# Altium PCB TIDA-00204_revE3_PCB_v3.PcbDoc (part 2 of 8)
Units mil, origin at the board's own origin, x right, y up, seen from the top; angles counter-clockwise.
Board outline 4600 x 3740 mil, 8 copper layers (TopLayer - S1 (.GTL), MidLayer1 - S2 (.G1), MidLayer2 - S3 (.G2), MidLayer3 - S4 (.G3), MidLayer4 - S5 (.G4), MidLayer5 - S6 (.G5), MidLayer6 - S7 (.G6), BottomLayer - S8 (.GBL)), stack 58.938 mil thick; 537 components, 354 nets, 2015 pads, 1067 vias.

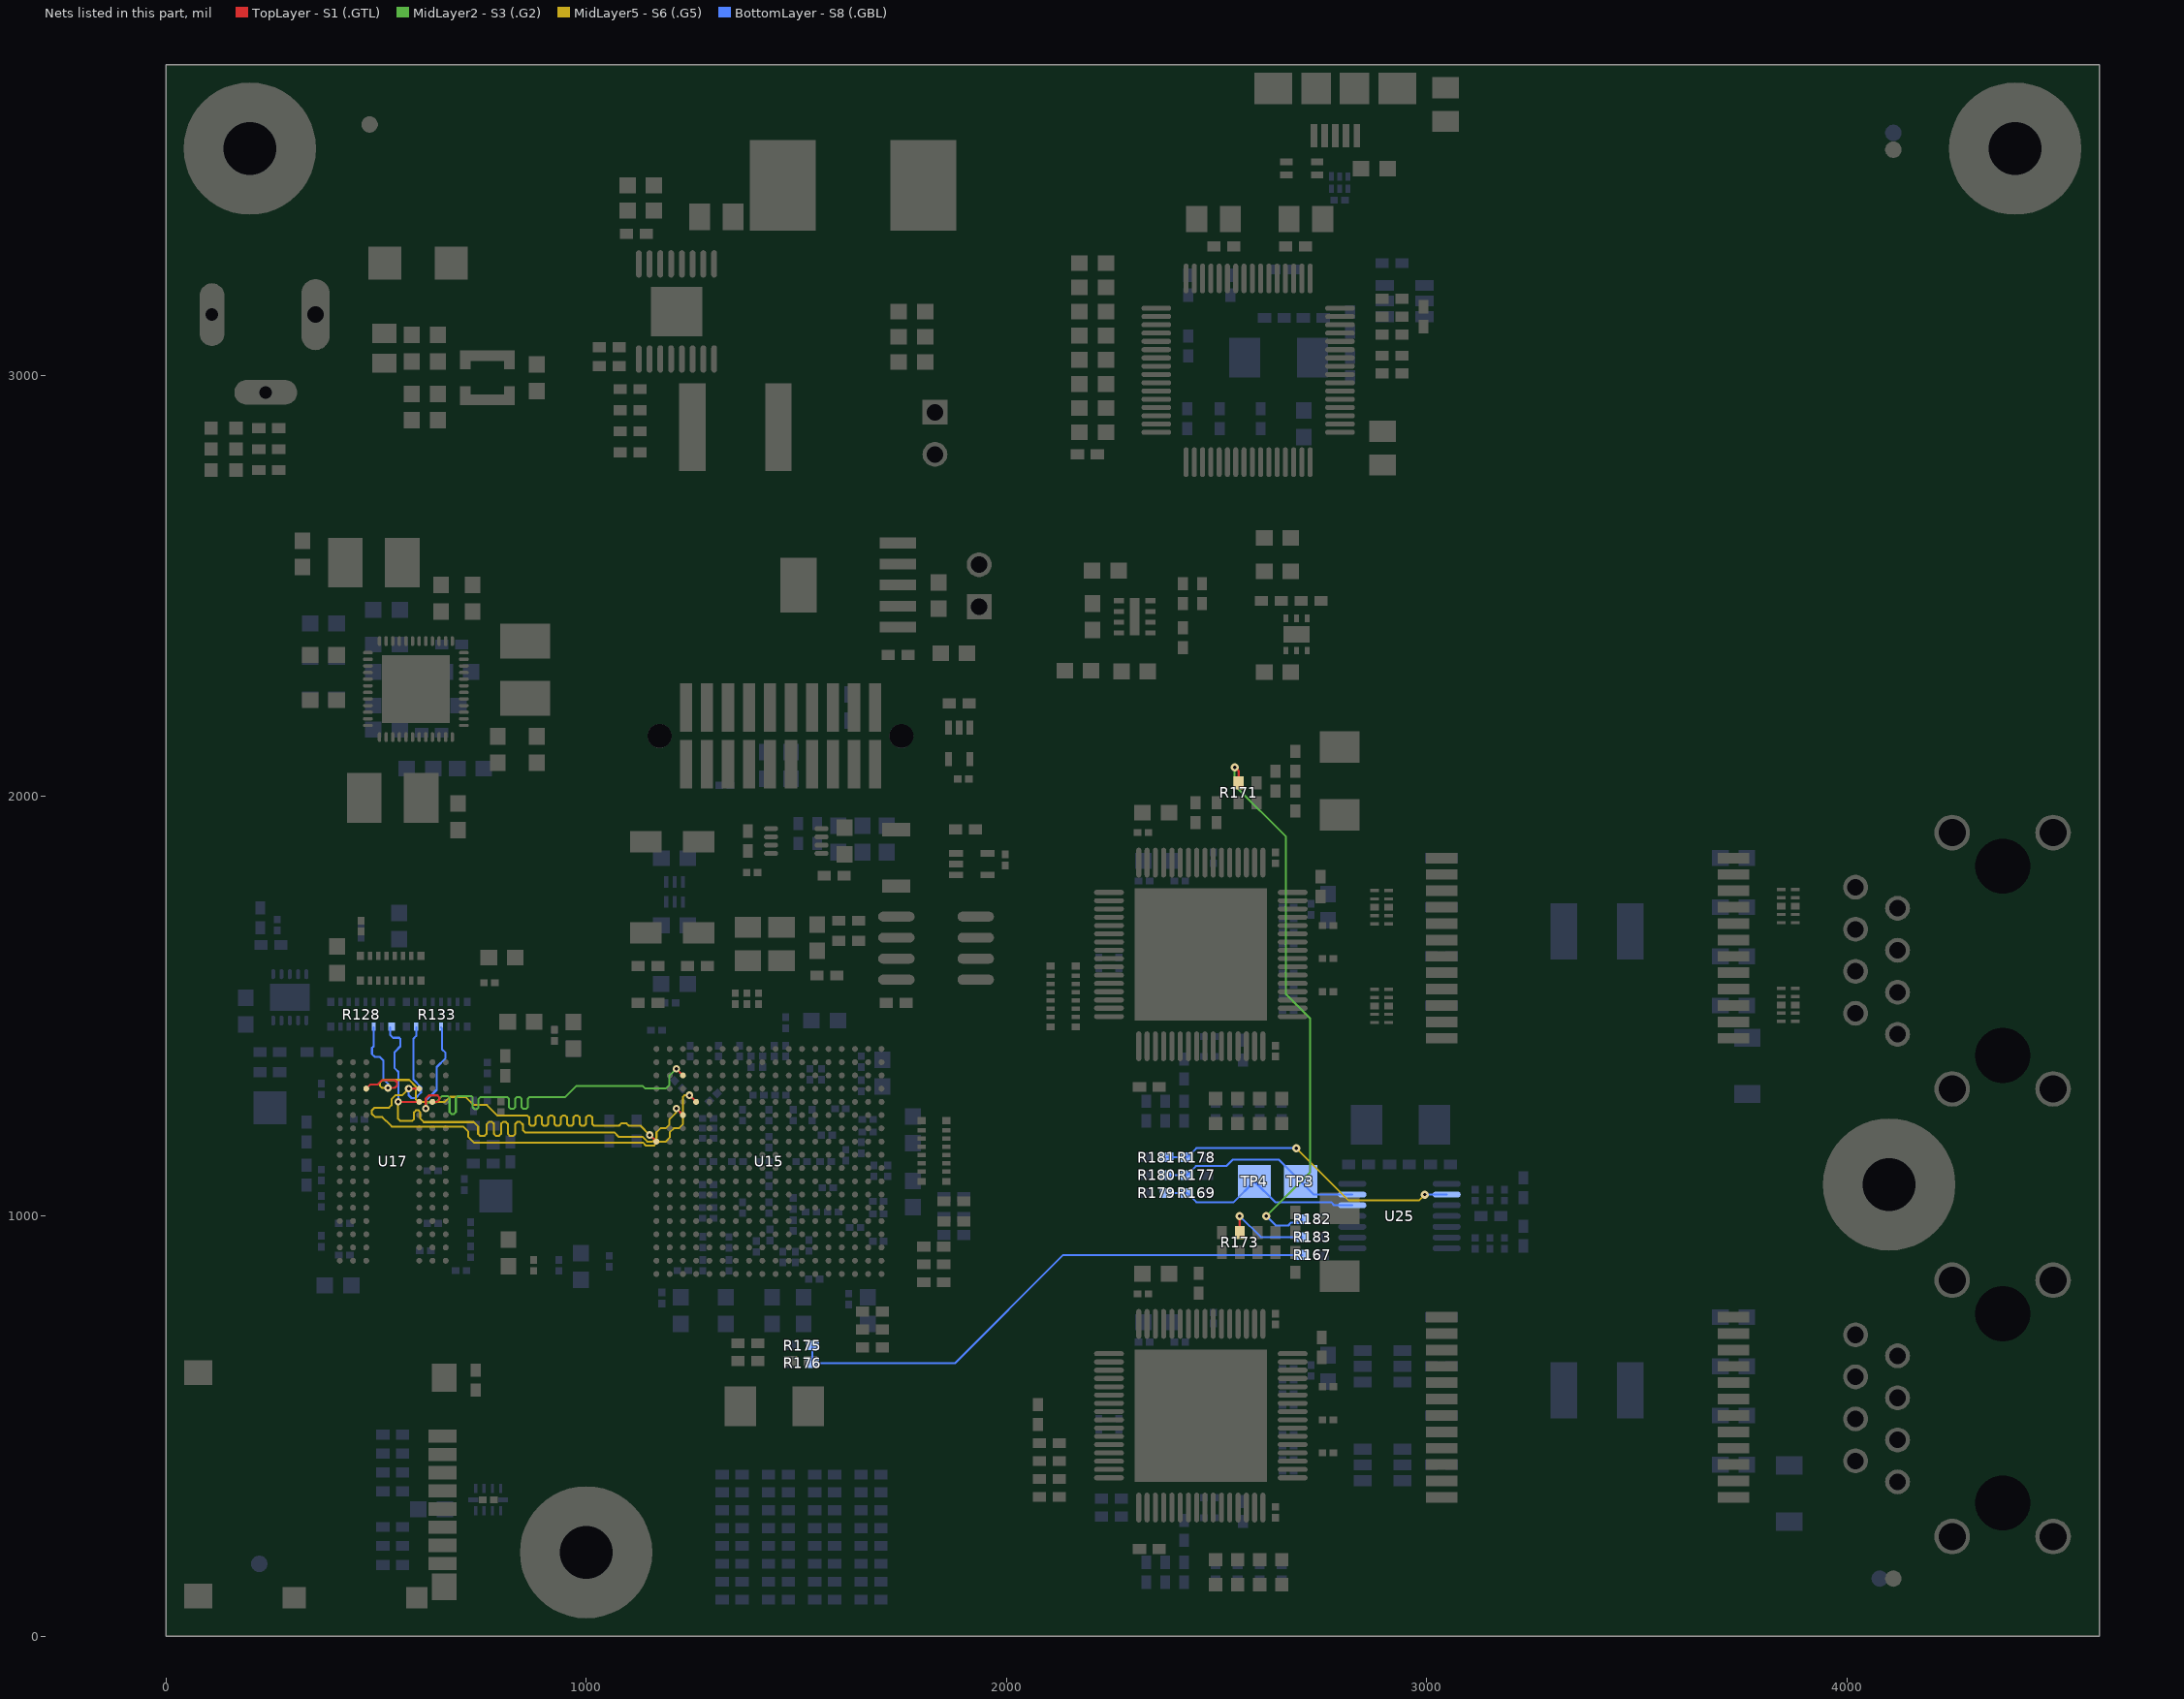
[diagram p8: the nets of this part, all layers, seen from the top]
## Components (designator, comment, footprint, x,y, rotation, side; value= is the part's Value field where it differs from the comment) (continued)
R139 "CRCW06030000Z0EA" 0603 2205,3267.5 r180 top
R140 "CRCW06030000Z0EA" 0603 2205,3210 r180 top
R141 "CRCW06030000Z0EA" 0603 2205,3152.5 r180 top
R142 "CRCW06030000Z0EA" 0603 2205,3095 r180 top
R143 "CRCW06030000Z0EA" 0603 2205,3037.5 r180 top
R144 "CRCW06030000Z0EA" 0603 2205,2980 r180 top
R145 "CRCW06030000Z0EA" 0603 2205,2922.5 r180 top
R146 "CRCW04024K70JNED" 0402 2192.5,2812.5 r0 top
R147 "CRCW06030000Z0EA" 0603 2205,2865 r180 top
R148 "CRCW040210K0JNED" 0402 2917.5,3182.5 r0 top
R149 "CRCW040210K0JNED" 0402 2917.5,3140 r0 top
R150 "CRCW040210K0JNED" 0402 2992.5,3140 r90 top
R151 "CRCW04024K70JNED" 0402 1287.5,2227.5 r90 bottom
R152 "CRCW04024K70JNED" 0402 1505,1910 r270 bottom
R153 "CRCW04024K70JNED" 0402 1237.5,2227.5 r90 bottom
R154 "CRCW04022K20JNED" 0402 2917.5,3097.5 r180 top
R155 "CRCW04024K75FKED" 0402 2917.5,3005 r0 top
R156 "CRCW04022K20JNED" 0402 2432.5,3215 r90 bottom
R157 "CRCW040212K1FKED" 0402 2660,3252.5 r180 bottom
R158 "CRCW040210K0FKED" 0402 2917.5,3047.5 r180 top
R159 "CRCW06030000Z0EA" 0603 1430,2072.5 r270 bottom
R160 "CRCW06030000Z0EA" 0603 1487.5,2072.5 r270 bottom
R161 "CRCW06030000Z0EA" 0603 1657.5,1897.5 r90 bottom
R162 "CRCW06030000Z0EA" 0603 1632.5,2210 r90 bottom
R163 "CRCW06030000Z0EA" 0603 1715,1897.5 r90 bottom
R164 "CRCW06030000Z0EA" 0603 1600,1897.5 r90 bottom
R165 "CRCW04024K70JNED" 0402 1887.5,2220 r0 top
R166 "CRCW04024K70JNED" 0402 3152.5,1000 r180 bottom
R167 "CRCW040236R0JNED" 0402 2727.5,907.5 r180 bottom
R168 "CRCW04021M00FKED" 0402 2935,1122.5 r180 bottom
R169 "CRCW04021K00FKED" 0402 2452.5,1055 r0 bottom
R170 "CRCW04020000Z0ED" 0402 2595,2007.5 r270 top
R171 "CRCW04020000Z0ED" 0402 2552.5,2007.5 r90 top
R172 "CRCW04020000Z0ED" 0402 2597.5,937.5 r270 top
R173 "CRCW04020000Z0ED" 0402 2555,937.5 r90 top
R174 "CRCW04020000Z0ED" 0402 1385,697.5 r180 top
R175 "CRCW04020000Z0ED" 0402 1515,692.5 r0 bottom
R176 "CRCW040249R9FKED" 0402 1515,650 r0 bottom
R177 "CRCW04021K00FKED" 0402 2452.5,1097.5 r0 bottom
R178 "CRCW04021K00FKED" 0402 2452.5,1140 r0 bottom
R179 "CRCW04021K00FKED" 0402 2357.5,1055 r0 bottom
R180 "CRCW04021K00FKED" 0402 2357.5,1097.5 r0 bottom
R181 "CRCW04021K00FKED" 0402 2357.5,1140 r0 bottom
R182 "CRCW040236R0JNED" 0402 2727.5,992.5 r180 bottom
R183 "CRCW040236R0JNED" 0402 2727.5,950 r180 bottom
S1 "B3U-1000P" SW_B3U-1000P 1737.5,1852.5 r270 top
T1 "HX5008FNL" PULSE_HX5008FNL 3382.5,1637.5 r0 top
T2 "HX5008FNL" PULSE_HX5008FNL 3382.5,545 r0 top
TP1 "TESTPOINT" OXLEY_SMOX_060_B1_LP 247.5,1257.5 r270 bottom
TP2 "TESTPOINT" OXLEY_SMOX_060_B1_LP 785,1047.5 r270 bottom
TP3 "TESTPOINT" OXLEY_SMOX_060_B1_LP 2700,1082.5 r180 bottom
TP4 "TESTPOINT" OXLEY_SMOX_060_B1_LP 2590,1082.5 r180 bottom
U1 "LM46002PWP" PWP0016A_N 1215,3152.5 r270 top
U2 "TPS73733DCQ" DCQ0006A_N 1623.5,2501.5 r180 top
U3 "LMZ10501SIL" SIL0008A 2305,2426 r180 top
U5 "TPS72011DRV" DRV0006A 2690,2384 r90 top
U6 "DP83867IRPAPR" PAP0064M_N 2462.5,1622.5 r180 top
U7 "TPD4E05U06DQA" DQA0010A 2892.5,1735 r180 top
U8 "TPD4E05U06DQA" DQA0010A 3860,1737.5 r180 top
U9 "TPD4E05U06DQA" DQA0010A 2892.5,1500 r180 top
U10 "TPD4E05U06DQA" DQA0010A 3860,1502.5 r180 top
U11 "SN74AHC1G08DCK" DCK0005A_N 1917.5,1837.5 r0 top
U12 "DP83867IRPAPR" PAP0064M_N 2462.5,525 r180 top
U13 "TPS65910A3A1RSL" RSL0048A 595,2254 r0 top
U14 "TPS71718DSER" DSE0006A 1210.47,1771.69 r90 bottom
U15 "AM3359BZCZA80" ZCZ0324A 1435,1130 r0 top locked
U16 "SN74AUP2G08DCU" DCU0008A_N 1500,1892.5 r180 top
U17 "MT41J128M16JT-125K TR" 96-FBGA 540,1130 r180 top
U18 "TPD6E001RSER" RSE0010A 767.28,325 r270 bottom
U19 "CAT24C256WI-GT3" SOIC-8 1832.5,1637.5 r180 top
U20 "TPS51200DRCR" DRC0010A 295,1520.5 r270 bottom
U21 "TPD4S012DRYR" DRY0006A_GCD 2792.5,3459 r270 bottom
U22 "FT2232HL-REEL" LQFP64_N 2575,3012.5 r270 top
U23 "93LC56B-I/OT" SOT-23-6 2947.5,3177.5 r180 bottom
U24 "SN74LVC1G06DCK" DCK0005A_N 1887.5,2125 r270 top
U25 "CDCE913PW" PW0014A_N 2935,1000 r180 bottom
Y1 "ABM3-25.000MHZ-D2Y-T" XTAL_ABM3 2792.5,2035 r90 top
Y2 "ABM3-25.000MHZ-D2Y-T" XTAL_ABM3 2792.5,937.5 r90 top
Y3 "ABM3-24.000MHZ-D2Y-T" XTAL_ABM3 1447.5,547.5 r180 top
Y4 "MC-306 32.7680K-A0:ROHS" XTAL_MC-306 1205,1782.5 r180 top
Y5 "ABM3-12.000MHZ-D2Y-T" XTAL_ABM3 2647.5,3042.5 r0 bottom
Y6 "ABM3-25.000MHZ-D2Y-T" XTAL_ABM3 2937.5,1217.5 r180 bottom

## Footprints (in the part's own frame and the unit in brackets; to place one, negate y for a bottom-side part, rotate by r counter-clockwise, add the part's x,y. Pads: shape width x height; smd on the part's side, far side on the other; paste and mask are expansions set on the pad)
96-FBGA [mil] "BGA, 96-Balls, Body 9x14mm, Pitch 0.8mm"
  round 14 smd: A1(-125.98,236.22) A2(-94.49,236.22) A3(-62.99,236.22) A7(62.99,236.22) A8(94.49,236.22) A9(125.98,236.22) B1(-125.98,204.72) B2(-94.49,204.72) B3(-62.99,204.72) B7(62.99,204.72) B8(94.49,204.72) B9(125.98,204.72) C1(-125.98,173.23) C2(-94.49,173.23) C3(-62.99,173.23) C7(62.99,173.23) C8(94.49,173.23) C9(125.98,173.23) D1(-125.98,141.73) D2(-94.49,141.73) D3(-62.99,141.73) D7(62.99,141.73) D8(94.49,141.73) D9(125.98,141.73) E1(-125.98,110.24) E2(-94.49,110.24) E3(-62.99,110.24) E7(62.99,110.24) E8(94.49,110.24) E9(125.98,110.24) F1(-125.98,78.74) F2(-94.49,78.74) F3(-62.99,78.74) F7(62.99,78.74) F8(94.49,78.74) F9(125.98,78.74) G1(-125.98,47.24) G2(-94.49,47.24) G3(-62.99,47.24) G7(62.99,47.24) G8(94.49,47.24) G9(125.98,47.24) H1(-125.98,15.75) H2(-94.49,15.75) H3(-62.99,15.75) H7(62.99,15.75) H8(94.49,15.75) H9(125.98,15.75) J1(-125.98,-15.75) J2(-94.49,-15.75) J3(-62.99,-15.75) J7(62.99,-15.75) J8(94.49,-15.75) J9(125.98,-15.75) K1(-125.98,-47.24) K2(-94.49,-47.24) K3(-62.99,-47.24) K7(62.99,-47.24) K8(94.49,-47.24) K9(125.98,-47.24) L1(-125.98,-78.74) L2(-94.49,-78.74) L3(-62.99,-78.74) L7(62.99,-78.74) L8(94.49,-78.74) L9(125.98,-78.74) M1(-125.98,-110.24) M2(-94.49,-110.24) M3(-62.99,-110.24) M7(62.99,-110.24) M8(94.49,-110.24) M9(125.98,-110.24) N1(-125.98,-141.73) N2(-94.49,-141.73) N3(-62.99,-141.73) N7(62.99,-141.73) N8(94.49,-141.73) N9(125.98,-141.73) P1(-125.98,-173.23) P2(-94.49,-173.23) P3(-62.99,-173.23) P7(62.99,-173.23) P8(94.49,-173.23) P9(125.98,-173.23) R1(-125.98,-204.72) R2(-94.49,-204.72) R3(-62.99,-204.72) R7(62.99,-204.72) R8(94.49,-204.72) R9(125.98,-204.72) T1(-125.98,-236.22) T2(-94.49,-236.22) T3(-62.99,-236.22) T7(62.99,-236.22) T8(94.49,-236.22) T9(125.98,-236.22)
  silkscreen extent -208,-276 177,276, body extent -177,-276 177,276, height 48
0201 [mm] "Data from Kemet datasheet CC101_COM dated 7/28/11"
  rect 0.46x0.42 smd mask+0.048: 1(-0.33,0) 2(0.33,0)
  body extent -0.31,-0.16 0.31,0.16, height 0.26
0402 [mm] "0402 from SM-752 data"
  rect 0.8x0.6 smd: 1(-0.6,0) 2(0.6,0)
  silkscreen extent -1.22,-0.52 1.22,0.52, body extent -0.55,-0.3 0.55,0.3, height 0.6
0603 [mm] "0603 from SM-752 data"
  rect 1x0.95 smd: 1(-0.8,0) 2(0.8,0)
  silkscreen extent -1.52,-0.69 1.52,0.69, body extent -0.87,-0.47 0.87,0.47, height 0.85
0805_145 [mm] "0805 / 1.45mm height"
  rect 1.15x1.45 smd: 1(-0.9,0) 2(0.9,0)
  silkscreen extent -0.1,-0.8 0.1,0.8, body extent -1.1,-0.72 1.1,0.72, height 1.45
0805_HV [mil] "0805 with 30mil clearance between pads"
  rect 50x63 smd: 1(-40,0) 2(40,0)
  silkscreen extent -72,-40 74,40, body extent -43,-29 43,29, height 43
1206_190 [mm] "1206_190"
  rect 1.1x1.6 smd: 1(-1.7,0) 2(1.7,0)
  silkscreen extent -0.9,-1 0.9,1, body extent -1.75,-0.95 1.75,0.95, height 1.9
1812 [mm]
  rect 1.6x3.4 smd: 1(-2,0) 2(2,0)
  silkscreen extent -0.8,-1.6 0.8,1.6, body extent -2.4,-1.7 2.4,1.7, height 1.35
2220 [mm] "Chip Capacitor, Body 5.7x5.0mm, IPC Medium Density"
  rect 1.6x5.3 smd: 1(-2.6,0) 2(2.6,0)
  silkscreen extent -3.69,-2.94 3.69,2.94, body extent -2.95,-2.62 2.95,2.62, height 1.35
CONN_PEC02SAAN [mm] "SULLINS"
  rect 1.5x1.5 hole 1: 1(-1.27,0)
  round 1.5 hole 1: 2(1.27,0)
  silkscreen extent -3.45,-1.27 2.54,1.27, body extent -2.54,-1.27 2.54,1.27, height 8.38
CONN_RAPC722X [mm] "Conn_DC Jack"
  oval 1.7x4.3 hole 1.01 slot 3.56 at 90 deg: 1(-13.741,0)
  oval 1.5x3.8 hole 0.76 slot 3.05 at 90 deg: 2(-7.493,0)
  oval 3.8x1.5 hole 0.76 slot 3.05 at 0 deg: 3(-10.744,4.7)
  silkscreen extent -14.48,-4.57 0.25,4.57, body extent -14.5,-4.57 0.23,4.83, height 11.18
DCK0005A_N [mm] "SOT353, 5-Leads, Body 2x1.3mm, Pitch 0.65mm, Lead Span 2.1mm, IPC Medium Density"
  rect 0.85x0.4 smd: 1(-0.95,0.65) 2(-0.95,0) 3(-0.95,-0.65) 4(0.95,-0.65) 5(0.95,0.65)
  silkscreen extent -0.15,-1.1 0.15,1.1, body extent -1.14,-1 1.14,1, height 0.94
DCQ0006A_N [mm] "SOT223, 6-Leads, Body 6.6x7.3mm (max), Pitch 1.27mm, IPC Medium Density"
  rect 2.2x0.65 smd: 1(-3,2.54) 2(-3,1.27) 3(-3,0) 4(-3,-1.27) 5(-3,-2.54)
  rect 2.2x3.3 smd: 6(3,0)
  silkscreen extent -1.5,-3.27 1.5,3.27, body extent -3.48,-3.25 3.48,3.25, height 1.64
DCU0008A_N [mm] "TSSOP, 8-Leads, Body 2x2.3mm, Pitch 0.5mm, IPC Medium Density"
  oval 0.85x0.3 smd: 1(-1.525,0.75) 2(-1.525,0.25) 3(-1.525,-0.25) 4(-1.525,-0.75) 5(1.525,-0.75) 6(1.525,-0.25) 7(1.525,0.25) 8(1.525,0.75)
  silkscreen extent -0.6,-1.05 0.6,1.05, body extent -1.2,-1.05 1.2,1.05, height 0.91
DQA0010A [mm] "SON, 10-Leads, Body 1x2.5mm, Pitch 0.5mm, TI Recommended"
  rect 0.55x0.2 smd: 1(-0.425,1) 2(-0.425,0.5) 4(-0.425,-0.5) 5(-0.425,-1) 6(0.425,-1) 7(0.425,-0.5) 9(0.425,0.5) 10(0.425,1)
  rect 0.55x0.4 smd: 3(-0.425,0) 8(0.425,0)
  silkscreen extent -1,-1.45 0.55,1.5, body extent -0.55,-1.3 0.55,1.3, height 0.56
DRC0010A [mm] "SON, 10-Leads, Body 3x3mm, Pitch 0.5mm, Thermal Pad 2.4x1.65mm, TI Recommended"
  oval 0.6x0.24 smd: 1(-1.4,1) 2(-1.4,0.5) 3(-1.4,0) 4(-1.4,-0.5) 5(-1.4,-1) 6(1.4,-1) 7(1.4,-0.5) 8(1.4,0) 9(1.4,0.5) 10(1.4,1)
  rect 1.65x2.4 smd paste-0.825: 11(0,0)
  TopLayer - S1 (.GTL) region: 0.135,-1.1 0.365,-1.1 0.365,-1.5 0.135,-1.5
  TopLayer - S1 (.GTL) region: -0.135,-1.5 -0.365,-1.5 -0.365,-1.1 -0.135,-1.1
  TopLayer - S1 (.GTL) region: -0.135,1.1 -0.365,1.1 -0.365,1.5 -0.135,1.5
  TopLayer - S1 (.GTL) region: 0.135,1.5 0.365,1.5 0.365,1.1 0.135,1.1
  silkscreen extent -1.7,-1.7 1.7,1.7, body extent -1.55,-1.55 1.55,1.55, height 1.01
DRV0006A [mm] "SON, 6-Leads, Body 2x2mm, Pitch 0.65mm, Thermal Pad 1.6x1mm, TI Recommended"
  rect 0.45x0.3 smd: 1(-0.975,0.65) 2(-0.975,0) 3(-0.975,-0.65) 4(0.975,-0.65) 5(0.975,0) 6(0.975,0.65)
  rect 1x1.6 smd paste-0.5: 7(0,0)
  silkscreen extent -1.05,-1.2 1.05,1.2, body extent -1.05,-1.05 1.05,1.05, height 0.81
DRY0006A_GCD [mm] "PSON, 6-Leads, Body 1x1.45mm, Pitch 0.5mm, TI Recommended"
  rect 0.52x0.3 smd mask+0.05: 1(-0.38,0.5)
  rect 0.49x0.3 smd: 2(-0.375,0) 3(-0.375,-0.5) 4(0.375,-0.5) 5(0.375,0) 6(0.375,0.5)
  silkscreen extent -0.67,0.8 -0.58,0.9, body extent -0.53,-0.75 0.53,0.75, height 0.61
DSE0006A [mm] "TI recommended land pattern"
  rect 0.66x0.25 smd: 1(-0.62,0.5)
  rect 0.7x0.25 smd: 2(-0.6,0) 3(-0.6,-0.5) 4(0.6,-0.5) 5(0.6,0) 6(0.6,0.5)
  TopLayer - S1 (.GTL) region: -0.3,0.625 -0.25,0.625 -0.15,0.525 -0.15,0.375 -0.3,0.375
  silkscreen extent -0.9,-0.92 0.9,0.92, body extent -0.77,-0.77 0.77,0.77, height 0.8
FCI_10104111-0001LF [mm] "SMD, 5-Leads, Body 7.5x5.6mm, Pitch 0.65mm"
  rect 0.4x1.4 smd: 1(-1.3,2.85) 2(-0.65,2.85) 3(0,2.85) 4(0.65,2.85) 5(1.3,2.85)
  rect 2.3x1.9 smd: MP1(-3.75,0) MP4(3.75,0)
  rect 1.775x1.9 smd: MP2(-1.162,0) MP3(1.162,0)
  silkscreen extent -3.75,1.35 3.75,3.52, body extent -4.4,-2.77 4.4,2.86, height 2.81
Fiducial10-20 [mm]
  round 1 smd mask+0.5: 1(0,0)
  TopLayer - S1 (.GTL) keep-out circle w1.178: c0,0 r0.5
Keystone_1902C [mil] "Hex Standoff, 4-40 threaded, nylon"
  body extent -145,-126 146,126, height 501
"LG L29K_GREEN" [mm] "OSRAM"
  rect 0.8x0.8 smd paste-0.4: 1(-0.75,0) 2(0.75,0)
  silkscreen extent -0.1,-0.5 1.45,0.5, body extent -0.9,-0.45 0.9,0.45, height 0.67
"LO L29K_Orange" [mm] "SMD, 2-Leads, Body 1.3x0.8mm"
  rect 0.8x0.8 smd paste-0.4: 1(-0.75,0) 2(0.75,0)
  silkscreen extent -1.2,-0.8 1.75,0.8, body extent -0.9,-0.45 0.9,0.45, height 0.67
LPS3010 [mm] "Coilcraft recommended land pattern.  Document 428-2, rev 10/6/08"
  rect 0.63x3.3 smd: 1(-1.335,0) 2(1.335,0)
  rect 1.14x0.64 smd: 1(-1.08,1.33) 1(-1.08,-1.33) 2(1.08,1.33) 2(1.08,-1.33)
  silkscreen extent -2.59,-2 2,2, body extent -1.58,-1.58 1.58,1.58, height 1.02
LQFP64_N [mm] "Thin QFP, 64-Leads, Body 10x10mm, Pitch 0.5mm, IPC Medium Density"
  oval 1.8x0.3 smd: 1(-5.55,3.75) 2(-5.55,3.25) 3(-5.55,2.75) 4(-5.55,2.25) 5(-5.55,1.75) 6(-5.55,1.25) 7(-5.55,0.75) 8(-5.55,0.25) 9(-5.55,-0.25) 10(-5.55,-0.75) 11(-5.55,-1.25) 12(-5.55,-1.75) 13(-5.55,-2.25) 14(-5.55,-2.75) 15(-5.55,-3.25) 16(-5.55,-3.75) 33(5.55,-3.75) 34(5.55,-3.25) 35(5.55,-2.75) 36(5.55,-2.25) 37(5.55,-1.75) 38(5.55,-1.25) 39(5.55,-0.75) 40(5.55,-0.25) 41(5.55,0.25) 42(5.55,0.75) 43(5.55,1.25) 44(5.55,1.75) 45(5.55,2.25) 46(5.55,2.75) 47(5.55,3.25) 48(5.55,3.75)
  oval 0.3x1.8 smd: 17(-3.75,-5.55) 18(-3.25,-5.55) 19(-2.75,-5.55) 20(-2.25,-5.55) 21(-1.75,-5.55) 22(-1.25,-5.55) 23(-0.75,-5.55) 24(-0.25,-5.55) 25(0.25,-5.55) 26(0.75,-5.55) 27(1.25,-5.55) 28(1.75,-5.55) 29(2.25,-5.55) 30(2.75,-5.55) 31(3.25,-5.55) 32(3.75,-5.55) 49(3.75,5.55) 50(3.25,5.55) 51(2.75,5.55) 52(2.25,5.55) 53(1.75,5.55) 54(1.25,5.55) 55(0.75,5.55) 56(0.25,5.55) 57(-0.25,5.55) 58(-0.75,5.55) 59(-1.25,5.55) 60(-1.75,5.55) 61(-2.25,5.55) 62(-2.75,5.55) 63(-3.25,5.55) 64(-3.75,5.55)
  silkscreen extent -5.67,-4.25 4.25,4.58, body extent -5,-5 5,5, height 1.6
"LS L29K_Red" [mm] "SMD, 2-Leads, Body 1.3x0.8mm"
  rect 0.8x0.8 smd paste-0.4: 1(-0.75,0) 2(0.75,0)
  silkscreen extent -0.1,-0.5 1.45,0.5, body extent -0.9,-0.45 0.9,0.45, height 0.67
"LY L29K_Yellow" [mm] "OSRAM"
  rect 0.8x0.8 smd paste-0.4: 1(-0.75,0) 2(0.75,0)
  silkscreen extent -0.1,-0.5 1.45,0.5, body extent -0.9,-0.45 0.9,0.45, height 0.67
Molex_43202-8916 [mm] "Modular Jack(Shielded), R/A, TH"
  round 1.5 hole 1: 1(-4.445,5.207) 2(-3.175,7.747) 3(-1.905,5.207) 4(-0.635,7.747) 5(0.635,5.207) 6(1.905,7.747) 7(3.175,5.207) 8(4.445,7.747)
  round 2.15 hole 1.65: 9(-7.745,1.907) 10(7.745,1.907) 11(-7.745,-4.193) 12(7.745,-4.193)
  round 0 hole 3.33 unplated: MH1(-5.715,-1.143) MH2(5.715,-1.143)
  silkscreen extent -8.97,-9.32 8.18,9.32, body extent -8.18,-9.32 8.18,9.32, height 11.99
Molex_502774-0891 [mm] "SMD, 14-Leads, Body 15x14.3mm, Pitch 1.1mm"
  rect 0.8x1.68 smd: 1(-2.9,7.385) 2(-1.8,7.385) 3(-0.7,7.385) 4(0.4,7.385) 5(1.5,7.385) 6(2.6,7.385) 7(3.7,7.385) 8(4.8,7.385)
  rect 1.6x1.5 smd: 9(6.21,7.475)
  rect 1.29x1.3 smd: 10(6.855,5.825)
  rect 1.29x1.4 smd: 11(6.855,-1.575)
  rect 1.5x1.7 smd: 12(6.75,-7.375) 13(-6.75,-7.375)
  rect 1.7x1.5 smd: 14(-6.45,7.475)
  silkscreen extent -7.15,-7.88 7.15,8.9, body extent -7.15,-8 7.15,8, height 1.78
MSS1260 [mm]
  rect 4x5.5 smd: 1(-4.25,0) 2(4.25,0)
  silkscreen extent -6.2,-6.2 6.2,6.2, body extent -6.15,-6.15 6.15,6.15, height 6.25
"NY PMS 440 0025 PH" [mm] "4-40 nylon screw and mounting hole"
  round 8 hole 3.2: 1(0,0)
  body extent -3.3,-3.3 3.3,3.3, height 2.69
OXLEY_SMOX_060_B1_LP [mm] "Test-Point, SMD"
  rect 2x2 smd mask+0.048: 1(0,0)
  silkscreen extent -1.4,-1.4 1.4,1.4, body extent -0.99,-1 1,1, height 1.4
PAP0064M_N [mm] "Thin QFP, 64-Leads, Body 10x10mm, Pitch 0.5mm, Thermal Pad 8x8mm, IPC Medium Density"
  oval 1.8x0.3 smd: 1(-5.55,3.75) 2(-5.55,3.25) 3(-5.55,2.75) 4(-5.55,2.25) 5(-5.55,1.75) 6(-5.55,1.25) 7(-5.55,0.75) 8(-5.55,0.25) 9(-5.55,-0.25) 10(-5.55,-0.75) 11(-5.55,-1.25) 12(-5.55,-1.75) 13(-5.55,-2.25) 14(-5.55,-2.75) 15(-5.55,-3.25) 16(-5.55,-3.75) 33(5.55,-3.75) 34(5.55,-3.25) 35(5.55,-2.75) 36(5.55,-2.25) 37(5.55,-1.75) 38(5.55,-1.25) 39(5.55,-0.75) 40(5.55,-0.25) 41(5.55,0.25) 42(5.55,0.75) 43(5.55,1.25) 44(5.55,1.75) 45(5.55,2.25) 46(5.55,2.75) 47(5.55,3.25) 48(5.55,3.75)
  oval 0.3x1.8 smd: 17(-3.75,-5.55) 18(-3.25,-5.55) 19(-2.75,-5.55) 20(-2.25,-5.55) 21(-1.75,-5.55) 22(-1.25,-5.55) 23(-0.75,-5.55) 24(-0.25,-5.55) 25(0.25,-5.55) 26(0.75,-5.55) 27(1.25,-5.55) 28(1.75,-5.55) 29(2.25,-5.55) 30(2.75,-5.55) 31(3.25,-5.55) 32(3.75,-5.55) 49(3.75,5.55) 50(3.25,5.55) 51(2.75,5.55) 52(2.25,5.55) 53(1.75,5.55) 54(1.25,5.55) 55(0.75,5.55) 56(0.25,5.55) 57(-0.25,5.55) 58(-0.75,5.55) 59(-1.25,5.55) 60(-1.75,5.55) 61(-2.25,5.55) 62(-2.75,5.55) 63(-3.25,5.55) 64(-3.75,5.55)
  rect 8x8 smd paste-1.78 mask-1.78: 65(0,0)
  silkscreen extent -5.68,-4.25 4.25,4.57, body extent -6,-6 6,6, height 1.12
Pb-Free_Overlay_Small [mil]
  silkscreen extent -46,-46 46,46
PULSE_HX5008FNL [mm] "SMD, 24-Leads, Body 17.86x13.16mm, Pitch 0.99mm"
  rect 1.905x0.64 smd: 1(-8.828,5.445) 2(-8.828,4.455) 3(-8.828,3.465) 4(-8.828,2.475) 5(-8.828,1.485) 6(-8.828,0.495) 7(-8.828,-0.495) 8(-8.828,-1.485) 9(-8.828,-2.475) 10(-8.828,-3.465) 11(-8.828,-4.455) 12(-8.828,-5.445) 13(8.828,-5.445) 14(8.828,-4.455) 15(8.828,-3.465) 16(8.828,-2.475) 17(8.828,-1.485) 18(8.828,-0.495) 19(8.828,0.495) 20(8.828,1.485) 21(8.828,2.475) 22(8.828,3.465) 23(8.828,4.455) 24(8.828,5.445)
  silkscreen extent -9,-6.64 9,7, body extent -9.4,-6.64 9.4,6.65, height 6.26
PW0014A_N [mm] "TSOP, 14-Leads, Body 5x4.4mm, Pitch 0.65mm, IPC Medium Density"
  oval 1.7x0.35 smd: 1(-2.85,1.95) 2(-2.85,1.3) 3(-2.85,0.65) 4(-2.85,0) 5(-2.85,-0.65) 6(-2.85,-1.3) 7(-2.85,-1.95) 8(2.85,-1.95) 9(2.85,-1.3) 10(2.85,-0.65) 11(2.85,0) 12(2.85,0.65) 13(2.85,1.3) 14(2.85,1.95)
  silkscreen extent -3.47,-2.55 1.7,2.55, body extent -3.21,-2.5 3.21,2.5, height 0.98
PWP0016A_N [mm] "TSOP, 16-Leads, Body 5x4.4mm, Pitch 0.65mm, Exposed Pad, IPC Medium Density"
  oval 1.65x0.35 smd: 1(-2.875,2.275) 2(-2.875,1.625) 3(-2.875,0.975) 4(-2.875,0.325) 5(-2.875,-0.325) 6(-2.875,-0.975) 7(-2.875,-1.625) 8(-2.875,-2.275) 9(2.875,-2.275) 10(2.875,-1.625) 11(2.875,-0.975) 12(2.875,-0.325) 13(2.875,0.325) 14(2.875,0.975) 15(2.875,1.625) 16(2.875,2.275)
  rect 3x3.1 smd: 17(0,0)
  silkscreen extent -1.5,-2.55 1.5,2.55, body extent -3.21,-2.5 3.21,2.5, height 0.99
RESCAXS_EXB-2HV [mm] "Panasonic Resistor Array"
  rect 0.425x0.5 smd mask+0.07: 1(-1.837,-0.75) 8(1.837,-0.75) 9(1.837,0.75) 16(-1.837,0.75)
  rect 0.25x0.5 smd mask+0.07: 2(-1.25,-0.75) 3(-0.75,-0.75) 4(-0.25,-0.75) 5(0.25,-0.75) 6(0.75,-0.75) 7(1.25,-0.75) 10(1.25,0.75) 11(0.75,0.75) 12(0.25,0.75) 13(-0.25,0.75) 14(-0.75,0.75) 15(-1.25,0.75)
  silkscreen extent -2.05,-0.25 2.05,0.25, body extent -1.95,-0.8 1.95,0.8, height 0.55
RSE0010A [mm] "QFN, 10-Leads, Body 1.5x2mm, Pitch 0.5mm, TI Recommended"
  rect 0.55x0.2 smd: 1(-0.675,0.75) 2(-0.675,0.25) 3(-0.675,-0.25) 4(-0.675,-0.75) 6(0.675,-0.75) 7(0.675,-0.25) 8(0.675,0.25) 9(0.675,0.75)
  rect 0.3x0.6 smd: 5(0,-0.9) 10(0,0.9)
  silkscreen extent -1.07,-1.17 0.77,1.18, body extent -0.77,-1.02 0.78,1.03, height 0.61
RSL0048A [mm]
  oval 0.6x0.2 smd: 1(-2.9,2.2) 2(-2.9,1.8) 3(-2.9,1.4) 4(-2.9,1) 5(-2.9,0.6) 6(-2.9,0.2) 7(-2.9,-0.2) 8(-2.9,-0.6) 9(-2.9,-1) 10(-2.9,-1.4) 11(-2.9,-1.8) 12(-2.9,-2.2) 25(2.9,-2.2) 26(2.9,-1.8) 27(2.9,-1.4) 28(2.9,-1) 29(2.9,-0.6) 30(2.9,-0.2) 31(2.9,0.2) 32(2.9,0.6) 33(2.9,1) 34(2.9,1.4) 35(2.9,1.8) 36(2.9,2.2)
  oval 0.2x0.6 smd: 13(-2.2,-2.9) 14(-1.8,-2.9) 15(-1.4,-2.9) 16(-1,-2.9) 17(-0.6,-2.9) 18(-0.2,-2.9) 19(0.2,-2.9) 20(0.6,-2.9) 21(1,-2.9) 22(1.4,-2.9) 23(1.8,-2.9) 24(2.2,-2.9) 37(2.2,2.9) 38(1.8,2.9) 39(1.4,2.9) 40(1,2.9) 41(0.6,2.9) 42(0.2,2.9) 43(-0.2,2.9) 44(-0.6,2.9) 45(-1,2.9) 46(-1.4,2.9) 47(-1.8,2.9) 48(-2.2,2.9)
  rect 4.1x4.1 smd paste-2.187: 49(0,0)
  silkscreen extent -3.17,-3.17 3.17,3.17, body extent -3.07,-3.07 3.07,3.07, height 1.01
Samtec_TFM-110-02-S-D-A-K [mm] "Samtec"
  rect 0.74x2.92 smd paste+0: 1(-5.715,-1.715) 2(-5.715,1.715) 3(-4.445,-1.715) 4(-4.445,1.715) 5(-3.175,-1.715) 6(-3.175,1.715) 7(-1.905,-1.715) 8(-1.905,1.715) 9(-0.635,-1.715) 10(-0.635,1.715) 11(0.635,-1.715) 12(0.635,1.715) 13(1.905,-1.715) 14(1.905,1.715) 15(3.175,-1.715) 16(3.175,1.715) 17(4.445,-1.715) 18(4.445,1.715) 19(5.715,-1.715) 20(5.715,1.715)
  round 1.45 hole 1.45 unplated paste+0: ""(-7.305,0) ""(7.305,0)
  silkscreen extent -7.94,-3.51 7.94,2.86, body extent -7.95,-2.98 7.93,2.99, height 5.85
SIL0008A [mm] "POS, 8-Leads, Body 2.5x3.0mm, Pitch 0.65mm, NSC Recommended"
  rect 0.6x0.3 smd mask+0.07: 1(-0.95,0.975) 2(-0.95,0.325) 3(-0.95,-0.325) 4(-0.95,-0.975) 5(0.95,-0.975) 6(0.95,-0.325) 7(0.95,0.325) 8(0.95,0.975)
  rect 0.6x2.25 smd paste-0.3 mask+0.07: 9(0,0)
  silkscreen extent -1.45,-1.7 1.45,1.7, body extent -1.3,-1.5 1.3,1.5, height 1.43
SMA [mm] "Molded Diode, 2-Leads, Body 4.3x2.6mm, IPC Medium Density, based on OnSemi component dimensions and land pattern"
  rect 2x2 smd: 1(-2,0) 2(2,0)
  silkscreen extent -3.66,-1.57 2.79,1.57, body extent -2.6,-1.3 2.6,1.3, height 2.42
SOIC-8 [mm] "duplicate of SO-8.  SOIC, 8-Leads, Body 5.0x4.0mm (max), Pitch 1.27mm, IPC Medium Density"
  oval 2.2x0.6 smd: 1(-2.4,1.905) 2(-2.4,0.635) 3(-2.4,-0.635) 4(-2.4,-1.905) 5(2.4,-1.905) 6(2.4,-0.635) 7(2.4,0.635) 8(2.4,1.905)
  silkscreen extent -0.9,-2.5 0.9,2.5, body extent -3,-2.45 3,2.45, height 1.63
SOT-23-6 [mm] "SOT23, 6-Leads, Body 3.0x1.7mm, Pitch 0.95mm, Lead Span 2.9mm, IPC Medium Density"
  rect 1.1x0.65 smd: 1(-1.2,0.95) 2(-1.2,0) 3(-1.2,-0.95) 4(1.2,-0.95) 5(1.2,0) 6(1.2,0.95)
  silkscreen extent -0.25,-1.55 0.25,1.55, body extent -1.5,-1.5 1.5,1.5, height 1.3
SW_B3U-1000P [mm] "OMRON"
  rect 0.8x1.7 smd: 1(-1.7,0) 2(1.7,0)
  silkscreen extent -1.5,-1.25 1.5,1.25, body extent -1.5,-1.25 1.5,1.25, height 1.75
TDK_ACM2012H-900-2P-T00 [mm] "SMD, 4-Leads, Body 2x1.2mm"
  rect 0.75x0.4 smd: 1(-0.925,0.4) 2(-0.925,-0.4) 3(0.925,-0.4) 4(0.925,0.4)
  silkscreen extent -0.25,-0.7 0.25,0.7, body extent -1.1,-0.7 1.1,0.7, height 1.3
TI_Stacked_Overlay_Small [mil]
  silkscreen extent -418,-98 418,98
VLCF5020 [mm] "TDK"
  rect 2.1x3 smd: 1(-1.725,0) 2(1.725,0)
  TopLayer - S1 (.GTL) region: 0.675,2.4 1.875,2.4 2.775,1.5 2.775,1.35 0.675,1.35
  TopLayer - S1 (.GTL) region: 0.675,-2.45 1.875,-2.45 2.775,-1.55 2.775,-1.4 0.675,-1.4
  TopLayer - S1 (.GTL) region: -0.675,-2.45 -1.875,-2.45 -2.775,-1.55 -2.775,-1.4 -0.675,-1.4
  TopLayer - S1 (.GTL) region: -0.675,2.45 -1.875,2.45 -2.775,1.55 -2.775,1.4 -0.675,1.4
  body extent -2.6,-2.6 2.6,2.6, height 2
XTAL_ABM3 [mm] "Abracon recommended land pattern 12.28.10"
  rect 1.9x2.4 smd: 1(-2.05,0) 2(2.05,0)
  silkscreen extent -2.67,-1.78 2.67,1.78, body extent -2.6,-1.7 2.6,1.7, height 1.3
XTAL_MC-306 [mm] "SEIKO-EPSON"
  rect 1.9x1.3 smd: 1(-1.6,2.75) 2(-1.6,-2.75) 3(1.6,-2.75) 4(1.6,2.75)
  silkscreen extent -1.6,-4 1.6,4, body extent -1.6,-4 1.6,4, height 2.55
ZCZ0324A [mil] "BGA, 324-Balls, Body 15x15mm, Pitch 0.8mm"
  round 14 smd: A1(-267.72,267.72) A2(-236.22,267.72) A3(-204.72,267.72) A4(-173.23,267.72) A5(-141.73,267.72) A6(-110.24,267.72) A7(-78.74,267.72) A8(-47.24,267.72) A9(-15.75,267.72) A10(15.75,267.72) A11(47.24,267.72) A12(78.74,267.72) A13(110.24,267.72) A14(141.73,267.72) A15(173.23,267.72) A16(204.72,267.72) A17(236.22,267.72) A18(267.72,267.72) B1(-267.72,236.22) B2(-236.22,236.22) B3(-204.72,236.22) B4(-173.23,236.22) B5(-141.73,236.22) B6(-110.24,236.22) B7(-78.74,236.22) B8(-47.24,236.22) B9(-15.75,236.22) B10(15.75,236.22) B11(47.24,236.22) B12(78.74,236.22) B13(110.24,236.22) B14(141.73,236.22) B15(173.23,236.22) B16(204.72,236.22) B17(236.22,236.22) B18(267.72,236.22) C1(-267.72,204.72) C2(-236.22,204.72) C3(-204.72,204.72) C4(-173.23,204.72) C5(-141.73,204.72) C6(-110.24,204.72) C7(-78.74,204.72) C8(-47.24,204.72) C9(-15.75,204.72) C10(15.75,204.72) C11(47.24,204.72) C12(78.74,204.72) C13(110.24,204.72) C14(141.73,204.72) C15(173.23,204.72) C16(204.72,204.72) C17(236.22,204.72) C18(267.72,204.72) D1(-267.72,173.23) D2(-236.22,173.23) D3(-204.72,173.23) D4(-173.23,173.23) D5(-141.73,173.23) D6(-110.24,173.23) D7(-78.74,173.23) D8(-47.24,173.23) D9(-15.75,173.23) D10(15.75,173.23) D11(47.24,173.23) D12(78.74,173.23) D13(110.24,173.23) D14(141.73,173.23) D15(173.23,173.23) D16(204.72,173.23) D17(236.22,173.23) D18(267.72,173.23) E1(-267.72,141.73) E2(-236.22,141.73) E3(-204.72,141.73) E4(-173.23,141.73) E5(-141.73,141.73) E6(-110.24,141.73) E7(-78.74,141.73) E8(-47.24,141.73) E9(-15.75,141.73) E10(15.75,141.73) E11(47.24,141.73) E12(78.74,141.73) E13(110.24,141.73) E14(141.73,141.73) E15(173.23,141.73) E16(204.72,141.73) E17(236.22,141.73) E18(267.72,141.73) F1(-267.72,110.24) F2(-236.22,110.24) F3(-204.72,110.24) F4(-173.23,110.24) F5(-141.73,110.24) F6(-110.24,110.24) F7(-78.74,110.24) F8(-47.24,110.24) F9(-15.75,110.24) F10(15.75,110.24) F11(47.24,110.24) F12(78.74,110.24) F13(110.24,110.24) F14(141.73,110.24) F15(173.23,110.24) F16(204.72,110.24) F17(236.22,110.24) F18(267.72,110.24) G1(-267.72,78.74) G2(-236.22,78.74) G3(-204.72,78.74) G4(-173.23,78.74) G5(-141.73,78.74) G6(-110.24,78.74) G7(-78.74,78.74) G8(-47.24,78.74) G9(-15.75,78.74) G10(15.75,78.74) G11(47.24,78.74) G12(78.74,78.74) G13(110.24,78.74) G14(141.73,78.74) G15(173.23,78.74) G16(204.72,78.74) G17(236.22,78.74) G18(267.72,78.74) H1(-267.72,47.24) H2(-236.22,47.24) H3(-204.72,47.24) H4(-173.23,47.24) H5(-141.73,47.24) H6(-110.24,47.24) H7(-78.74,47.24) H8(-47.24,47.24) H9(-15.75,47.24) H10(15.75,47.24) H11(47.24,47.24) H12(78.74,47.24) H13(110.24,47.24) H14(141.73,47.24) H15(173.23,47.24) H16(204.72,47.24) H17(236.22,47.24) H18(267.72,47.24) J1(-267.72,15.75) J2(-236.22,15.75) J3(-204.72,15.75) J4(-173.23,15.75) J5(-141.73,15.75) J6(-110.24,15.75) J7(-78.74,15.75) J8(-47.24,15.75) J9(-15.75,15.75) J10(15.75,15.75) J11(47.24,15.75) J12(78.74,15.75) J13(110.24,15.75) J14(141.73,15.75) J15(173.23,15.75) J16(204.72,15.75) J17(236.22,15.75) J18(267.72,15.75) K1(-267.72,-15.75) K2(-236.22,-15.75) K3(-204.72,-15.75) K4(-173.23,-15.75) K5(-141.73,-15.75) K6(-110.24,-15.75) K7(-78.74,-15.75) K8(-47.24,-15.75) K9(-15.75,-15.75) K10(15.75,-15.75) K11(47.24,-15.75) K12(78.74,-15.75) K13(110.24,-15.75) K14(141.73,-15.75) K15(173.23,-15.75) K16(204.72,-15.75) K17(236.22,-15.75) K18(267.72,-15.75) L1(-267.72,-47.24) L2(-236.22,-47.24) L3(-204.72,-47.24) L4(-173.23,-47.24) L5(-141.73,-47.24) L6(-110.24,-47.24) L7(-78.74,-47.24) L8(-47.24,-47.24) L9(-15.75,-47.24) L10(15.75,-47.24) L11(47.24,-47.24) L12(78.74,-47.24) L13(110.24,-47.24) L14(141.73,-47.24) L15(173.23,-47.24) L16(204.72,-47.24) L17(236.22,-47.24) L18(267.72,-47.24) M1(-267.72,-78.74) M2(-236.22,-78.74) M3(-204.72,-78.74) M4(-173.23,-78.74) M5(-141.73,-78.74) M6(-110.24,-78.74) M7(-78.74,-78.74) M8(-47.24,-78.74) M9(-15.75,-78.74) M10(15.75,-78.74) M11(47.24,-78.74) M12(78.74,-78.74) M13(110.24,-78.74) M14(141.73,-78.74) M15(173.23,-78.74) M16(204.72,-78.74) M17(236.22,-78.74) M18(267.72,-78.74) N1(-267.72,-110.24) N2(-236.22,-110.24) N3(-204.72,-110.24) N4(-173.23,-110.24) N5(-141.73,-110.24) N6(-110.24,-110.24) N7(-78.74,-110.24) N8(-47.24,-110.24) N9(-15.75,-110.24) N10(15.75,-110.24) N11(47.24,-110.24) N12(78.74,-110.24) N13(110.24,-110.24) N14(141.73,-110.24) N15(173.23,-110.24) N16(204.72,-110.24) N17(236.22,-110.24) N18(267.72,-110.24) P1(-267.72,-141.73) P2(-236.22,-141.73) P3(-204.72,-141.73) P4(-173.23,-141.73) P5(-141.73,-141.73) P6(-110.24,-141.73) P7(-78.74,-141.73) P8(-47.24,-141.73) P9(-15.75,-141.73) P10(15.75,-141.73) P11(47.24,-141.73) P12(78.74,-141.73) P13(110.24,-141.73) P14(141.73,-141.73) P15(173.23,-141.73) P16(204.72,-141.73) P17(236.22,-141.73) P18(267.72,-141.73) R1(-267.72,-173.23) R2(-236.22,-173.23) R3(-204.72,-173.23) R4(-173.23,-173.23) R5(-141.73,-173.23) R6(-110.24,-173.23) R7(-78.74,-173.23) R8(-47.24,-173.23) R9(-15.75,-173.23) R10(15.75,-173.23) R11(47.24,-173.23) R12(78.74,-173.23) R13(110.24,-173.23) R14(141.73,-173.23) R15(173.23,-173.23) R16(204.72,-173.23) R17(236.22,-173.23) R18(267.72,-173.23) T1(-267.72,-204.72) T2(-236.22,-204.72) T3(-204.72,-204.72) T4(-173.23,-204.72) T5(-141.73,-204.72) T6(-110.24,-204.72) T7(-78.74,-204.72) T8(-47.24,-204.72) T9(-15.75,-204.72) T10(15.75,-204.72) T11(47.24,-204.72) T12(78.74,-204.72) T13(110.24,-204.72) T14(141.73,-204.72) T15(173.23,-204.72) T16(204.72,-204.72) T17(236.22,-204.72) T18(267.72,-204.72) U1(-267.72,-236.22) U2(-236.22,-236.22) U3(-204.72,-236.22) U4(-173.23,-236.22) U5(-141.73,-236.22) U6(-110.24,-236.22) U7(-78.74,-236.22) U8(-47.24,-236.22) U9(-15.75,-236.22) U10(15.75,-236.22) U11(47.24,-236.22) U12(78.74,-236.22) U13(110.24,-236.22) U14(141.73,-236.22) U15(173.23,-236.22) U16(204.72,-236.22) U17(236.22,-236.22) U18(267.72,-236.22) V1(-267.72,-267.72) V2(-236.22,-267.72) V3(-204.72,-267.72) V4(-173.23,-267.72) V5(-141.73,-267.72) V6(-110.24,-267.72) V7(-78.74,-267.72) V8(-47.24,-267.72) V9(-15.75,-267.72) V10(15.75,-267.72) V11(47.24,-267.72) V12(78.74,-267.72) V13(110.24,-267.72) V14(141.73,-267.72) V15(173.23,-267.72) V16(204.72,-267.72) V17(236.22,-267.72) V18(267.72,-267.72)
  silkscreen extent -326,-295 295,295, body extent -297,-297 297,297, height 56

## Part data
C1 C2 C3 C17 C18 C36 C40 C45 C63 C67 C72 C80 C81 C86 C88 C89 C90 C104 C107 C110 C113 C116 C126 C131 C148 C149 C170 C171 C185 C202 C211 C212 C225 C226 C227 C231 C232: "CAP, CERM, 10 µF, 25 V, +/- 20%, X5R, 0603"
C4: "CAP, CERM, 0.47 µF, 100 V, +/- 10%, X7R, 0805"
C5: "CAP, CERM, 1 µF, 100 V, +/- 10%, X7S, 0805"
C6 C8: "CAP, CERM, 0.1 µF, 100 V, +/- 10%, X7R, 0603"
C7 C9: "CAP, CERM, 1000 pF, 100 V, +/- 10%, X7R, 0603"
C10: "CAP, CERM, 1 µF, 25 V, +/- 10%, X7R, 0603"
C11: "CAP, CERM, 10 µF, 100 V, +/- 20%, X7S, 2220"
C12: "CAP, CERM, 0.022 µF, 50 V, +/- 10%, X7R, 0402"
C13 C82 C83 C84 C85 C87 C233 C234 C251: "CAP, CERM, 4.7 µF, 16 V, +/- 10%, X5R, 0603"
C14: "CAP, CERM, 8.2 pF, 25 V, +/- 5%, C0G/NP0, 0402"
C15 C22 C27 C28 C29 C30 C55 C56 C57 C58 C206: "CAP, CERM, 0.1 µF, 16 V, +/- 10%, X7R, 0402"
C16 C100 C101: "CAP, CERM, 1 µF, 10 V, +/- 10%, X7R, 0603"
C21: "CAP, CERM, 470 pF, 50 V, +/- 10%, X7R, 0402"
C23 C91 C92 C93 C94 C95 C96 C97 C98 C201 C260: "CAP, CERM, 2.2 µF, 10 V, +/- 10%, X7R, 0603"
C24 C199 C203 C204 C207 C209 C236 C237 C239 C242 C244 C245 C246 C247 C248 C249 C250: "CAP, CERM, 0.1 µF, 10 V, +/- 10%, X7R, 0402"
C25 C26 C38 C39 C42 C43 C44 C47 C48 C49 C50 C53 C54 C65 C66 C69 C70 C71 C74 C75 C76 C77 C197 C210 C253 C257: "CAP, CERM, 1000 pF, 16 V, +/- 10%, X7R, 0201"
C31 C32 C60 C61 C192 C193 C240 C241 C258 C259: "CAP, CERM, 27 pF, 50 V, +/- 5%, C0G/NP0, 0402"
C33 C59: "CAP, CERM, 1000 pF, 2000 V, +/- 10%, X7R, 1206_190"
C34 C62: "CAP, CERM, 1000 pF, 2000 V, +/- 10%, X7R, 1812"
C35 C37 C41 C46 C64 C68 C73 C102 C103 C105 C106 C108 C109 C111 C112 C114 C115 C117 C118 C119 C120 C121 C122 C123 C124 C125 C127 C128 C129 C130 C132 C133 C134 C135 C136 C137 C138 C142 C143 C144 C146 C147 C172 C173 C174 C175 C176 C177 C178 C179 C180 C181 C182 C183 C184 C186 C187 C188 C189 C190 C191 C195 C196 C200 C205 C235 C238 C243 C254 C256: "CAP, CERM, 0.01 µF, 10 V, +/- 10%, X7R, 0201"
C99: library part GRM155R71a104ka01D, "CAP, CERM, 0.1 µF, 10 V, +/- 10%, X7R, 0402"
C139 C140 C141 C145: "CAP, CERM, 1 µF, 10 V, +/- 20%, X5R, 0201"
C150 C151 C152 C153 C154 C155 C156 C157 C158 C159 C160 C161 C162 C163 C164 C165 C166 C167 C168 C169 C208 C213 C214 C215 C216 C217 C218 C219 C220 C221 C222 C223 C224 C228 C229 C230 C252 C255: "CAP, CERM, 0.1 µF, 10 V, +/- 10%, X5R, 0201"
C194 C198: "CAP, CERM, 18 pF, 50 V, +/- 5%, C0G/NP0, 0402"
C261 C262 C263 C264 C265 C266 C267 C268 C271 C272 C273 C274 C275 C276 C277 C278: "CAP, CERM, 4.7 pF, 50 V, +/- 5%, C0G/NP0, 0201"
D1: "Diode, Schottky, 60V, 1A, SMA"
D2 D3 D6 D11 D14: "LED, Green, SMD"
D4 D9: "LED, Yellow, SMD"
D5 D10: "LED, Red, SMD"
D7 D12: "LED, Orange, SMD"
D8 D13: "Diode, TVS, Bi, 5 V, 300 W, SOT-23-6"
FID1 FID2 FID3 FID4 FID5 FID6: "Fiducial mark.  There is nothing to buy or mount."
H1 H2 H3 H4: "Machine Screw, Round, #4-40 x 1/4, Nylon, Philips panhead"
H5 H6 H7 H8: "Standoff, Hex, 0.5\"L #4-40 Nylon"
J1 J3: "Header, 100mil, 2x1, Tin, TH"
J2: "Power Jack, mini, 2.1mm OD, R/A, TH"
J4 J5: "Modular Jack(Shielded), Gold, R/A, TH"
J6: "Conncetor, micro SD Card, 1.1 mm, R/A, SMT"
J7: "Receptacle, 0.65 mm, 5x1, Gold, R/A, SMT"
J8: "CONN SHRD HDR HDR 20 POS 1.27MM SLDR ST SMD"
L1: "Inductor, Shielded Drum Core, Ferrite, 1 µH, 1.5 A, 0.085 ohm, SMD"
L2: "Inductor, Shielded Drum Core, Ferrite, 15 µH, 3.5 A, 0.03 ohm, SMD"
L3 L4 L5: "Inductor, Shielded, Ferrite, 2.2 µH, 2.62 A, 0.043 ohm, SMD"
L6 L7 L9 L10 L11 L12: "Ferrite Bead, 150 ohm @ 100 MHz, 0.8 A, 0805"
L8: "Common Mode Filter, 90 Ohm, 6 GHz, SMD"
L13 L14: "Ferrite Bead, 120 ohm @ 100 MHz, 0.4 A, 0402"
Logo1: library part TI_Logo, "Texas Instrument Corporate Signature"
Logo2: library part Pb-Free
R1: "RES, 10 ohm, 5%, 0.25W, 0603"
R2: "RES, 453 k, 1%, 0.063 W, 0402"
R3: "RES, 750, 5%, 0.063 W, 0402"
R4 R119: "RES, 100 k, 1%, 0.063 W, 0402"
R5: "RES, 80.6 k, 1%, 0.063 W, 0402"
R6 R36 R65 R168: "RES, 1.00 M, 1%, 0.063 W, 0402"
R7: "RES, 249 k, 1%, 0.063 W, 0402"
R8 R9 R10 R12 R15 R71 R139 R140 R141 R142 R143 R144 R145 R147 R159 R160 R161 R162 R163 R164: "RES, 0, 5%, 0.1 W, 0603"
R13: "RES, 360, 5%, 0.063 W, 0402"
R14: "RES, 150 k, 1%, 0.063 W, 0402"
R16: "RES, 110 k, 1%, 0.063 W, 0402"
R19 R43 R44 R46 R47 R50 R51 R63 R170 R171 R172 R173 R174 R175: "RES, 0, 5%, 0.063 W, 0402"
R20: "RES, 0, 5%, 0.0625 W, Resistor Array - 8x1"
R21 R38 R41 R67 R68 R136 R138 R158: "RES, 10.0 k, 1%, 0.063 W, 0402"
R22 R24 R32 R37 R42 R48 R58 R64: "RES, 75.0, 1%, 0.1 W, 0603"
R23 R29 R45 R55 R146 R151 R152 R153 R165 R166: "RES, 4.7 k, 5%, 0.063 W, 0402"
R25 R26 R27 R33 R52 R53 R54 R60 R66: "RES, 560, 5%, 0.063 W, 0402"
R28 R30 R49 R56 R59: "RES, 11.0 k, 1%, 0.063 W, 0402"
R31 R34 R57 R61 R62: "RES, 2.49 k, 1%, 0.063 W, 0402"
R35 R72 R73 R74 R75 R77 R78 R79 R80 R81 R82: "RES, 22, 5%, 0.063 W, 0402"
R69: "RES, 22, 5%, 0.0625 W, Resistor Array - 8x1"
R70 R83 R84 R85 R86 R87 R88 R89 R90 R91 R92 R93 R94 R95 R96 R97 R98 R120 R121 R122 R123 R124 R125 R131 R135 R137 R148 R149 R150: "RES, 10 k, 5%, 0.063 W, 0402"
R76 R117 R118 R154 R156: "RES, 2.2 k, 5%, 0.063 W, 0402"
R99 R126 R127 R176: "RES, 49.9, 1%, 0.063 W, 0402"
R100 R129 R169 R177 R178 R179 R180 R181: "RES, 1.00 k, 1%, 0.063 W, 0402"
R101 R102 R103 R104 R105 R106 R107 R108 R109 R110 R111 R112 R113 R114 R115 R116: "RES, 100 k, 5%, 0.063 W, 0402"
R128 R130 R133: "RES, 47, 5%, 0.0625 W, Resistor Array - 8x1"
R132: "RES, 240, 5%, 0.063 W, 0402"
R134: "RES, 47, 5%, 0.063 W, 0402"
R155: "RES, 4.75 k, 1%, 0.063 W, 0402"
R157: "RES, 12.1 k, 1%, 0.063 W, 0402"
R167 R182 R183: "RES, 36, 5%, 0.063 W, 0402"
S1: "SWITCH TACTILE SPST-NO 0.05A 12V"
T1 T2: "Transformer, 325 uH, SMT"
TP1 TP2 TP3 TP4: library part SMOX/060/B1LP.R3K, "Test Point, Silver, SMD"
U1: "3.5V to 60V 2A Synchronous Step-Down Voltage Regulator, PWP0016A"
U2: "Single Output LDO, 1 A, Fixed 3.3 V Output, 2.2 to 5.5 V Input, with Reverse Current Protection, 6-pin SOT-223 (DCQ), -40 to 125 degC, Green (RoHS & no Sb/Br)"
U3: "1A SIMPLE SWITCHER® Nano Module with 5.5V Maximum Input Voltage, SIL0008A"
U5: "350mA, Ultra-Low VIN, RF Low-Dropout Linear Regulator with Bias Pin, DRV0006A"
U6 U12: "Robust, Low Power 10/100/1000 Ethernet Physical Layer Transceiver, PAP0064M"
U7 U8 U9 U10: "1, 4, 6 CHANNEL PROTECTION SOLUTION FOR SUPER-SPEED (UP TO 6 GBPS) INTERFACE, DQA0010A"
U11: "Single 2-Input Positive-AND Gate, DCK0005A"
U13: "Integrated Power-Management Unit Top Specification, RSL0048A"
U14: "Single Output High PSRR LDO, 150 mA, Fixed 1.8 V Output, 2.5 to 6.5 V Input, with Low IQ, 6-pin WSON (DSE), -40 to 125 degC, Green (RoHS & no Sb/Br)"
U15: "Sitara Processors, ZCZ0324A"
U16: "LOW-POWER DUAL 2-INPUT POSITIVE-AND GATE, DCU0008A"
U17: "2GBIT DDR3 SDRAM, 96-FBGA"
U18: "Low-Capacitance + / - 15 kV ESD Protection Array for High-Speed Data Interfaces, 6 Channels, -40 to +85 degC, 10-pin UQFN (RSE), Green (RoHS & no Sb/Br)"
U19: "256 kb I2C CMOS Serial EEPROM, SOIC-8"
U20: "Single Output LDO, 3 A, 2.375 to 3.5 V Input, with DDR Termination, 10-pin SON (DRC), -40 to 85 degC, Green (RoHS & no Sb/Br)"
U21: "USB ESD Solution with Power Clamp, 4 Channels, -40 to +85 degC, 6-pin SON (DRY), Green (RoHS & no Sb/Br)"
U22: "Dual High Speed USB To Multipurpose UART/FIFO IC, LQFP-64"
U23: "2K Microwire Compatible Serial EEPROM, SOT-23-6"
U24: "Single Inverter Buffer/Driver With Open-Drain Output, DCK0005A"
U25: "Programmable 1-PLL VCXO Clock Synthesizer With 1.8-V, 2.5-V, and 3.3-V Outputs, PW0014A"
Y1 Y2 Y6: "Crystal, 25 MHz, 18 pF, SMD"
Y3: "Crystal, 24 MHz, 18 pF, SMD"
Y4: "Crystal, 32.768kHz, 12.5pF, SMD"
Y5: "Crystal, 12 MHz, 18 pF, SMD"

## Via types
v1: diameter 19.68, hole 7.87, TopLayer - S1 (.GTL) to BottomLayer - S8 (.GBL), 600 vias
v2: diameter 17.72, hole 7.87, TopLayer - S1 (.GTL) to BottomLayer - S8 (.GBL), 408 vias
v3: diameter 27.56, hole 11.81, TopLayer - S1 (.GTL) to BottomLayer - S8 (.GBL), 31 vias
v4: diameter 20, hole 7.87, TopLayer - S1 (.GTL) to BottomLayer - S8 (.GBL), tented both sides, 11 vias
v5: diameter 15.75, hole 7.87, TopLayer - S1 (.GTL) to BottomLayer - S8 (.GBL), 9 vias
v6: diameter 20, hole 7.87, TopLayer - S1 (.GTL) to BottomLayer - S8 (.GBL), 5 vias
v7: diameter 15, hole 7.87, TopLayer - S1 (.GTL) to BottomLayer - S8 (.GBL), 2 vias
v8: diameter 18, hole 7.87, TopLayer - S1 (.GTL) to BottomLayer - S8 (.GBL), 1 vias

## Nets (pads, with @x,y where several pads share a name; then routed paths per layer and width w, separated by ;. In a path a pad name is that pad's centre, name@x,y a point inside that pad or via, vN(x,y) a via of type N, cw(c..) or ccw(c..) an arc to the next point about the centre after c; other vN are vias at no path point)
CDC_CLK1: R171.2 R182.2 | length 1327.2
  TopLayer - S1 (.GTL) w5.91: v1(2543,2068) 2552.5,2058.5 R171.2@2552.5,2031.12
  MidLayer2 - S3 (.G2) w4.68: v1(2543,2068) 2543,2024.5 2665,1902.5 2665,1527.5 2722.5,1470 2722.5,1104 v1(2618.5,1000)
  BottomLayer - S8 (.GBL) w4.92: v1(2618.5,1000) 2641,977.5 2670.41,977.5 2677.17,984.25 2695.63,984.25 R182.2@2703.88,992.5
CDC_CLK2: R173.2 R183.2 | length 208.5
  TopLayer - S1 (.GTL) w6: R173.2@2555,961.12 v1(2555,1000)
  BottomLayer - S8 (.GBL) w4.92: v1(2555,1000) 2605,950 R183.2@2703.88,950
CDC_CLK3: R167.2 R175.2 R176.2 | length 1314.4
  BottomLayer - S8 (.GBL) w4.92: R175.2@1538.62,692.5 R176.2@1538.62,650 1877.5,650 2135,907.5 R167.2@2703.88,907.5
CDC_S0: R178.1 R181.2 U25.2 | length 732.4
  MidLayer5 - S6 (.G5) w4.92: v1(2689.35,1161.65) 2813.82,1037.18 2981.32,1037.18 v1(2995.32,1051.18)
  BottomLayer - S8 (.GBL) w4.92: R181.2@2381.12,1140 R178.1@2428.88,1140 2430,1140 2451.65,1161.65 v1(2689.35,1161.65) ; v1(2995.32,1051.18) U25.2@3047.2,1051.18
CDC_S1: R177.1 R180.2 TP3.1 U25.13 | length 491.1
  BottomLayer - S8 (.GBL) w4.92: R180.2@2381.12,1097.5 R177.1@2428.88,1097.5 2429.5,1097.5 2451,1119 2523,1119 2538,1134 2648.5,1134 TP3.1@2700,1082.5 2731.32,1051.18 U25.13@2822.8,1051.18
CDC_S2: R169.1 R179.2 TP4.1 U25.12 | length 494.9
  BottomLayer - S8 (.GBL) w4.92: R179.2@2381.12,1055 R169.1@2428.88,1055 2430,1055 2452,1033 2540.5,1033 TP4.1@2590,1082.5 2639.5,1033 2772.59,1033 2780,1025.59 U25.12@2822.8,1025.59
DDR_A0: R128.1 U15.F3 U17.N3 | length 1263.2
  TopLayer - S1 (.GTL) w4.92: v2(552.59,1271.73) U17.N3@602.99,1271.73 ; v2(1214.53,1255.98) v2(1214.53,1255.98) U15.F3@1230.28,1240.26
  MidLayer5 - S6 (.G5) w4.68: v2(552.59,1271.73) 552.59,1231.59 557.18,1227 586.69,1227 590.69,1231 590.69,1247.14 595.08,1251.53 601.3,1251.53 605.69,1247.14 605.69,1231.78 613.83,1223.64 732.67,1223.64 743.13,1213.18 743.13,1195.71 748.13,1190.71 757.89,1190.71 762.89,1195.71 762.89,1218 768.89,1224 776.22,1224 780.61,1219.61 780.61,1195.62 785,1191.23 793.22,1191.23 797.61,1195.62 797.61,1219.61 802,1224 809.22,1224 813.61,1219.61 813.61,1195.62 818,1191.23 827.22,1191.23 831.61,1195.62 831.61,1219.61 836,1224 843,1224 849.71,1217.29 849.71,1204.29 855,1199 1066.69,1199 1077,1188.69 1133.88,1188.69 1145.33,1177.24 1158.17,1177.24 1167.5,1186.57 1167.5,1199.43 1177.07,1209 1189.43,1209 1198.5,1218.07 1198.5,1230.43 1214.5,1246.43 v2(1214.53,1255.98)
  BottomLayer - S8 (.GBL) w4.92: R128.1@533.9,1448.5 533.9,1430.98 540.47,1424.41 555.08,1424.41 558.2,1421.29 558.2,1404.02 544.5,1390.32 544.5,1352.02 547.39,1349.11 553.5,1343 553.5,1272.64 v2(552.59,1271.73)
DDR_A1: R128.3 U15.H1 U17.P7 | length 1261.8
  TopLayer - S1 (.GTL) w4.92: U17.P7@477.01,1303.23 487.1,1313.32 504.81,1313.32 514.79,1323.3 545.3,1323.3 549.82,1318.78 549.82,1310.5 544.32,1305 v2(529,1305) ; v2(1151.54,1192.99) v2(1151.54,1192.99) U15.H1@1167.28,1177.26
  MidLayer5 - S6 (.G5) w4.68: v2(529,1305) 515.13,1305 509.52,1310.61 509.52,1317.28 516.24,1324 578.95,1324 595,1307.95 595,1278 601.52,1271.48 643.8,1271.48 664,1271.49 676.11,1283.6 713.02,1283.6 732.3,1264.32 764.02,1264.32 789.34,1239 860.32,1239 864.71,1234.61 864.71,1219.39 869.1,1215 875.32,1215 879.71,1219.39 879.71,1234.61 884.1,1239 890.32,1239 894.71,1234.61 894.71,1219.39 899.1,1215 905.32,1215 909.71,1219.39 909.71,1234.61 914.1,1239 920.32,1239 924.71,1234.61 924.71,1219.39 929.1,1215 935.32,1215 939.71,1219.39 939.71,1234.61 944.1,1239 950.32,1239 954.71,1234.61 954.71,1219.39 959.1,1215 965.32,1215 969.71,1219.39 969.71,1234.61 974.1,1239 980.32,1239 984.71,1234.61 984.71,1219.39 989.1,1215 995.32,1215 999.71,1219.39 999.71,1234.61 1004.1,1239 1010.32,1239 1014.71,1234.61 1014.71,1219.39 1019.1,1215 1078.07,1215 1083.57,1220.5 1096.43,1220.5 1101.93,1215 1129.5,1215 v2(1151.54,1192.99)
  BottomLayer - S8 (.GBL) w4.92: R128.3@494.53,1448.5 494.53,1404.28 490.62,1400.37 490.62,1385.43 497.43,1378.62 509.43,1378.62 517.57,1370.48 517.57,1326.33 529,1314.9 v2(529,1305)
DDR_A2: R133.7 U15.E4 U17.P3 | length 1280.2
  TopLayer - S1 (.GTL) w4.92: v2(577.79,1303.23) U17.P3@602.99,1303.23 ; v2(1246.02,1287.48) U15.E4@1261.77,1271.75
  MidLayer5 - S6 (.G5) w4.68: v2(577.79,1303.23) 561.79,1287.23 546.16,1287.23 537.09,1278.16 537.09,1263.56 531.31,1257.78 496.9,1257.78 489.87,1250.75 489.87,1243.79 498.35,1235.31 514.83,1235.31 523.36,1226.78 523.63,1226.78 537.42,1212.99 707.41,1212.99 719.97,1200.43 719.97,1188.03 733,1175 1134.84,1175 1141.6,1168.24 1161.9,1168.24 1170.66,1177 1188.93,1177 1199,1187.07 1199,1199.43 1208.57,1209 1220.93,1209 1230,1218.07 1230,1283.15 1234.35,1287.5 v2(1246.02,1287.48)
  BottomLayer - S8 (.GBL) w4.92: v2(577.79,1303.23) 577.79,1287.54 584.52,1280.81 594.01,1280.81 607.04,1293.84 607.04,1306.87 589.05,1324.86 589.05,1421.88 595.79,1428.62 R133.7@595.79,1448.5
DDR_A3: R133.4 U15.C3 U17.N2 | length 1201.6
  TopLayer - S1 (.GTL) w4.92: v2(618.74,1255.98) 618.74,1279.74 626,1287 646.25,1287 651,1282.25 651,1277 645.73,1271.73 U17.N2@634.49,1271.73 ; v2(1214.53,1350.47) U15.C3@1230.28,1334.72
  MidLayer2 - S3 (.G2) w4.68: v2(618.74,1255.98) 618.74,1264.74 624.84,1270.84 643.16,1270.84 657.97,1285.65 670.71,1285.65 675.1,1281.26 675.1,1247.39 679.49,1243 685.71,1243 690.1,1247.39 690.1,1281.26 694.26,1285.42 726.8,1285.42 730.16,1282.06 730.16,1258.83 734.72,1254.27 739.7,1254.27 743.99,1258.56 743.99,1278.68 748.74,1283.43 812.1,1283.43 816.42,1279.11 816.42,1259.39 820.81,1255 827.03,1255 831.42,1259.39 831.42,1279.11 835.81,1283.5 842.03,1283.5 846.42,1279.11 846.42,1259.39 850.81,1255 857.03,1255 861.42,1259.39 861.42,1279.11 865.81,1283.5 950.62,1283.5 977.12,1310 1134,1310 1140.51,1303.49 1189.43,1303.49 1198.5,1312.56 1198.5,1325.42 1198.43,1325.49 1198.43,1334.43 v2(1214.53,1350.47)
  BottomLayer - S8 (.GBL) w4.92: v2(618.74,1255.98) 618.74,1274.55 644.41,1300.22 644.41,1354.39 665.62,1375.6 665.62,1388.34 657.24,1396.72 657.24,1446.1 R133.4@654.84,1448.5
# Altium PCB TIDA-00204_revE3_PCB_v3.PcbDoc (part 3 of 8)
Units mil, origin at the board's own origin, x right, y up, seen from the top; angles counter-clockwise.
Board outline 4600 x 3740 mil, 8 copper layers (TopLayer - S1 (.GTL), MidLayer1 - S2 (.G1), MidLayer2 - S3 (.G2), MidLayer3 - S4 (.G3), MidLayer4 - S5 (.G4), MidLayer5 - S6 (.G5), MidLayer6 - S7 (.G6), BottomLayer - S8 (.GBL)), stack 58.938 mil thick; 537 components, 354 nets, 2015 pads, 1067 vias.

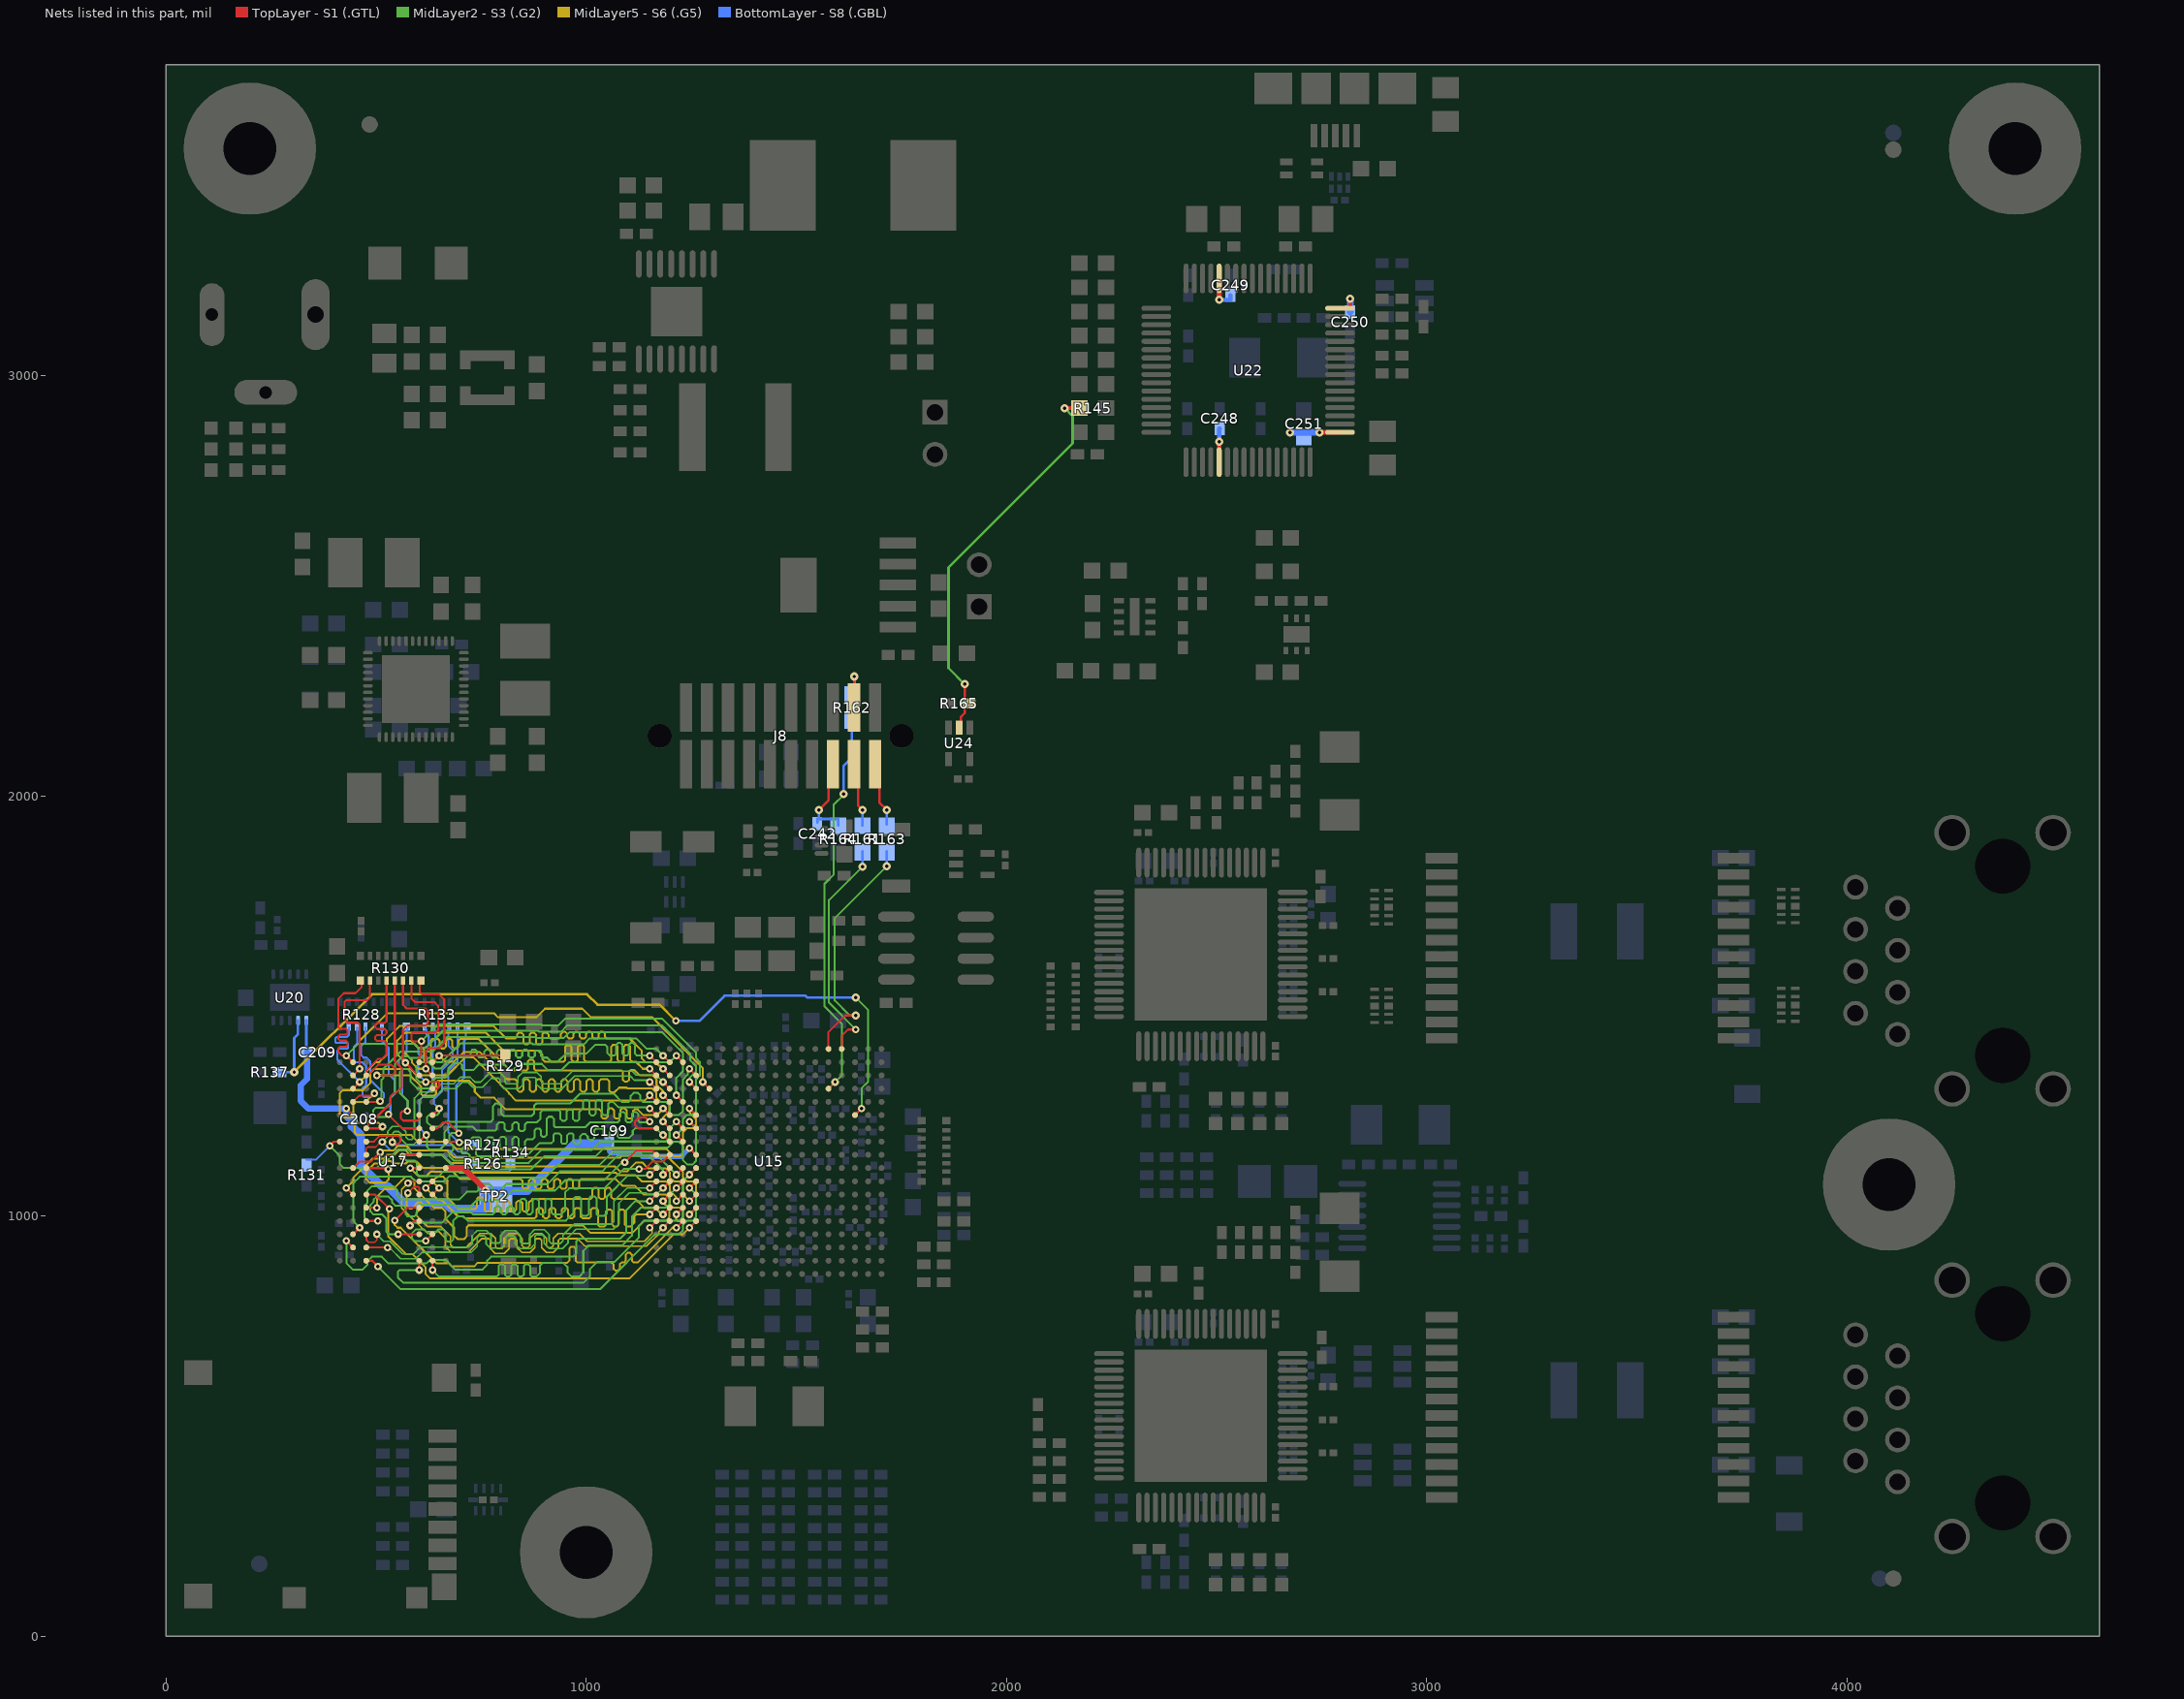
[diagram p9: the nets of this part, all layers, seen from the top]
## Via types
v1: diameter 19.68, hole 7.87, TopLayer - S1 (.GTL) to BottomLayer - S8 (.GBL), 600 vias
v2: diameter 17.72, hole 7.87, TopLayer - S1 (.GTL) to BottomLayer - S8 (.GBL), 408 vias
v3: diameter 27.56, hole 11.81, TopLayer - S1 (.GTL) to BottomLayer - S8 (.GBL), 31 vias
v4: diameter 20, hole 7.87, TopLayer - S1 (.GTL) to BottomLayer - S8 (.GBL), tented both sides, 11 vias
v5: diameter 15.75, hole 7.87, TopLayer - S1 (.GTL) to BottomLayer - S8 (.GBL), 9 vias
v6: diameter 20, hole 7.87, TopLayer - S1 (.GTL) to BottomLayer - S8 (.GBL), 5 vias
v7: diameter 15, hole 7.87, TopLayer - S1 (.GTL) to BottomLayer - S8 (.GBL), 2 vias
v8: diameter 18, hole 7.87, TopLayer - S1 (.GTL) to BottomLayer - S8 (.GBL), 1 vias

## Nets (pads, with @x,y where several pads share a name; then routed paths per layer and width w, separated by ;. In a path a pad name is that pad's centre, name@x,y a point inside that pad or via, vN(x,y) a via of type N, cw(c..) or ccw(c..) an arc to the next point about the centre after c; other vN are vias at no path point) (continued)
DDR_A4: R128.6 U15.C2 U17.P8 | length 1325
  TopLayer - S1 (.GTL) w4.92: U17.P8@445.51,1303.23 v2(461.25,1318.97) ; v2(1183.03,1350.47) U15.C2@1198.78,1334.72
  MidLayer5 - S6 (.G5) w4.68: v2(461.25,1318.97) 476.76,1334.48 476.76,1343.95 499.19,1366.38 508.03,1366.38 526.22,1384.57 526.22,1422.08 556.24,1452.1 780.52,1452.1 810.13,1422.49 831.2,1422.49 835.59,1426.88 835.59,1432.1 839.98,1436.49 846.2,1436.49 850.59,1432.1 850.59,1412.88 854.98,1408.49 861.2,1408.49 865.59,1412.88 865.59,1432.1 869.98,1436.49 876.2,1436.49 880.59,1432.1 880.59,1412.88 884.98,1408.49 891.2,1408.49 895.59,1412.88 895.59,1432.1 899.98,1436.49 906.2,1436.49 910.59,1432.1 910.59,1426.88 914.98,1422.49 935.55,1422.49 939.94,1426.88 939.94,1433.83 944.33,1438.22 950.55,1438.22 954.94,1433.83 954.94,1426.88 959.33,1422.49 965.55,1422.49 969.94,1426.88 969.94,1433.83 974.33,1438.22 980.55,1438.22 984.94,1433.83 984.94,1426.88 989.33,1422.49 995.55,1422.49 999.94,1426.88 999.94,1433.83 1004.33,1438.22 1010.55,1438.22 1014.94,1433.83 1014.94,1426.88 1019.33,1422.49 1025.55,1422.49 1029.94,1426.88 1029.94,1433.83 1034.33,1438.22 1040.55,1438.22 1044.94,1433.83 1044.94,1426.88 1049.33,1422.49 1103.51,1422.49 1132.49,1393.51 1132.49,1374.99 1141,1366.48 1163.84,1366.48 1172.84,1357.48 1176,1357.48 v2(1183.03,1350.47)
  BottomLayer - S8 (.GBL) w4.92: R128.6@435.47,1448.5 435.9,1448.07 435.9,1431.06 430.81,1425.97 406.24,1425.97 403.62,1423.35 403.62,1414.18 405.93,1411.87 431.99,1411.87 433.87,1409.99 433.87,1400.51 431.35,1397.99 412.51,1397.99 407.81,1393.29 407.81,1372.41 v2(461.25,1318.97)
DDR_A5: R133.6 U15.B1 U17.P2 | length 1205.5
  TopLayer - S1 (.GTL) w4.92: v2(618.74,1318.98) 619.76,1320 648,1320 651,1317 651,1308 646.23,1303.23 U17.P2@634.49,1303.23 ; v2(1151.54,1381.97) v2(1151.54,1381.97) U15.B1@1167.28,1366.22
  MidLayer2 - S3 (.G2) w4.68: v2(618.74,1318.98) 604.02,1318.98 596,1327 596,1355 606.97,1365.97 625.17,1365.97 640.14,1351 653.93,1351 681.02,1378.09 720.99,1378.09 725.38,1382.48 725.38,1391.61 729.77,1396 735.99,1396 740.38,1391.61 740.38,1382.48 744.77,1378.09 754.77,1378.09 758.07,1381.39 758.07,1391.61 762.46,1396 768.68,1396 773.07,1391.61 773.07,1381.39 777.46,1377 783.68,1377 788.07,1381.39 788.07,1391.61 792.46,1396 798.68,1396 803.07,1391.61 803.07,1381.39 807.46,1377 813.68,1377 818.07,1381.39 818.07,1391.61 822.46,1396 828.68,1396 833.07,1391.61 833.07,1381.39 837.46,1377 843.68,1377 848.07,1381.39 848.07,1391.61 852.46,1396 858.68,1396 863.07,1391.61 863.07,1381.39 867.46,1377 873.68,1377 878.07,1381.39 878.07,1391.61 879.96,1393.5 891.18,1393.5 893.07,1391.61 893.07,1381.39 897.46,1377 907.46,1377 917.33,1367.13 932.67,1367.13 952.67,1387.13 ; 952.69,1387.14 993.69,1387.14 1000.96,1387.13 1021.83,1408 1045,1408 1050,1403 1050,1389 1057.02,1381.98 1067,1381.98 1071.39,1386.37 1071.39,1407.61 1075.78,1412 1082,1412 1086.39,1407.61 1086.39,1386.37 1090.78,1381.98 1097,1381.98 1101.39,1386.37 1101.39,1407.61 1105.78,1412 1112,1412 1116.39,1407.61 1116.39,1386.37 1120.78,1381.98 v2(1151.54,1381.97)
  BottomLayer - S8 (.GBL) w4.92: R133.6@615.47,1448.5 620.4,1443.57 620.4,1432.83 625.47,1427.76 625.47,1408 618.09,1400.62 603.56,1400.62 600.87,1397.93 600.87,1386.65 606.08,1381.44 616.72,1381.44 621.47,1376.69 621.47,1370.76 616.56,1365.85 606.22,1365.85 600.87,1360.5 600.87,1336.85 v2(618.74,1318.98)
DDR_A6: R130.2 U15.D5 U17.R8 | length 1349.8
  TopLayer - S1 (.GTL) w4.92: U17.R8@445.51,1334.72 v2(461.26,1350.47) 461.26,1455.25 456.41,1460.1 432.93,1460.1 425.53,1467.5 425.53,1509.98 429.48,1513.93 480.06,1513.93 485.79,1519.66 R130.2@485.79,1558.5 ; v2(1277.52,1318.98) U15.D5@1293.27,1303.25
  MidLayer5 - S6 (.G5) w4.68: v2(461.26,1350.47) 461.26,1417.43 525.93,1482.1 781.68,1482.1 790.69,1473.09 881.56,1473.09 901.97,1493.5 990.75,1493.5 1010.83,1473.43 1156.44,1473.43 1277.5,1352.37 v2(1277.52,1318.98)
DDR_A7: R130.8 U15.E2 U17.R2 | length 1355.6
  TopLayer - S1 (.GTL) w4.92: R130.8@603.9,1558.5 603.9,1533.72 610.46,1527.16 650.6,1527.16 662.51,1515.25 662.51,1412.01 650.16,1399.66 626.19,1399.66 618.7,1392.17 v2(618.74,1350.47) v2(618.74,1350.47) U17.R2@634.49,1334.72 ; v2(1183.03,1287.48) U15.E2@1198.78,1271.75
  MidLayer5 - S6 (.G5) w4.68: v2(618.74,1350.47) 600.45,1350.47 585.5,1365.42 585.5,1371.43 565.06,1391.87 565.06,1403.61 565.23,1403.78 565.23,1411.08 571.11,1416.96 583,1416.96 583.35,1417.31 601.16,1399.5 611.03,1399.5 615.05,1395.48 615.05,1371.15 619.74,1366.46 625.96,1366.46 630.35,1370.85 630.35,1417.67 634.01,1421.33 647.07,1421.33 651.46,1416.94 651.46,1403.32 655.85,1398.93 662.07,1398.93 666.46,1403.32 666.46,1416.94 670.85,1421.33 677.07,1421.33 681.46,1416.94 681.46,1403.32 685.85,1398.93 692.07,1398.93 696.46,1403.32 696.46,1416.94 700.85,1421.33 744.77,1421.33 819.8,1346.3 856.95,1346.3 861.34,1350.69 861.34,1367.71 865.73,1372.1 871.95,1372.1 876.34,1367.71 876.34,1350.69 880.73,1346.3 1084.29,1346.3 1087.31,1343.28 1087.31,1324.44 1091.7,1320.05 1097.92,1320.05 1102.31,1324.44 1102.31,1343.28 1106.7,1347.67 1114.7,1347.67 1127.88,1334.49 1157.93,1334.49 1167.5,1324.92 1167.5,1312.56 1183,1297.06 v2(1183.03,1287.48)
DDR_A8: R130.1 U15.D4 U17.T8 | length 1309.9
  TopLayer - S1 (.GTL) w4.92: U17.T8@445.51,1366.22 v2(429.76,1381.97) 419.4,1381.97 410.09,1391.28 410.09,1399.04 414.26,1403.21 428.42,1403.21 432.59,1407.38 432.59,1413.29 428.42,1417.46 414.26,1417.46 410.09,1421.63 410.09,1427.54 414.26,1431.71 428.42,1431.71 432.59,1435.88 432.59,1441.79 428.42,1445.96 414.26,1445.96 410.09,1450.13 410.09,1516.57 423.77,1530.25 451.04,1530.25 466.1,1545.31 R130.1@466.1,1558.5 ; v2(1246.02,1318.98) U15.D4@1261.77,1303.25
  MidLayer2 - S3 (.G2) w4.68: v2(429.76,1381.97) 457.29,1409.5 592.57,1409.5 601.57,1400.5 619.08,1400.5 659.58,1441 886.25,1441 888.75,1438.5 939.89,1438.5 955.42,1454.03 1180.22,1454.03 1247.26,1386.99 1247.26,1371.17 1261.5,1356.93 1261.5,1343.7 1246,1328.2 v2(1246.02,1318.98)
DDR_A9: R130.6 U15.C1 U17.R3 | length 1354.2
  TopLayer - S1 (.GTL) w4.92: R130.6@564.53,1558.5 564.53,1502.45 572.91,1494.07 617.08,1494.07 623.31,1487.84 623.31,1459.26 617.53,1453.48 575.17,1453.48 564.53,1442.84 564.53,1370.47 v2(570,1365) 600.28,1334.72 U17.R3@602.99,1334.72 ; v2(1151.54,1350.47) U15.C1@1167.28,1334.72
  MidLayer5 - S6 (.G5) w4.68: v2(570,1365) 550.23,1384.77 550.23,1417.58 568.98,1436.33 761.69,1436.33 804.53,1393.49 886.3,1393.49 895.62,1384.17 895.62,1373.92 902.41,1367.13 946.18,1367.13 950.57,1371.52 950.57,1402.92 954.66,1407.01 960.88,1407.01 965.57,1402.32 965.57,1371.52 969.96,1367.13 976.18,1367.13 980.57,1371.52 980.57,1402.92 984.66,1407.01 990.88,1407.01 995.57,1402.32 995.57,1371.52 999.96,1367.13 1055.45,1367.13 1059.84,1371.52 1059.84,1403.1 1064.23,1407.49 1070.45,1407.49 1074.84,1403.1 1074.84,1371.52 1079.23,1367.13 1085.45,1367.13 1089.84,1371.52 1089.84,1403.1 1094.23,1407.49 1100.45,1407.49 1104.84,1403.1 1104.84,1371.52 1109.23,1367.13 1118.4,1367.13 1135.05,1350.48 v2(1151.54,1350.47)
DDR_A10: R130.5 U15.F4 U17.L7 | length 1488.7
  TopLayer - S1 (.GTL) w4.92: v2(515.58,1212.66) 511.66,1208.74 U17.L7@477.01,1208.74 477.01,1211.25 523.42,1257.66 524.89,1257.66 534.7,1267.47 534.7,1284.43 542.77,1292.5 547.5,1292.5 561.4,1306.4 561.4,1351.85 557.75,1355.5 557.75,1355.63 544.84,1368.54 R130.5@544.84,1558.5 ; v2(1246.02,1255.98) U15.F4@1261.77,1240.26
  MidLayer5 - S6 (.G5) w4.68: v2(515.58,1212.66) 506.46,1221.78 454.23,1221.78 449.23,1216.78 449.23,1199.45 455.94,1192.74 584.22,1192.74 599.47,1177.49 674.08,1177.49 692.33,1159.24 1192.01,1159.24 1208.88,1142.37 1224.42,1142.37 1230,1147.95 1230,1198.94 1240.06,1209 1252.43,1209 1261.5,1218.07 1261.5,1230.93 1246,1246.43 v2(1246.02,1255.98)
DDR_A11: R130.4 U15.F2 U17.R7 | length 1399.3
  TopLayer - S1 (.GTL) w4.92: v2(502.19,1334.72) 538.97,1334.72 546.5,1342.25 546.5,1350 536.5,1360 505.42,1360 480.14,1334.72 U17.R7@477.01,1334.72 477.01,1346.01 504.84,1373.84 514.42,1373.84 525.16,1384.58 525.16,1412.46 520.99,1416.63 502.49,1416.63 498.32,1420.8 498.32,1426.71 502.49,1430.88 520.99,1430.88 525.16,1435.05 525.16,1440.96 520.99,1445.13 502.49,1445.13 498.32,1449.3 498.32,1455.21 502.49,1459.38 520.99,1459.38 525.16,1463.55 R130.4@525.16,1558.5 ; v2(1183.03,1255.98) v2(1183.03,1255.98) U15.F2@1198.78,1240.26
  MidLayer5 - S6 (.G5) w4.68: v2(502.19,1334.72) 581.07,1334.72 607.21,1308.58 607.21,1290.98 611.53,1286.66 638.53,1286.66 642.84,1290.97 642.84,1317.61 647.23,1322 721.81,1322 735.05,1308.76 735.05,1295.77 749.41,1281.41 781.59,1281.41 809,1254 1031.88,1254 1036.27,1249.61 1036.27,1236.39 1040.66,1232 1046.88,1232 1051.27,1236.39 1051.27,1251.94 1055.66,1256.33 1061.88,1256.33 1066.27,1251.94 1066.27,1236.39 1070.66,1232 1076.88,1232 1081.27,1236.39 1081.27,1251.94 1085.66,1256.33 1091.88,1256.33 1096.27,1251.94 1096.27,1236.39 1100.66,1232 1106.88,1232 1111.27,1236.39 1111.27,1249.61 1115.66,1254 1122.71,1254 1136.71,1240 1168,1240 1183,1255 v2(1183.03,1255.98)
DDR_A12: R128.4 U15.E3 U17.N7 | length 1224.6
  TopLayer - S1 (.GTL) w4.92: U17.N7@477.01,1271.73 508.22,1271.73 v2(509.8,1273.31) ; v2(1214.53,1287.48) v2(1214.53,1287.48) U15.E3@1230.28,1271.75
  MidLayer2 - S3 (.G2) w4.68: v2(509.8,1273.31) 513.5,1277.01 513.5,1324.1 518,1328.6 518,1351 558.5,1391.5 634.6,1391.5 669.1,1426 880.03,1426 882.53,1423.5 946.11,1423.5 960.61,1438 1180.43,1438 1230,1388.43 1230,1344.07 1214.5,1328.57 v2(1214.53,1287.48)
  BottomLayer - S8 (.GBL) w4.92: R128.4@474.84,1448.5 474.84,1413.81 464.41,1403.38 464.41,1383.71 471.03,1377.09 477.54,1377.09 486.81,1367.82 486.81,1323.25 519.08,1290.98 519.08,1282.59 v2(509.8,1273.31)
DDR_A13: R130.7 U15.H3 U17.T3 | length 1291
  TopLayer - S1 (.GTL) w4.92: R130.7@584.21,1558.5 584.21,1517.89 593.03,1509.07 639.14,1509.07 647.76,1500.45 647.76,1442.7 642.04,1436.98 588.38,1436.98 584.21,1432.81 584.21,1419.74 587.95,1416 v2(608,1416) 608,1385.2 602.99,1380.19 U17.T3@602.99,1366.22 ; v2(1214.53,1192.99) U15.H3@1230.28,1177.26
  MidLayer2 - S3 (.G2) w4.68: v2(608,1416) 648,1456 892.47,1456 894.97,1453.5 933.67,1453.5 950.31,1470.14 1180.11,1470.14 1261,1389.25 1261,1376.55 1270.5,1367.05 1270.5,1333.93 1262,1325.43 1262,1250.07 1252.43,1240.5 1240.07,1240.5 1230.37,1230.8 1230.37,1208.87 v2(1214.53,1192.99)
DDR_BA0: R133.3 U15.C4 U17.M2 | length 1206
  TopLayer - S1 (.GTL) w4.92: U17.M2@634.49,1240.24 v2(650.24,1255.99) ; v2(1246.02,1350.47) v2(1246.02,1350.47) U15.C4@1261.77,1334.72
  MidLayer2 - S3 (.G2) w4.68: v2(650.24,1255.99) 650.24,1245.24 645,1240 626,1240 621,1235 621,1224 632,1213 654,1213 665,1224 773,1224 778,1229 778,1261 785,1268 792.64,1268 798,1262.64 798,1244 804,1238 870,1238 876.42,1244.42 876.42,1262.42 882,1268 962,1268 985.13,1291.13 1065.87,1291.13 1086,1271 1100,1271 1105.97,1276.97 1105.97,1285.97 1113,1293 1123,1293 1129,1287 1129,1278 1135.01,1271.99 1189.43,1271.99 1193,1272 1199,1266 1199,1246 1204.5,1240.5 1220.93,1240.5 1230.5,1250.07 1230.5,1325.43 1241.59,1336.52 1241.59,1346.09 v2(1246.02,1350.47)
  BottomLayer - S8 (.GBL) w4.92: v2(650.24,1255.99) 637.23,1269 637.23,1277.39 657.6,1297.76 657.6,1347.92 682.89,1373.21 682.89,1394.64 671.99,1405.54 671.99,1445.96 R133.3@674.53,1448.5
DDR_BA1: R128.5 U15.E1 U17.N8 | length 1325
  TopLayer - S1 (.GTL) w4.92: U17.N8@445.51,1271.73 460.48,1286.7 490.69,1286.7 v2(496.15,1292.16) ; v2(1151.54,1287.48) v2(1151.54,1287.48) U15.E1@1167.28,1271.75
  MidLayer5 - S6 (.G5) w4.68: v2(496.15,1292.16) 475.64,1271.65 453.74,1271.65 445.87,1263.78 445.87,1242.13 438.87,1235.13 421.7,1235.13 413.78,1243.05 413.78,1291.92 421.6,1299.74 469.13,1299.74 486.69,1317.3 486.69,1341.15 495.76,1350.22 508.62,1350.22 509.34,1349.5 582.58,1349.5 597.11,1334.97 669.98,1334.97 713.1,1378.09 731.43,1378.09 816.5,1293.02 816.5,1291.42 833.42,1274.5 1138.51,1274.5 v2(1151.54,1287.48)
  BottomLayer - S8 (.GBL) w4.92: R128.5@455.16,1448.5 455.16,1410.44 447.58,1402.86 447.58,1370.21 451.95,1365.85 467.63,1365.85 476.64,1356.84 476.64,1312.83 ; 476.63,1312.82 476.63,1312.6 467.72,1303.69 467.72,1287.03 471.89,1282.86 486.85,1282.86 v2(496.15,1292.16)
DDR_BA2: R133.8 U15.B3 U17.M3 | length 1203.8
  TopLayer - S1 (.GTL) w4.92: v2(575,1250) 564,1250 559,1245 559,1233 565,1227 598,1227 602.99,1231.99 U17.M3@602.99,1240.24 ; v2(1214.53,1381.97) U15.B3@1230.28,1366.22
  MidLayer2 - S3 (.G2) w4.68: v2(575,1250) 575,1275 557,1293 557,1342 564.46,1349.46 575.54,1349.46 582,1343 582,1320.95 599.47,1303.48 625.17,1303.48 634.24,1312.55 634.24,1321 642.24,1329 665,1329 672.07,1336.07 672.07,1351.07 685,1364 700,1364 704,1360 704,1352 708.91,1347.09 731.43,1347.09 744.84,1360.5 805.5,1360.5 817,1349 827,1349 840,1362 894.17,1362 909.04,1347.13 940.96,1347.13 959.81,1365.98 1198.48,1365.98 v2(1214.53,1381.97)
  BottomLayer - S8 (.GBL) w4.92: v2(575,1250) 575,1274.38 562.5,1286.88 562.5,1350.75 554.62,1358.63 554.62,1371.37 572.95,1389.7 572.95,1445.35 R133.8@576.1,1448.5
DDR_CASN: R133.5 U15.F1 U17.K3 | length 1260.8
  TopLayer - S1 (.GTL) w4.92: U17.K3@602.99,1177.24 618,1192.25 620,1192.25 v2(620,1192.99) ; v2(1151.54,1255.98) v2(1151.54,1255.98) U15.F1@1167.28,1240.26
  MidLayer2 - S3 (.G2) w4.68: v2(620,1192.99) 621,1191.99 621,1164.66 627.07,1158.59 652.59,1158.59 663.5,1169.5 663.5,1200.5 675.99,1212.99 729.79,1212.99 739.64,1203.14 783.22,1203.14 787.09,1207.01 787.09,1216.87 793,1222.78 802.46,1222.78 806.33,1218.91 806.33,1206.85 810.72,1202.46 820.32,1202.46 824.5,1206.64 824.5,1217.66 829.41,1222.57 835.63,1222.57 839.5,1218.7 839.5,1206.64 843.89,1202.25 850.11,1202.25 854.5,1206.64 854.5,1217.66 859.84,1223 882.75,1223 891.42,1231.67 891.42,1247 896.42,1252 935.05,1252 938.93,1248.12 938.93,1231.03 943.32,1226.64 949.54,1226.64 953.93,1231.03 953.93,1249.52 957.41,1253 965.45,1253 968.93,1249.52 968.93,1231.03 973.32,1226.64 979.54,1226.64 983.93,1231.03 983.93,1248.12 987.49,1251.68 987.49,1252 992.88,1257.39 992.88,1272.27 996.74,1276.13 1004.02,1276.13 1007.88,1272.27 1007.88,1243.99 1012.27,1239.6 1018.49,1239.6 1022.88,1243.99 1022.88,1272.61 1026.4,1276.13 1034.36,1276.13 1037.88,1272.61 1037.88,1244.39 1042.27,1240 1048.49,1240 1052.88,1244.39 1052.88,1267.61 1057.27,1272 1063.49,1272 1076.49,1259 1148.5,1259 v2(1151.54,1255.98)
  BottomLayer - S8 (.GBL) w4.92: v2(620,1192.99) 603.36,1209.63 603.36,1275.41 634.86,1306.91 634.86,1398.52 640.8,1404.46 640.8,1442.86 R133.5@635.16,1448.5
DDR_CKE: R131.2 U15.G3 U17.K9 | length 1068.5
  TopLayer - S1 (.GTL) w4.92: v2(390,1167) 400.24,1177.24 U17.K9@414.02,1177.24 ; v2(1214.53,1224.49) U15.G3@1230.28,1208.76
  MidLayer2 - S3 (.G2) w4.68: v2(390,1167) 414.26,1142.75 414.26,1123.57 423.33,1114.5 500.71,1114.5 520.21,1134 528.29,1134 553.05,1158.76 575.73,1158.76 588.99,1145.5 656.67,1145.5 683.72,1118.45 717.2,1118.45 725.25,1126.5 863.28,1126.5 894.66,1157.88 1013.88,1157.88 1033.5,1177.5 1189.43,1177.5 1198.63,1186.7 1198.63,1208.63 v2(1214.53,1224.49)
  BottomLayer - S8 (.GBL) w4.92: R131.2@335,1134 357,1134 v2(390,1167)
DDR_CLK_N: R127.1 U15.D1 U17.K7 | length 1215.3
  TopLayer - S1 (.GTL) w4: 495.17,1177.24 508.98,1191.05 552.47,1191.05 558.3,1185.22 558.3,1177.66 551.71,1171.07 544.07,1171.07 v2(539.35,1175.79)
  TopLayer - S1 (.GTL) w4.92: U17.K7@477.01,1177.24 495.17,1177.24 ; v2(1151.54,1318.98) v2(1151.54,1318.98) U15.D1@1167.28,1303.25
  MidLayer2 - S3 (.G2) w3.98: v2(539.35,1175.79) 540,1176.44 540,1197 544,1201 554.18,1201 559.38,1195.8 559.38,1183.21 572.21,1170.38 590.37,1170.38 603.74,1183.75 603.74,1275.76 610.96,1282.98 639.96,1282.98 659.98,1303 689.98,1303 705.21,1318.23 719.18,1318.23 730.85,1306.56 753.35,1306.56 774.88,1328.09 791.93,1328.09 795,1325.02 795,1313 805,1303 840,1303 850,1313 850,1326 854,1330 877.96,1330 881,1326.96 881,1315 893,1303 942.54,1303 972.53,1332.99 1104.93,1332.99 1114.44,1323.48 1147.01,1323.48 v2(1151.54,1318.98)
  BottomLayer - S8 (.GBL) w4: v2(539.35,1175.79) 546.16,1168.98 680.51,1168.98 695.99,1153.5 714.8,1153.5 717.52,1156.22 717.52,1170 R127.1@731.38,1170
DDR_CLK_P: R126.1 U15.D2 U17.J7 | length 1244.6
  TopLayer - S1 (.GTL) w4: U17.J7@477.01,1145.75 477.01,1160.7 480.66,1164.35 499.26,1164.35 v2@510.96,1176.05
  TopLayer - S1 (.GTL) w4.92: v2@510.96,1176.05 v2(515.2,1176.05) ; v2(1183.03,1318.98) v2(1183.03,1318.98) U15.D2@1198.78,1303.25
  MidLayer2 - S3 (.G2) w3.98: v2(515.2,1176.05) 515.2,1176.2 528,1189 528,1201.98 539.02,1213 559.16,1213 571.38,1200.78 571.38,1188.19 577.19,1182.38 585.39,1182.38 591.74,1188.73 591.74,1280.74 605.98,1294.98 634.98,1294.98 655,1315 685,1315 700.23,1330.23 724.16,1330.23 735.83,1318.56 748.37,1318.56 769.9,1340.09 796.91,1340.09 807,1330 807,1317.98 809.98,1315 835.02,1315 838,1317.98 838,1330.98 849.02,1342 882.94,1342 893,1331.94 893,1319.98 897.98,1315 937.56,1315 967.55,1344.99 1109.91,1344.99 1119.42,1335.48 1166.51,1335.48 v2(1183.03,1318.98)
  BottomLayer - S8 (.GBL) w4: v2(515.2,1176.05) 534.27,1156.98 675.53,1156.98 691.01,1141.5 714.8,1141.5 717.52,1138.78 717.52,1125 R126.1@731.38,1125
DDR_CSN: R133.1 U15.H2 U17.L2 | length 1246.7
  TopLayer - S1 (.GTL) w4.92: U17.L2@634.49,1208.74 645.74,1208.74 659.5,1222.5 672.13,1222.5 v2(697.14,1197.49) ; v2(1183.03,1192.99) U15.H2@1198.78,1177.26
  MidLayer2 - S3 (.G2) w4.68: v2(697.14,1197.49) 679.62,1197.49 674.08,1191.95 674.08,1176.73 683.88,1166.93 683.88,1158.42 674.08,1148.62 674.08,1143.18 685,1132.26 717.59,1132.26 723.18,1137.85 723.18,1144.71 718.87,1149.02 706.06,1149.02 703.04,1152.04 703.04,1157.57 711.1,1165.63 733.01,1165.63 737.63,1161.01 737.63,1147.38 743.04,1141.97 857.53,1141.97 889.3,1173.74 917.34,1173.74 922.74,1179.14 922.74,1193.55 925.32,1196.13 936.59,1196.13 940.72,1192 940.72,1175.56 943.4,1172.88 952.1,1172.88 955.25,1176.03 955.25,1192.3 959.08,1196.13 967.88,1196.13 970.25,1193.76 970.25,1176.03 973.4,1172.88 982.1,1172.88 985.51,1176.29 985.51,1189.21 991.5,1195.2 998.02,1195.2 1003.73,1189.49 1003.73,1185.73 1008.73,1180.73 1014.46,1180.73 1019.46,1185.73 1019.46,1204.35 1023.11,1208 1038.45,1208 1041.11,1205.34 1041.11,1193.26 1045.5,1188.87 1051.72,1188.87 1056.11,1193.26 1056.11,1205.2 1060.97,1210.06 1071.8,1210.06 1074.5,1207.36 1074.5,1190 1078,1186.5 1103,1186.5 1111,1194.5 1111,1203 1116.99,1208.99 1166.01,1208.99 1182,1193 v2(1183.03,1192.99)
  BottomLayer - S8 (.GBL) w4.92: v2(697.14,1197.49) 691.35,1203.28 691.35,1311.38 709.62,1329.65 709.62,1416.45 713.9,1420.73 R133.1@713.9,1448.5
DDR_D0: U15.M3 U17.H7 | length 982.7
  TopLayer - S1 (.GTL) w4.92: U17.H7@477.01,1114.25 526.42,1114.25 v2(529.28,1111.39) ; v2(1214.53,1035.51) U15.M3@1230.28,1051.26
  MidLayer5 - S6 (.G5) w4.68: v2(529.28,1111.39) 530.17,1110.5 530.17,1087 522.67,1079.5 485.26,1079.5 476.43,1088.33 476.43,1105.1 496.38,1125.05 518.23,1125.05 524.01,1130.83 535.62,1130.83 541.4,1125.05 570.66,1125.05 575.36,1129.75 597.06,1129.75 612.31,1114.5 687.76,1114.5 699.37,1102.89 1071.22,1102.89 1076.36,1097.75 1117.04,1097.75 1132.29,1082.5 1189.43,1082.5 1199,1072.93 1199,1060.57 1214.5,1045.07 v2(1214.53,1035.51)
DDR_D1: U15.M4 U17.F8 | length 990.7
  TopLayer - S1 (.GTL) w4.92: v2(429.76,1067.01) U17.F8@445.51,1051.26 ; v2(1246.02,1035.51) U15.M4@1261.77,1051.26
  MidLayer5 - S6 (.G5) w4.68: v2(429.76,1067.01) 445.98,1083.23 445.98,1090.98 491.23,1136.23 516.68,1136.23 525.95,1145.5 543.72,1145.5 555.7,1157.48 569.34,1157.48 581.32,1145.5 656.67,1145.5 676.28,1125.89 710,1125.89 717.95,1117.94 1068.89,1117.94 1074.94,1111.89 1080.09,1106.75 1098.49,1106.75 1119.33,1127.59 1133.41,1127.59 1147.01,1113.99 1189.43,1113.99 1199,1104.42 1199,1092.07 1208.57,1082.5 1220.93,1082.5 1230.13,1073.3 1230.13,1051.37 v2(1246.02,1035.51)
DDR_D2: U15.N1 U17.G2 | length 982
  TopLayer - S1 (.GTL) w4.92: v2(618.74,1067.01) U17.G2@634.49,1082.76 ; v2(1151.54,1004.02) U15.N1@1167.28,1019.76
  MidLayer5 - S6 (.G5) w4.68: v2(618.74,1067.01) 646.92,1038.83 655.96,1038.83 695.34,999.45 707.63,999.45 712.07,995.01 877.7,995.01 882.09,999.4 882.09,1014.96 886.48,1019.35 892.7,1019.35 897.09,1014.96 897.09,999.4 901.48,995.01 907.7,995.01 912.09,999.4 912.09,1014.96 916.48,1019.35 922.7,1019.35 927.09,1014.96 927.09,999.4 931.48,995.01 937.7,995.01 942.09,999.4 942.09,1014.96 946.48,1019.35 952.7,1019.35 957.09,1014.96 957.09,999.4 961.48,995.01 967.7,995.01 972.09,999.4 972.09,1014.96 976.48,1019.35 982.7,1019.35 987.09,1014.96 987.09,999.4 991.48,995.01 1007.58,995.01 1011.75,999.18 1011.75,1015.27 1015.89,1019.41 1023.53,1019.41 1028.08,1014.86 1028.08,979.7 1032.92,974.86 1042.76,974.86 1047.15,979.25 1047.15,1011.06 1051.54,1015.45 1057.76,1015.45 1062.15,1011.06 1062.15,979.25 1066.54,974.86 1072.76,974.86 1077.15,979.25 1077.15,1011.06 1081.54,1015.45 1087.76,1015.45 1092.15,1011.06 1092.15,979.25 1096.54,974.86 1105.34,974.86 1114.42,983.94 1114.42,999 1119.42,1004 v2(1151.54,1004.02)
DDR_D3: U15.N2 U17.F2 | length 975.6
  TopLayer - S1 (.GTL) w4.92: U17.F2@634.49,1051.26 v2(650.24,1067.01) ; v2(1183.03,1004.02) U15.N2@1198.78,1019.76
  MidLayer5 - S6 (.G5) w4.68: v2(650.24,1067.01) 638.68,1078.57 638.68,1086.44 645.7,1093.46 660.59,1093.46 670,1084.05 670,1044.16 697.63,1016.53 734.65,1016.53 740.42,1022.3 740.42,1041.38 743.37,1044.33 753.96,1044.33 758.49,1039.8 758.49,1015.14 762.88,1010.75 769.1,1010.75 773.49,1015.14 773.49,1036.61 777.87,1040.99 779.72,1040.99 ; 779.73,1041 784.1,1041 788.49,1036.61 788.49,1015.14 792.88,1010.75 799.1,1010.75 803.49,1015.14 803.49,1031.61 807.88,1036 814.1,1036 818.49,1031.61 818.49,1015.14 822.88,1010.75 829.1,1010.75 833.49,1015.14 833.49,1031.61 837.88,1036 844.1,1036 848.49,1031.61 848.49,1015.14 852.88,1010.75 859.1,1010.75 863.49,1015.14 863.49,1031.61 872.23,1040.35 1010.77,1040.35 1015.16,1044.74 1015.16,1062.53 1019.55,1066.92 1025.77,1066.92 1030.16,1062.53 1030.16,1044.74 1034.55,1040.35 1040.77,1040.35 1045.16,1044.74 1045.16,1062.53 1049.55,1066.92 1055.77,1066.92 1060.16,1062.53 1060.16,1044.74 1064.55,1040.35 1117.81,1040.35 1138.66,1019.5 1164.29,1019.5 1179.79,1004 v2(1183.03,1004.02)
DDR_D4: U15.N3 U17.H3 | length 980
  TopLayer - S1 (.GTL) w4.92: v2(581.79,1114.25) U17.H3@602.99,1114.25 ; v2(1214.53,1004.02) U15.N3@1230.28,1019.76
  MidLayer5 - S6 (.G5) w4.68: v2(581.79,1114.25) 601.04,1095 620,1095 630.5,1105.5 683.29,1105.5 700.9,1087.89 844.26,1087.89 848.65,1083.5 848.65,1069.39 853.04,1065 859.26,1065 863.65,1069.39 863.65,1083.5 868.04,1087.89 874.26,1087.89 878.65,1083.5 878.65,1069.39 883.04,1065 889.26,1065 893.65,1069.39 893.65,1083.5 898.04,1087.89 904.26,1087.89 908.65,1083.5 908.65,1069.39 913.04,1065 919.26,1065 923.65,1069.39 923.65,1083.5 928.04,1087.89 934.26,1087.89 938.65,1083.5 938.65,1069.39 943.04,1065 949.26,1065 953.65,1069.39 953.65,1083.5 958.04,1087.89 964.26,1087.89 968.65,1083.5 968.65,1069.39 973.04,1065 979.26,1065 983.65,1069.39 983.65,1083.5 988.04,1087.89 1070.74,1087.89 1086.26,1072.37 1115.98,1072.37 1137.35,1051 1189.43,1051 1199,1041.43 1199,1029.07 1208.07,1020 1222.37,1020 1230.56,1011.81 1230.5,1011.75 1230.5,991.45 1227.05,988 1217.72,988 1214.5,991.22 v2(1214.53,1004.02)
DDR_D5: U15.N4 U17.H8 | length 985.3
  TopLayer - S1 (.GTL) w4.92: U17.H8@445.51,1114.25 461.29,1130.03 488.55,1130.03 v2(510.25,1151.73) ; v2(1246.02,1004.02) U15.N4@1261.77,1019.76
  MidLayer5 - S6 (.G5) w4.68: v2(510.25,1151.73) 514.23,1155.71 541.2,1155.71 551.97,1166.48 573.07,1166.48 583.84,1155.71 669.97,1155.71 686.02,1139.66 688.06,1139.66 688.48,1139.24 1081.34,1139.24 1085.57,1143.47 1191.92,1143.47 1230.5,1104.89 1230.5,1092.07 1240.07,1082.5 1252.43,1082.5 1261.5,1073.43 1261.5,1019.5 v2(1246.02,1004.02)
DDR_D6: U15.P3 U17.E3 | length 981.3
  TopLayer - S1 (.GTL) w4.92: v2(544.71,989.54) 574.93,1019.76 U17.E3@602.99,1019.76 ; v2(1214.53,972.52) U15.P3@1230.28,988.27
  MidLayer5 - S6 (.G5) w4.68: v2(544.71,989.54) 544.71,978.81 551.25,972.27 559.02,972.27 643.79,887.5 673.49,887.5 680.72,880.27 733.5,880.27 742.11,888.88 954.89,888.88 960.11,894.1 960.11,923.13 964.05,927.07 971.01,927.07 975.11,922.97 975.11,894.1 979.5,889.71 1060.78,889.71 1065.17,885.32 1065.17,874.77 1069.56,870.38 1075.78,870.38 1080.17,874.77 1080.17,885.32 1084.56,889.71 1089.87,889.71 1094.11,893.95 1094.11,908.14 1098.5,912.53 1104.72,912.53 1109.11,908.14 1109.11,894.1 1113.5,889.71 1122.57,889.71 1205.36,972.5 v2(1214.53,972.52)
DDR_D7: U15.P4 U17.F7 | length 976
  TopLayer - S1 (.GTL) w4.92: U17.F7@477.01,1051.26 497.8,1051.26 v2(532.13,1016.93) ; v2(1246.02,972.52) U15.P4@1261.77,988.27
  MidLayer5 - S6 (.G5) w4.68: v2(532.13,1016.93) 529.21,1014.01 529.21,951.68 571.11,909.78 586.65,909.78 618.49,877.94 618.49,861.74 628.73,851.5 1103.07,851.5 1208.07,956.5 1230,956.5 v2(1246.02,972.52)
DDR_D8: U15.J1 U17.C3 | length 981.2
  TopLayer - S1 (.GTL) w4.92: v2(552.59,956.77) U17.C3@602.99,956.77 ; v2(1092,1127.97) 1120.38,1156.4 1156.65,1156.4 U15.J1@1167.28,1145.77
  MidLayer2 - S3 (.G2) w4.68: v2(552.59,956.77) 530.4,956.77 524.54,962.63 524.54,994.54 515.31,1003.77 494.28,1003.77 486.69,1011.36 486.69,1026.19 494.36,1033.86 494.36,1038.74 501.98,1046.36 530.24,1046.36 538.56,1038.04 538.56,1032.43 545.95,1025.04 565.36,1025.04 570.32,1020.08 570.32,1004.23 574.77,999.78 591.94,999.78 596.94,1004.78 596.94,1020.98 602.54,1026.58 687.58,1026.58 695.23,1018.93 721.45,1018.93 741.02,1038.5 802.79,1038.5 825.37,1061.08 926.3,1061.08 951.35,1086.13 1043.68,1086.13 1085.52,1127.97 v2(1092,1127.97)
DDR_D9: U15.K1 U17.C2 | length 977.3
  TopLayer - S1 (.GTL) w4.92: v2(618.74,941.02) U17.C2@634.49,956.77 ; v2(1151.54,1098.5) U15.K1@1167.28,1114.25
  MidLayer2 - S3 (.G2) w4.68: v2(618.74,941.02) 590.95,941.02 585.32,946.65 585.32,958.11 595.6,968.39 613.66,968.39 622.81,959.24 640.02,959.24 649.17,968.39 659.07,968.39 665.74,961.72 665.74,943.83 670.56,939.01 678.94,939.01 683.58,943.65 683.58,988.26 694.77,999.45 707.63,999.45 717.89,989.19 952.03,989.19 969.66,1006.82 969.66,1041.13 974.44,1045.91 984.17,1045.91 988.17,1041.91 988.17,1004.85 992.56,1000.46 1001.89,1000.46 1006.28,1004.85 1006.28,1041.91 1010.67,1046.3 1020.78,1046.3 1025.17,1041.91 1025.17,1004.85 1029.56,1000.46 1038.9,1000.46 1043.51,1000.45 1049.38,1006.32 1049.38,1046.12 1099.85,1096.59 1149.6,1096.59 v2(1151.54,1098.5)
DDR_D10: U15.K2 U17.D7 | length 983.1
  TopLayer - S1 (.GTL) w4.92: U17.D7@477.01,988.27 v2(504.52,988.27) ; v2(1183.03,1098.5) U15.K2@1198.78,1114.25
  MidLayer2 - S3 (.G2) w4.68: v2(504.52,988.27) 481.24,988.27 473.16,996.35 473.16,1025.39 479.27,1031.5 479.27,1060.35 490.29,1071.37 541.11,1071.37 549.6,1062.88 549.6,1049.33 559.54,1039.39 698.05,1039.39 716.55,1057.89 740.02,1057.89 743.5,1061.37 743.5,1070 750,1076.5 770,1076.5 776.5,1070 776.5,1062.53 785.53,1053.5 796.1,1053.5 802.36,1059.76 802.36,1068.57 809.87,1076.08 907.85,1076.08 937.9,1106.13 1037.87,1106.13 1050.01,1118.27 1050.01,1118.97 1075,1143.96 1148.4,1143.96 1183,1109.36 v2(1183.03,1098.5)
DDR_D11: U15.K3 U17.C8 | length 990.8
  TopLayer - S1 (.GTL) w4.92: U17.C8@445.51,956.77 v2(461.26,972.52) ; v2(1214.53,1098.5) U15.K3@1230.28,1114.25
  MidLayer2 - S3 (.G2) w4.68: v2(461.26,972.52) 445.76,988.02 445.76,1077.96 461.47,1093.67 582.83,1093.67 593.99,1082.51 662,1082.51 674.12,1094.63 694.16,1094.63 697.29,1091.5 902.05,1091.5 931.68,1121.13 1031.65,1121.13 1063.73,1153.21 1159.79,1153.21 v2(1214.53,1098.5)
DDR_D12: U15.K4 U17.A3 | length 992.7
  TopLayer - S1 (.GTL) w4.92: v2(602.99,871.51) U17.A3@602.99,893.78 ; v2(1246.02,1098.5) U15.K4@1261.77,1114.25
  MidLayer2 - S3 (.G2) w4.68: v2(602.99,871.51) 555.88,871.51 552.09,867.72 552.09,854.01 565.09,841.01 993.35,841.01 1009.3,856.96 1009.3,874.12 1026.05,890.87 1066.98,890.87 1125.79,949.68 1125.79,977.34 1136.95,988.5 1220.93,988.5 1230.13,997.7 1230.13,1082.63 v2(1246.02,1098.5)
DDR_D13: U15.L3 U17.A2 | length 980.8
  TopLayer - S1 (.GTL) w4.92: v2(634.49,871.51) U17.A2@634.49,893.78 ; v2(1214.53,1067.01) U15.L3@1230.28,1082.76
  MidLayer2 - S3 (.G2) w4.68: v2(634.49,871.51) 649.99,856.01 787.22,856.01 791.61,860.4 791.61,881.4 796,885.79 802.22,885.79 806.61,881.4 806.61,860.4 811,856.01 817.22,856.01 821.61,860.4 821.61,881.4 826,885.79 832.22,885.79 836.61,881.4 836.61,860.4 841,856.01 847.22,856.01 851.61,860.4 851.61,881.4 856,885.79 862.22,885.79 866.61,881.4 866.61,860.4 871,856.01 881.34,856.01 890.48,865.15 890.48,882.67 896.31,888.5 946.2,888.5 955.54,879.16 955.54,865.92 965.45,856.01 983.58,856.01 993.33,865.76 993.33,917.35 1005.8,929.82 1085.27,929.82 1109.1,953.65 1109.1,999.1 1130,1020 1189.43,1020 1198.5,1029.07 1198.5,1051 v2(1214.53,1067.01)
DDR_D14: U15.L4 U17.A7 | length 989
  TopLayer - S1 (.GTL) w4.92: U17.A7@477.01,893.78 491.1,893.78 v2(504.91,879.97) ; v2(1246.02,1067.01) U15.L4@1261.77,1082.76
  MidLayer2 - S3 (.G2) w4.68: v2(504.91,879.97) 558.87,826.01 1033.2,826.01 1164.19,957 1220.93,957 1230.5,966.57 1230.5,978.93 1240.07,988.5 1252.43,988.5 1261.5,997.57 1261.5,1051.5 v2(1246.02,1067.01)
DDR_D15: U15.M1 U17.B8 | length 984.4
  TopLayer - S1 (.GTL) w4.92: v2(429.76,941.03) U17.B8@445.51,925.28 ; v2(1151.54,1035.51) U15.M1@1167.28,1051.26
  MidLayer2 - S3 (.G2) w4.68: v2(429.76,941.03) 429.76,887.96 444.75,872.97 468.58,872.97 479.46,883.85 479.46,892.41 490.36,903.31 513.75,903.31 530.05,887.01 620.16,887.01 628.68,895.53 665.46,895.53 688,872.99 753.49,872.99 764.83,884.33 764.83,894.33 773.82,903.32 805.75,903.32 805.93,903.5 969.61,903.5 977.16,911.05 977.16,940.35 983.36,946.55 1081.54,946.55 1095.34,960.35 1095.34,1013.79 1117.05,1035.5 v2(1151.54,1035.51)
DDR_DQM0: U15.M2 U17.E7 | length 977.7
  TopLayer - S1 (.GTL) w4.92: U17.E7@477.01,1019.76 v2(502.19,1019.76) ; v2(1183.03,1035.51) U15.M2@1198.78,1051.26
  MidLayer5 - S6 (.G5) w4.68: v2(502.19,1019.76) 502.19,1046.26 520.43,1064.5 541.21,1064.5 560.9,1084.19 560.9,1084.6 569.97,1093.67 582.83,1093.67 591.9,1084.6 591.9,1066.05 638.43,1019.52 656.67,1019.52 665.74,1010.45 665.74,992.7 685.54,972.9 685.54,954.24 694.61,945.17 709.34,945.17 716.54,952.37 716.54,974.04 720.57,978.07 992.15,978.07 1010.36,959.86 1109.37,959.86 1138.01,988.5 1189.43,988.5 1198.5,997.57 1198.5,1016.84 1183,1032.34 v2(1183.03,1035.51)
DDR_DQM1: U15.J2 U17.D3 | length 986.1
  TopLayer - S1 (.GTL) w4.92: v2(581.19,977.5) 591.96,988.27 U17.D3@602.99,988.27 ; v2(1125.76,1112.09) 1140.25,1112.11 1158.17,1130.03 1183.04,1130.03 U15.J2@1198.78,1145.77
  MidLayer2 - S3 (.G2) w4.68: v2(581.19,977.5) 588.41,984.72 657.51,984.72 681.24,1008.45 726.55,1008.45 730.8,1004.2 777.94,1004.2 782.33,1008.59 782.33,1018.67 786.72,1023.06 792.94,1023.06 797.33,1018.67 797.33,1008.59 801.72,1004.2 807.94,1004.2 812.33,1008.59 812.33,1018.67 816.72,1023.06 822.94,1023.06 827.33,1018.67 827.33,1008.59 831.72,1004.2 837.94,1004.2 842.69,1008.95 842.69,1036.47 847.08,1040.86 853.3,1040.86 857.69,1036.47 857.69,1008.23 861.72,1004.2 867.94,1004.2 872.69,1008.95 872.69,1036.47 877.08,1040.86 883.3,1040.86 887.69,1036.47 887.69,1008.23 891.72,1004.2 897.94,1004.2 902.69,1008.95 902.69,1036.47 907.08,1040.86 913.3,1040.86 917.33,1036.83 917.33,1008.59 921.72,1004.2 940.58,1004.2 949.59,1013.21 949.59,1055.99 959.72,1066.12 1043.28,1066.12 1089.25,1112.09 v2(1125.76,1112.09)
DDR_DQS0_N: U15.P2 U17.G3 | length 982.7
  TopLayer - S1 (.GTL) w4: v2@580.1,1081.87 602.1,1081.87 U17.G3@602.99,1082.76
  TopLayer - S1 (.GTL) w4.92: v2(576.4,1078.17) v2@580.1,1081.87 ; v2(1183.03,972.52) U15.P2@1198.78,988.27
  MidLayer5 - S6 (.G5) w3.98: v2(576.4,1078.17) 561.24,1063.01 561.24,1019.85 618.09,963 649.49,963 665.24,947.25 665.24,934.81 665.04,934.61 665.04,927.56 679.28,913.32 719.51,913.32 752.76,946.57 767.79,946.57 772.48,941.88 772.48,922.33 783.74,911.07 805.25,911.07 816.96,922.78 816.96,942.33 821.2,946.57 830.95,946.57 835.64,941.88 835.64,925.01 847.35,913.3 866.17,913.3 877.88,925.01 877.88,941.88 882.57,946.57 889.19,946.57 893.88,941.88 893.88,925.01 905.59,913.3 922.17,913.3 933.88,925.01 933.88,941.88 938.57,946.57 979.09,946.57 997.49,928.17 1143.64,928.17 1173.26,957.79 1173.26,959.18 1173.27,962.78 v2(1183.03,972.52)
DDR_DQS0_P: U15.P1 U17.F3 | length 982.6
  TopLayer - S1 (.GTL) w4: v2(576.24,1054.89) 591.22,1069.87 600.28,1069.87 602.99,1067.16
  TopLayer - S1 (.GTL) w4.92: U17.F3@602.99,1051.26 602.99,1067.16 ; v2(1151.54,972.52) U15.P1@1167.28,988.27
  MidLayer5 - S6 (.G5) w3.98: v2(576.24,1054.89) 573.24,1051.89 573.24,1024.83 580.45,1017.62 585.11,1017.62 600.51,1033.02 606.51,1033.02 611.37,1028.16 611.37,1022.62 595.89,1007.14 595.89,1002.18 623.07,975 654.47,975 677.24,952.23 677.24,932.34 684.26,925.32 714.53,925.32 747.78,958.57 772.77,958.57 784.48,946.86 784.48,927.31 788.72,923.07 800.27,923.07 804.96,927.76 804.96,947.31 816.22,958.57 835.93,958.57 847.64,946.86 847.64,929.99 852.33,925.3 861.19,925.3 865.88,929.99 865.88,946.86 877.59,958.57 894.17,958.57 905.88,946.86 905.88,929.99 910.57,925.3 917.19,925.3 921.88,929.99 921.88,946.86 933.59,958.57 984.07,958.57 1002.47,940.17 1138.66,940.17 1157.37,958.88 1157.37,966.64 v2(1151.54,972.52)
DDR_DQS1_N: U15.L2 U17.B7 | length 983.3
  TopLayer - S1 (.GTL) w4: U17.B7@477.46,925.73 526.94,925.73 v2(527.39,925.28)
  TopLayer - S1 (.GTL) w4.92: U17.B7@477.01,925.28 U17.B7@477.46,925.73 ; v2(1183.03,1067.01) U15.L2@1198.78,1082.76
  MidLayer2 - S3 (.G2) w4: v2(527.39,925.28) 531.78,920.89 536.02,920.89 558.63,898.28 594.66,898.28 610.4,914.02 651.47,914.02 ; 651.48,914.01 726.85,914.01 740.67,927.83 740.67,948.18 745.75,953.26 757.81,953.26 761.94,949.13 761.94,944.26 761.93,934.31 772.28,923.96 787.2,923.96 798.05,923.97 808.96,934.88 808.96,949.28 812.94,953.26 827.36,953.26 831.19,949.43 831.19,933.69 841.88,923 867.44,923 878.17,933.73 878.17,951.72 882.16,955.71 895.69,955.71 900.02,951.38 900.02,935.13 912.15,923 943.96,923 957.19,936.23 957.19,949.79 965.09,957.69 976.36,968.95 1065.03,968.95 1078.05,981.97 1078.05,1030.46 1102.59,1055 1142.28,1055 1145.28,1052 1168,1052 v2(1183.03,1067.01)
DDR_DQS1_P: U15.L1 U17.C7 | length 983.6
  TopLayer - S1 (.GTL) w4: 477.01,943.63 482.91,937.73 496.97,937.73 502.19,942.95 v2(502.19,956.77)
  TopLayer - S1 (.GTL) w4.92: 477.01,943.63 U17.C7@477.01,956.77 ; v2(1151.54,1067.01) U15.L1@1167.28,1082.76
  MidLayer2 - S3 (.G2) w4: v2(502.19,956.77) 518.69,940.28 533.61,940.28 563.61,910.28 589.68,910.28 605.42,926.02 656.45,926.02 721.87,926.01 728.67,932.81 728.67,953.16 740.77,965.26 762.79,965.26 773.94,954.11 773.94,939.28 777.26,935.96 782.22,935.96 ; 782.23,935.97 793.07,935.97 796.96,939.86 796.96,954.26 807.96,965.26 832.34,965.26 843.19,954.41 843.19,938.67 846.86,935 862.46,935 866.17,938.71 866.17,956.7 877.18,967.71 900.67,967.71 912.02,956.36 912.02,940.11 917.13,935 938.98,935 945.19,941.21 945.19,954.77 960.11,969.69 971.38,980.95 1060.05,980.95 1066.05,986.95 1066.05,1035.44 1097.61,1067 v2(1151.54,1067.01)
DDR_ODT: R133.2 U15.G1 U17.K1 | length 1268.9
  TopLayer - S1 (.GTL) w4.92: U17.K1@665.98,1177.24 696.26,1177.24 v2(698,1175.5) ; v2(1151.54,1224.49) 1141.41,1234.61 1126.09,1234.61 1116.34,1224.86 1116.34,1216.81 1124.39,1208.76 U15.G1@1167.28,1208.76
  MidLayer2 - S3 (.G2) w4.68: v2(698,1175.5) 718.07,1175.5 730,1187.43 745.61,1187.43 749,1184.04 749,1162.48 753.91,1157.57 760.13,1157.57 764,1161.44 764,1184.03 767.4,1187.43 776.01,1187.43 779,1184.44 779,1162.48 783.91,1157.57 790.13,1157.57 794,1161.44 794,1184.03 797.92,1187.95 805.49,1187.95 809,1184.44 809,1162.48 813.91,1157.57 820.13,1157.57 824,1161.44 824,1182.68 829.27,1187.95 835.09,1187.95 839,1184.04 839,1162.48 843.91,1157.57 850.13,1157.57 854.52,1161.96 854.52,1177.65 859.91,1183.04 873.04,1183.04 877.48,1187.48 877.48,1204.08 881.4,1208 888.97,1208 892.5,1204.47 892.5,1192.12 895.88,1188.74 901.77,1188.74 906.43,1193.4 906.43,1231.78 910.99,1236.34 918.61,1236.34 923.93,1231.02 923.93,1214.34 927.13,1211.14 929.47,1211.14 ; 929.48,1211.13 997.34,1211.13 1009.21,1223 1074.71,1223 1078.74,1227.03 1078.74,1243.1 1083.13,1247.49 1089.35,1247.49 1093.74,1243.1 1093.74,1227.53 1098.38,1222.89 1104.6,1222.89 1108.74,1227.03 1108.74,1243.1 1113.13,1247.49 1119.35,1247.49 1123.74,1243.1 1123.74,1227.53 1128.38,1222.89 1149.89,1222.89 v2(1151.54,1224.49)
  BottomLayer - S8 (.GBL) w4.92: R133.2@694.21,1448.5 694.21,1367.97 672.19,1345.95 672.19,1199.53 689.76,1181.96 691.54,1181.96 v2(698,1175.5)
DDR_RASN: R134.1 U15.G4 U17.J3 | length 1274.3
  TopLayer - S1 (.GTL) w4.92: v2(562.91,1141.98) 566.68,1145.75 U17.J3@602.99,1145.75 ; v2(1246.02,1224.49) U15.G4@1261.77,1208.76
  MidLayer2 - S3 (.G2) w4.68: v2(562.91,1141.98) 573.31,1131.58 592.27,1131.58 597.21,1126.64 597.21,1120.76 597.29,1120.68 597.29,1100.71 603.29,1094.71 649.29,1094.71 660.58,1106 726.21,1106 731.71,1111.5 869.5,1111.5 900.15,1142.15 1021.88,1142.15 1042.61,1162.88 1193.95,1162.88 1208.07,1177 1220.93,1177 1230.5,1167.43 1230.5,1132.93 1241,1122.43 1252.5,1122.43 1261.5,1131.43 1261.5,1209 v2(1246.02,1224.49)
  BottomLayer - S8 (.GBL) w4.92: v2(562.91,1141.98) 566.75,1145.82 659.18,1145.82 700,1105 815.63,1105 820,1109.37 R134.1@820,1128.88
DDR_RESETN: R129.1 U15.G2 U17.T2 | length 1231.4
  TopLayer - S1 (.GTL) w4.92: U17.T2@634.49,1366.22 v2(650.24,1381.97) 650.49,1382.22 672.61,1382.22 672.86,1381.97 R129.1@809.14,1381.97 ; v2(1183.03,1224.49) v2(1183.03,1224.49) U15.G2@1198.78,1208.76
  MidLayer5 - S6 (.G5) w4.68: v2(650.24,1381.97) 664.8,1367.41 685.66,1367.41 708.38,1390.13 747.68,1390.13 812.51,1325.3 831.38,1325.3 835.77,1320.91 835.77,1300.44 840.16,1296.05 846.38,1296.05 850.77,1300.44 850.77,1320.91 855.16,1325.3 861.38,1325.3 865.77,1320.91 865.77,1300.44 870.16,1296.05 876.38,1296.05 880.77,1300.44 880.77,1320.91 885.16,1325.3 891.38,1325.3 895.77,1320.91 895.77,1300.44 900.16,1296.05 906.38,1296.05 910.77,1300.44 910.77,1320.91 915.16,1325.3 921.38,1325.3 925.77,1320.91 925.77,1300.44 930.16,1296.05 936.38,1296.05 940.77,1300.44 940.77,1320.91 945.16,1325.3 951.38,1325.3 955.77,1320.91 955.77,1300.44 960.16,1296.05 966.38,1296.05 970.77,1300.44 970.77,1320.91 975.16,1325.3 981.38,1325.3 985.77,1320.91 985.77,1300.44 990.16,1296.05 996.38,1296.05 1000.77,1300.44 1000.77,1320.91 1005.16,1325.3 1011.38,1325.3 1015.77,1320.91 1015.77,1300.44 1020.16,1296.05 1026.38,1296.05 1030.77,1300.44 1030.77,1320.91 1035.16,1325.3 1050.59,1325.3 1054.98,1320.91 1054.98,1298.89 1059.37,1294.5 1067.37,1294.5 1078.37,1305.5 1096.43,1305.5 1098.44,1303.49 1157.43,1303.49 1167,1293.92 1167,1281.56 1176.57,1271.99 1188.94,1271.99 1198.5,1262.43 1198.5,1249.57 1189.43,1240.5 1189.35,1240.5 1183,1234.15 v2(1183.03,1224.49)
DDR_VREF: C199.1 C208.1 C209.1 TP2.1 U15.J4 U17.H1 U17.M8 U20.6 | length 1561.2
  TopLayer - S1 (.GTL) w5: v2(429.76,1255.99) U17.M8@445.51,1240.24
  TopLayer - S1 (.GTL) w6: v2(1246.02,1161.5) U15.J4@1261.75,1145.77
  TopLayer - S1 (.GTL) w13.78: U17.H1@665.98,1114.25 708.58,1114.25 v2@761.32,1061.52
  BottomLayer - S8 (.GBL) w8: U20.6@334.37,1465.38 334.37,1392.01 C209.1@336.38,1390
  BottomLayer - S8 (.GBL) w12: C199.1@1055,1178.88 1055,1155 1060,1150 1125,1150 1133.27,1141.73 1226.26,1141.73 v2(1246.02,1161.5)
  BottomLayer - S8 (.GBL) w15: C209.1@336.38,1390 336.38,1326.38 321,1311 321,1274 339.01,1255.99 v2(429.76,1255.99) 429.76,1236.62 C208.1@442.7,1223.68
  BottomLayer - S8 (.GBL) w20: C208.1@442.7,1223.68 442.7,1213.85 464.18,1192.37 464.18,1120.15 513.06,1071.27 527.33,1071.27 566.71,1031.89 665.01,1031.89 679.66,1017.24 760,1017.24 TP2.1@760,1047.5 ; TP2.1@761.81,1060 860,1060 972.5,1172.5 C199.1@1052.5,1172.5
  other v2: 760.83,1061.02
DDR_VTT_EN: R137.1 U15.F16 U20.7 | length 1932
  TopLayer - S1 (.GTL) w4.92: U15.F16@1639.72,1240.26 v2(1655.47,1255.98)
  MidLayer2 - S3 (.G2) w4.72: v1(1641.73,1519.69) 1671.26,1490.16 1671.26,1319.88 1655.47,1304.09 v2(1655.47,1255.98)
  MidLayer5 - S6 (.G5) w5.91: v1(305.5,1342.5) 491,1528 1001.97,1528 1027.02,1502.95 1175.2,1502.95 v8(1213.58,1464.57)
  BottomLayer - S8 (.GBL) w5.91: R137.1@271.12,1342.5 v1(305.5,1342.5) 305.5,1423.5 314.68,1432.68 U20.7@314.68,1465.38 ; v8(1213.58,1464.57) 1269.07,1464.57 1329,1524.5 1521.76,1524.5 1526.57,1519.69 v1(1641.73,1519.69)
DDR_WEN: R128.2 U15.B2 U17.L3 | length 1226.7
  TopLayer - S1 (.GTL) w4.92: v2(529.79,1242.28) 529.79,1241.24 562.29,1208.74 U17.L3@602.99,1208.74 ; v2(1183.03,1381.97) U15.B2@1198.78,1366.22
  MidLayer2 - S3 (.G2) w4.68: v2(529.79,1242.28) 523.11,1235.6 498.25,1235.6 493.23,1240.62 493.23,1251.6 499.44,1257.81 522.7,1257.81 534.72,1269.83 534.72,1282.49 545,1292.77 545,1361.93 563.57,1380.5 576.43,1380.5 580.93,1376 634.28,1376 643.81,1366.47 656.67,1366.47 701.2,1411 871.4,1411 873.9,1408.5 994.04,1408.5 1008.54,1423 1119,1423 1144,1398 1167,1398 v2(1183.03,1381.97)
  BottomLayer - S8 (.GBL) w4.92: R128.2@514.21,1448.5 514.21,1416.12 530.54,1399.79 530.54,1337.47 544.5,1323.51 544.5,1290.84 534.29,1280.63 534.29,1246.78 v2(529.79,1242.28)
EMU2_GPIO0_19: R161.1 U15.A15 | length 555.2
  TopLayer - S1 (.GTL) w4.75: U15.A15@1608.23,1397.72 1608.23,1429.09 1623.03,1443.9 v2(1641.73,1443.9)
  MidLayer2 - S3 (.G2) w4.75: v2(1641.73,1443.9) 1577.76,1507.87 1577.76,1751.97 v1(1657.48,1831.69)
  BottomLayer - S8 (.GBL) w5.91: v1(1657.48,1831.69) R161.1@1657.5,1866 R161.1@1657.5,1868.5
EMU2R: J8.17 R161.2 | length 154.3
  TopLayer - S1 (.GTL) w5.91: J8.17@1637.5,2075 1647.64,2064.86 1647.64,1976.38 v1(1657.48,1966.54)
  BottomLayer - S8 (.GBL) w5.91: R161.2@1657.5,1929 v1(1657.48,1966.54)
EMU3_GPIO0_20: R162.1 U15.D14 | length 932.7
  TopLayer - S1 (.GTL) w4.75: U15.D14@1576.73,1303.25 v2(1592.48,1318.98)
  MidLayer2 - S3 (.G2) w4.72: v2(1592.48,1318.98) 1608.27,1334.76 1608.27,1457.68 1566.93,1499.02 1566.93,1790.35 1588.58,1812.01 1588.58,1978.35 v1@1612.2,2001.97
  BottomLayer - S8 (.GBL) w5.91: v1@1612.2,2001.97 v1(1612.2,2003.94) 1612.2,2070.87 1632.5,2091.16 R162.1@1632.5,2178.5
EMU3R: J8.18 R162.2 | length 123.9
  TopLayer - S1 (.GTL) w5.91: J8.18@1637.5,2210.04 v1(1637.5,2283.96)
  BottomLayer - S8 (.GBL) w5.91: R162.2@1629,2242.5 1637.5,2242.5 v1(1637.5,2283.96)
EMU4: R163.1 U15.A14 | length 593.3
  TopLayer - S1 (.GTL) w4.75: U15.A14@1576.73,1397.72 1576.73,1437.95 1616.14,1477.36 v1(1641.73,1477.36)
  MidLayer2 - S3 (.G2) w4.72: 1591.54,1694.88 1591.54,1708.78 v1(1715,1832.24)
  MidLayer2 - S3 (.G2) w4.75: 1591.54,1694.88 1591.54,1512.8 1626.97,1477.36 v1(1641.73,1477.36)
  BottomLayer - S8 (.GBL) w5.91: v1(1715,1832.24) R163.1@1715,1866 R163.1@1715,1868.5
EMU4R: J8.19 R163.2 | length 155.4
  TopLayer - S1 (.GTL) w5.91: J8.19@1687.5,2075 1697.83,2064.67 1697.83,1984.25 v1(1715.55,1966.54)
  BottomLayer - S8 (.GBL) w5.91: R163.2@1715,1931.5 1715.55,1932.05 v1(1715.55,1966.54)
EMU_RSTN: C242.2 J8.15 R164.2 | length 218.6
  TopLayer - S1 (.GTL) w5.91: v1(1554.13,1966.54) 1576.77,1989.17 1576.77,2064.27 J8.15@1587.5,2075
  BottomLayer - S8 (.GBL) w5.91: C242.2@1550,1936.12 1550,1944.88 C242.2@1554.13,1944.88 ; v1(1554.13,1966.54) C242.2@1554.13,1944.88 ; R164.2@1600,1929 1600,1944.88 C242.2@1554.13,1944.88
FT_SRESET: R145.2 R165.2 U24.2 | length 946.4
  TopLayer - S1 (.GTL) w5.91: U24.2@1887.5,2162.4 1891.73,2166.63 1891.73,2187.99 1900.59,2196.85 v1(1900.59,2265.75)
  TopLayer - S1 (.GTL) w9.84: v1(2138.62,2922.5) R145.2@2173.5,2922.5
  MidLayer2 - S3 (.G2) w5.91: v1(1900.59,2265.75) 1862.2,2304.13 1862.2,2543.31 2157.48,2838.58 2157.48,2903.64 v1(2138.62,2922.5)
FT_VDD1V8: C248.2 C249.2 C250.2 C251.1 U22.12 U22.37 U22.49 U22.64 | length 372.5
  TopLayer - S1 (.GTL) w9.84: U22.37@2506.1,2794 v1(2506.1,2842.72) ; U22.64@2793.5,3160.14 U22.64@2817.91,3160.14 ; v1(2817.91,3183.07) U22.64@2817.91,3160.14 ; U22.64@2821.85,3160.14 U22.64@2817.91,3160.14
  TopLayer - S1 (.GTL) w11.81: v1(2506.1,3180.12) U22.12@2506.1,3231 ; v1(2744.78,2864.86) U22.49@2793.5,2864.86
  BottomLayer - S8 (.GBL) w9.84: v1(2506.1,2842.72) 2506.1,2873.88 C248.2@2507.5,2873.88 ; v1(2506.1,3180.12) 2532.5,3180.12 C249.2@2532.5,3191.38
  BottomLayer - S8 (.GBL) w15.75: v1(2674.21,2864.86) v1(2744.78,2864.86) ; C250.2@2817.5,3151.12 2817.91,3151.54 v1(2817.91,3183.07)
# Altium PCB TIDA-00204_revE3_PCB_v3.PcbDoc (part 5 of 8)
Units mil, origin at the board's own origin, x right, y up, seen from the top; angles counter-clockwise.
Board outline 4600 x 3740 mil, 8 copper layers (TopLayer - S1 (.GTL), MidLayer1 - S2 (.G1), MidLayer2 - S3 (.G2), MidLayer3 - S4 (.G3), MidLayer4 - S5 (.G4), MidLayer5 - S6 (.G5), MidLayer6 - S7 (.G6), BottomLayer - S8 (.GBL)), stack 58.938 mil thick; 537 components, 354 nets, 2015 pads, 1067 vias.

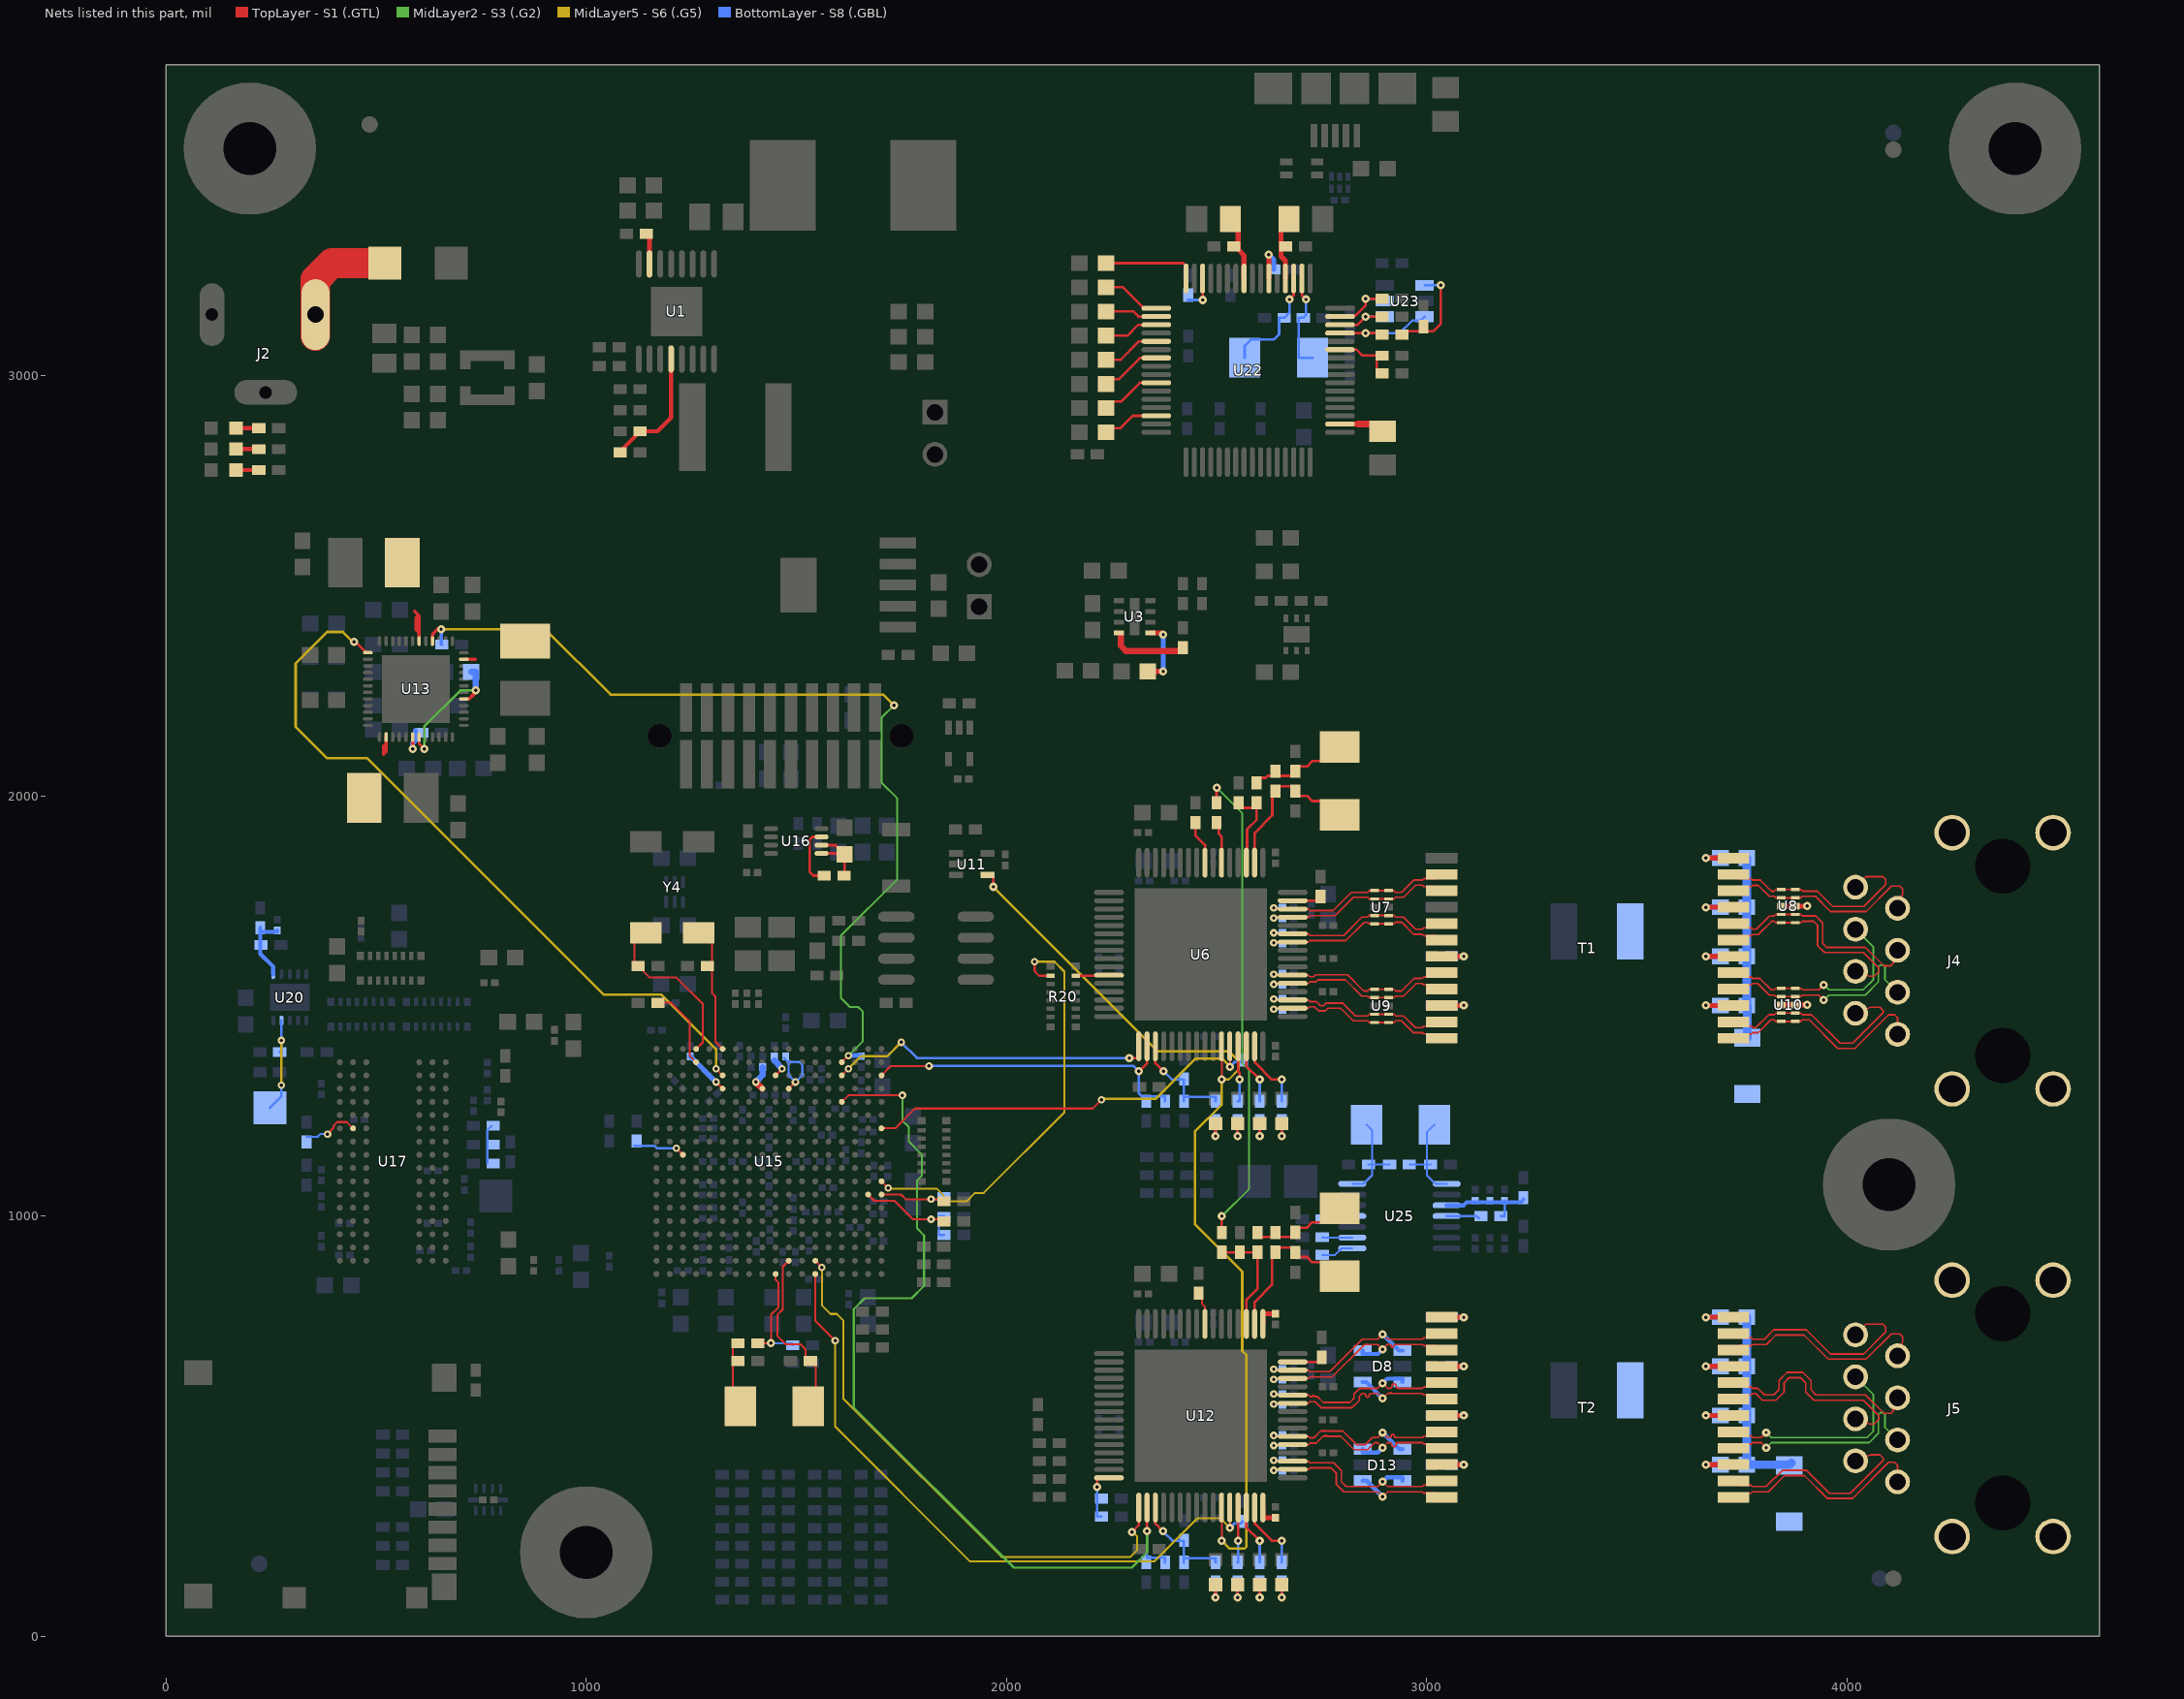
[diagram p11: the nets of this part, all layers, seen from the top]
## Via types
v1: diameter 19.68, hole 7.87, TopLayer - S1 (.GTL) to BottomLayer - S8 (.GBL), 600 vias
v2: diameter 17.72, hole 7.87, TopLayer - S1 (.GTL) to BottomLayer - S8 (.GBL), 408 vias
v3: diameter 27.56, hole 11.81, TopLayer - S1 (.GTL) to BottomLayer - S8 (.GBL), 31 vias
v4: diameter 20, hole 7.87, TopLayer - S1 (.GTL) to BottomLayer - S8 (.GBL), tented both sides, 11 vias
v5: diameter 15.75, hole 7.87, TopLayer - S1 (.GTL) to BottomLayer - S8 (.GBL), 9 vias
v6: diameter 20, hole 7.87, TopLayer - S1 (.GTL) to BottomLayer - S8 (.GBL), 5 vias
v7: diameter 15, hole 7.87, TopLayer - S1 (.GTL) to BottomLayer - S8 (.GBL), 2 vias
v8: diameter 18, hole 7.87, TopLayer - S1 (.GTL) to BottomLayer - S8 (.GBL), 1 vias

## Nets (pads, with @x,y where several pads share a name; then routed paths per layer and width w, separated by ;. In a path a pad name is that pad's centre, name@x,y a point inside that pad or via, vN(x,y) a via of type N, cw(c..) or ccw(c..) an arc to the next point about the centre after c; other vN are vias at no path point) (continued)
NetC29_1: C29.1 T1.7 | length 82.3
  TopLayer - S1 (.GTL) w12: T1.7@3034.96,1618.01 v1(3087.94,1618.01)
  BottomLayer - S8 (.GBL) w12: C29.1@3058.58,1618.01 v1(3087.94,1618.01)
NetC30_1: C30.1 T1.10 | length 82.3
  TopLayer - S1 (.GTL) w12: T1.10@3034.96,1501.08 v1(3087.94,1501.08)
  BottomLayer - S8 (.GBL) w12: C30.1@3058.58,1501.08 v1(3087.94,1501.08)
NetC31_1: C31.1 R36.1 U6.18 Y1.1 | length 389.3
  TopLayer - S1 (.GTL) w6: U6.18@2590.45,1841 2590.45,1911.95 2632.5,1954 2632.5,2003.88 R36.1@2640,2011.38 2640,2022.5 2676.12,2022.5 C31.1@2687.5,2011.12 2687.5,2000 2715,2000 2727.5,1987.5 2759.29,1987.5 Y1.1@2792.5,1954.29
NetC32_1: C32.1 R36.2 R170.1 Y1.2 | length 246
  TopLayer - S1 (.GTL) w5.91: R170.1@2595,2031.12 2595,2043 2617,2043 2621.5,2047.5
  TopLayer - S1 (.GTL) w6: 2621.5,2047.5 2676.12,2047.5 C32.1@2687.5,2058.88 2687.5,2070 2715,2070 2727.5,2082.5 2759.29,2082.5 Y1.2@2792.5,2115.71
NetC33_1: C33.1 R22.2 R24.2 R32.2 R37.2 | length 427.8
  BottomLayer - S8 (.GBL) w20: R22.2@3761.54,1851.87 R24.2@3761.54,1734.94 R32.2@3761.54,1618.01 R37.2@3761.54,1501.08 3762.5,1500.12 C33.1@3762.5,1424.43
NetC53_1: C53.1 U12.17 | length 50
  TopLayer - S1 (.GTL) w11.81: U12.17@2613.5,767.5 C53.1@2639.5,767.5
  TopLayer - S1 (.GTL) w12: U12.17@2610.14,743.5 U12.17@2610.14,767.5
NetC54_1: C54.1 U12.64 | length 49
  TopLayer - S1 (.GTL) w11.81: U12.64@2613.5,282.5 C54.1@2638.5,282.5
  TopLayer - S1 (.GTL) w12: U12.64@2610.14,282.5 U12.64@2610.14,306.5
NetC55_1: C55.1 T2.1 | length 82.3
  TopLayer - S1 (.GTL) w12: T2.1@3034.96,759.37 v1(3087.94,759.37)
  BottomLayer - S8 (.GBL) w12: C55.1@3058.58,759.37 v1(3087.94,759.37)
NetC56_1: C56.1 T2.4 | length 82.3
  TopLayer - S1 (.GTL) w12: T2.4@3034.96,642.44 v1(3087.94,642.44)
  BottomLayer - S8 (.GBL) w12: C56.1@3058.58,642.44 v1(3087.94,642.44)
NetC57_1: C57.1 T2.7 | length 82.3
  TopLayer - S1 (.GTL) w12: T2.7@3034.96,525.51 v1(3087.94,525.51)
  BottomLayer - S8 (.GBL) w12: C57.1@3058.58,525.51 v1(3087.94,525.51)
NetC58_1: C58.1 T2.10 | length 82.3
  TopLayer - S1 (.GTL) w12: T2.10@3034.96,408.58 v1(3087.94,408.58)
  BottomLayer - S8 (.GBL) w12: C58.1@3058.58,408.58 v1(3087.94,408.58)
NetC59_1: C59.1 R42.2 R48.2 R58.2 R64.2 | length 459.4
  BottomLayer - S8 (.GBL) w20: R42.2@3761.54,759.37 R48.2@3761.54,642.44 R58.2@3761.54,525.51 R64.2@3761.54,408.58 3863.31,408.58 C59.1@3868.11,413.39
NetC60_1: C60.1 R65.1 U12.18 Y2.1 | length 394.3
  TopLayer - S1 (.GTL) w6: U12.18@2590.45,743.5 2590.45,795.45 2631.5,836.5 2631.5,925 2676.12,925 C60.1@2687.5,913.62 2687.5,902.5 2715,902.5 2727.5,890 2759.29,890 Y2.1@2792.5,856.79
NetC61_1: C61.1 R65.2 R172.1 Y2.2 | length 240.9
  TopLayer - S1 (.GTL) w6: R172.1@2597.5,961.12 2597.5,950 2676.12,950 C61.1@2687.5,961.38 2687.5,972.5 2715,972.5 2727.5,985 2759.29,985 Y2.2@2792.5,1018.21
NetC99_1: C99.1 U13.18 | length 74.7
  TopLayer - S1 (.GTL) w8: v1(587.13,2112) U13.18@587.13,2139.83
  BottomLayer - S8 (.GBL) w11.81: v1(587.13,2112) 587.13,2125.06 594,2131.94 C99.1@594,2156
NetC139_1: C139.1 U15.D9 | length 64.7
  TopLayer - S1 (.GTL) w15: v2(1403.5,1318.98) U15.D9@1419.25,1303.25
  BottomLayer - S8 (.GBL) w15: v2(1403.5,1318.98) 1420,1335.47 C139.1@1420,1354.51
NetC140_1: C140.1 U15.D11 | length 174.4
  TopLayer - S1 (.GTL) w5: U15.D11@1482.24,1303.25 v2(1497.99,1318.98)
  BottomLayer - S8 (.GBL) w5: C140.1@1470.23,1376.69 1482,1364.92 ; 1482,1364.92 1483.58,1366.5 1506.41,1366.5 1514.64,1358.27 1514.64,1335.63 v2(1497.99,1318.98) 1482,1335 1482,1364.92
NetC141_1: C141.1 U15.C10 | length 49.2
  TopLayer - S1 (.GTL) w5: U15.C10@1450.75,1334.72 v2@1466.02,1350.02
  TopLayer - S1 (.GTL) w10: v2@1466.02,1350.02 v2(1466.5,1350.47)
  BottomLayer - S8 (.GBL) w15: 1448,1370 v2(1466.5,1350.47)
NetC145_1: C145.1 U15.D6 | length 108.9
  TopLayer - S1 (.GTL) w6: v2(1309.02,1318.98) U15.D6@1324.76,1303.25
  BottomLayer - S8 (.GBL) w12: C145.1@1247.5,1379.51 1248.48,1379.51 v2(1309.02,1318.98)
NetC192_1: C192.1 R174.2 Y3.2 | length 212.5
  TopLayer - S1 (.GTL) w4.75: Y3.2@1348.88,510 C192.1@1348.88,655 ; C192.1@1361.38,655 C192.1@1348.88,655 ; R174.2@1361.38,697.5 1348.88,697.5 C192.1@1348.88,655
NetC193_1: C193.1 U15.U11 Y3.1 | length 460.7
  TopLayer - S1 (.GTL) w4.75: U15.U11@1482.24,893.78 1467.88,879.44 1467.88,777.88 1455,765 1455,715 1475,695 1510,695 1522,683 1522,666.62 C193.1@1533.62,655 1546.12,655 Y3.1@1546.12,510
NetC194_1: C194.1 U15.A6 Y4.1 | length 310.4
  TopLayer - S1 (.GTL) w4.75: Y4.1@1267.99,1674.23 1285.77,1674.23 1300,1660 1300,1530 1307.5,1522.5 1307.5,1414.98 U15.A6@1324.76,1397.72
NetC198_1: C198.1 U15.A4 Y4.4 | length 419.8
  TopLayer - S1 (.GTL) w4.75: Y4.4@1142.01,1674.23 1115,1674.23 1115,1595 C198.1@1123.88,1595 1151.38,1567.5 1215,1567.5 1277.5,1505 1277.5,1413.44 U15.A4@1261.77,1397.72
NetC201_1: C201.1 R100.1 U16.1 U16.2 | length 154
  TopLayer - S1 (.GTL) w6: U16.1@1560.04,1862.97 C201.1@1615,1862.97 ; U16.2@1560.04,1882.66 1592.74,1882.66 C201.1@1597.44,1877.95 ; R100.1@1611.22,1812.99 1615,1812.99 C201.1@1615,1861 C201.1@1615,1862.97 ; C201.1@1615,1868.88 C201.1@1615,1862.97
NetC204_1: C204.1 R126.2 R127.2 | length 94.1
  BottomLayer - S8 (.GBL) w4.75: R126.2@765,1125 765,1205 C204.1@775,1215
NetC210_1: C210.1 R136.1 R138.2 U20.1 | length 166.2
  BottomLayer - S8 (.GBL) w10: R138.2@225,1686.38 R138.2@225,1676.18 ; U20.1@255.63,1575.62 255.63,1593.37 225,1624 R138.2@225,1676.18 ; C210.1@264.76,1679.13 264.76,1676.18 R138.2@225,1676.18
NetC236_2: C236.2 L9.2 U22.4 | length 153.5
  TopLayer - S1 (.GTL) w11.81: U22.4@2663.58,3231 2663.58,3273.43 2653.54,3283.46 2653.54,3353.54 L9.2@2672.5,3372.5
NetC237_2: C237.2 L11.2 U22.9 | length 155
  TopLayer - S1 (.GTL) w11.81: L11.2@2532.5,3372.5 2551.18,3353.82 2551.18,3300.2 2565.16,3286.22 U22.9@2565.16,3231
NetC240_1: C240.1 U22.2 Y5.2 | length 239.9
  TopLayer - S1 (.GTL) w5.91: U22.2@2702.95,3231 2702.95,3190.75 v1(2712.6,3181.1)
  BottomLayer - S8 (.GBL) w5.91: v1(2712.6,3181.1) 2712.6,3143.72 C240.1@2706.38,3137.5 2694.88,3137.5 2694.88,3042.5 Y5.2@2728.21,3042.5
NetC241_1: C241.1 U22.3 Y5.1 | length 275.8
  TopLayer - S1 (.GTL) w5.91: v1(2673.23,3181.1) 2683.27,3191.14 U22.3@2683.27,3231
  BottomLayer - S8 (.GBL) w5.91: Y5.1@2566.79,3042.5 2566.79,3070.73 2581.69,3085.63 2635.83,3085.63 2648.62,3098.43 2648.62,3137.5 C241.1@2661.12,3137.5 2673.23,3149.61 v1(2673.23,3181.1)
NetC252_1: C252.1 C253.1 C254.1 L13.2 R166.1 U25.3 | length 234.2
  BottomLayer - S8 (.GBL) w5.91: R166.1@3176.12,1000 3185,1000 3185,1033 C252.1@3185,1037.01
  BottomLayer - S8 (.GBL) w9.84: U25.3@3047.2,1025.59 3087.59,1025.59 3095,1033 3185,1033 3224.12,1033 L13.2@3230,1038.88
NetC258_1: C258.1 R168.1 U25.1 Y6.1 | length 233.6
  BottomLayer - S8 (.GBL) w4.92: R168.1@2958.62,1122.5 C258.1@3000,1122.5 ; C258.1@3008.88,1122.5 C258.1@3000,1122.5 ; Y6.1@3018.21,1217.5 3000,1199.29 C258.1@3000,1122.5 ; U25.1@3047.2,1076.77 3020.73,1076.77 3000,1097.5 C258.1@3000,1122.5
NetC259_1: C259.1 R168.2 U25.14 Y6.2 | length 231.5
  BottomLayer - S8 (.GBL) w4.92: U25.14@2822.8,1076.77 2849.27,1076.77 2870,1097.5 C259.1@2870,1122.5 ; Y6.2@2856.79,1217.5 2870,1204.29 C259.1@2870,1122.5 ; C259.1@2861.12,1122.5 C259.1@2870,1122.5 ; R168.2@2911.38,1122.5 C259.1@2870,1122.5
NetD1_2: D1.2 J2.1 | length 315.9
  TopLayer - S1 (.GTL) w70.87: J2.1@356,3094 J2.1@356,3145 356,3228.5 395,3267.5 D1.2@521.26,3267.5
NetD2_1: D2.1 R3.1 | length 54.4
  TopLayer - S1 (.GTL) w9.84: D2.1@167.03,2875 R3.1@221.38,2875
NetD3_1: D3.1 R13.1 | length 54.4
  TopLayer - S1 (.GTL) w9.84: D3.1@167.03,2825 R13.1@221.38,2825
NetD4_1: D4.1 R25.1 | length 66.9
  TopLayer - S1 (.GTL) w6: v1(2550,1190) D4.1@2550,1220.47
  BottomLayer - S8 (.GBL) w6: v1(2550,1190) R25.1@2550,1226.38
NetD5_1: D5.1 R26.1 | length 66.9
  TopLayer - S1 (.GTL) w6: v1(2602.5,1190) D5.1@2602.5,1220.47
  BottomLayer - S8 (.GBL) w6: v1(2602.5,1190) R26.1@2602.5,1226.38
NetD6_1: D6.1 R27.1 | length 66.9
  TopLayer - S1 (.GTL) w6: v1(2655,1190) D6.1@2655,1220.47
  BottomLayer - S8 (.GBL) w6: v1(2655,1190) R27.1@2655,1226.38
NetD7_1: D7.1 R33.2 | length 66.9
  TopLayer - S1 (.GTL) w6: v1(2497.5,1190) D7.1@2497.5,1220.48
  BottomLayer - S8 (.GBL) w6: v1(2497.5,1190) R33.2@2497.5,1226.38
NetD9_1: D9.1 R52.1 | length 66.9
  TopLayer - S1 (.GTL) w6: v1(2550,92.5) D9.1@2550,122.97
  BottomLayer - S8 (.GBL) w6: v1(2550,92.5) R52.1@2550,128.88
NetD10_1: D10.1 R53.1 | length 66.9
  TopLayer - S1 (.GTL) w6: v1(2602.5,92.5) D10.1@2602.5,122.97
  BottomLayer - S8 (.GBL) w6: v1(2602.5,92.5) R53.1@2602.5,128.88
NetD11_1: D11.1 R54.1 | length 66.9
  TopLayer - S1 (.GTL) w6: v1(2655,92.5) D11.1@2655,122.97
  BottomLayer - S8 (.GBL) w6: v1(2655,92.5) R54.1@2655,128.88
NetD12_1: D12.1 R60.2 | length 66.9
  TopLayer - S1 (.GTL) w6: v1(2497.5,92.5) D12.1@2497.5,122.98
  BottomLayer - S8 (.GBL) w6: v1(2497.5,92.5) R60.2@2497.5,128.88
NetD14_1: D14.1 R66.1 | length 54.4
  TopLayer - S1 (.GTL) w9.84: D14.1@167.03,2775 R66.1@221.38,2775
NetL3_1: L3.1 U13.35 | length 26.7
  TopLayer - S1 (.GTL) w8: U13.35@709.17,2324.87 735.87,2324.87
NetL4_1: L4.1 U13.42 | length 114.2
  TopLayer - S1 (.GTL) w8: 592,2439 602.87,2428.13 602.87,2388 ; 596,2424 596,2394.87 602.87,2388 ; U13.42@602.87,2368.17 602.87,2388
NetL5_1: L5.1 U13.14 | length 62.7
  TopLayer - S1 (.GTL) w8: 517.76,2099 517.76,2117 524.13,2123.37 ; 524.13,2104.13 524.13,2123.37 ; U13.14@524.13,2139.83 524.13,2123.37
NetL12_2: L12.2 U22.50 | length 139.8
  TopLayer - S1 (.GTL) w11.81: U22.50@2793.5,2884.55 2835.63,2884.55 ; L12.2@2895,2880 L12.2@2910,2865
  TopLayer - S1 (.GTL) w15.75: 2835.63,2884.55 2895,2884.55 2895,2880 L12.2@2895,2867.5
NetR2_1: R2.1 R4.2 U1.12 | length 296.1
  TopLayer - S1 (.GTL) w10: R2.1@1081.38,2817.5 1081.38,2820.26 R4.2@1128.62,2867.5 1170,2867.5 1202.2,2899.7 U1.12@1202.2,3039.31
NetR5_2: R5.2 U1.7 | length 74.9
  TopLayer - S1 (.GTL) w12: R5.2@1143.62,3337.5 1151.02,3330.1 U1.7@1151.02,3265.69
NetR12_2: R12.2 U3.1 | length 156.6
  TopLayer - S1 (.GTL) w12: R12.2@2336.5,2296 v1(2373,2296) ; U3.1@2342.4,2387.61 2369.39,2387.61 v1(2373,2384)
  BottomLayer - S8 (.GBL) w12: v1(2373,2296) v1(2373,2384)
NetR14_2: R14.2 U3.8 | length 188
  TopLayer - S1 (.GTL) w15: U3.8@2272,2383.21 2272,2357 2285,2344 2420,2344 R14.2@2420,2352.38
NetR21_2: R21.2 U6.15 | length 70.8
  TopLayer - S1 (.GTL) w6: U6.15@2681,1750.45 R21.2@2751.83,1750.45
NetR22_1: R22.1 T1.24 | length 101.4
  TopLayer - S1 (.GTL) w12: v1(3663.58,1851.87) T1.24@3730.04,1851.87
  BottomLayer - S8 (.GBL) w12: v1(3663.58,1851.87) R22.1@3698.54,1851.87
NetR23_2: R23.2 U6.24 | length 104.6
  TopLayer - S1 (.GTL) w6: R23.2@2450,1936.38 2450,1905 2472.34,1882.66 U6.24@2472.34,1841
NetR24_1: R24.1 T1.21 | length 101.4
  TopLayer - S1 (.GTL) w12: v1(3663.58,1734.94) T1.21@3730.04,1734.94
  BottomLayer - S8 (.GBL) w12: v1(3663.58,1734.94) R24.1@3698.54,1734.94
NetR25_2: R25.2 U6.61 | length 133.5
  TopLayer - S1 (.GTL) w6: U6.61@2551.08,1404 2551.08,1344.59 2555.12,1340.55 v1(2555.12,1324.8)
  BottomLayer - S8 (.GBL) w6: R25.2@2550,1273.62 R25.2@2551.08,1273.62 ; R25.2@2555.12,1273.26 v1(2555.12,1324.8)
NetR26_2: R26.2 U6.62 | length 143.5
  TopLayer - S1 (.GTL) w6: U6.62@2570.77,1404 2570.77,1356.9 v1(2602.5,1325.17)
  BottomLayer - S8 (.GBL) w6: R26.2@2602.5,1273.62 v1(2602.5,1325.17)
NetR27_2: R27.2 U6.63 | length 171.2
  TopLayer - S1 (.GTL) w6: U6.63@2590.45,1404 2590.45,1365.55 2631,1325 v1(2655,1325)
  BottomLayer - S8 (.GBL) w6: R27.2@2655,1273.62 v1(2655,1325)
NetR30_1: R30.1 R33.1 R34.2 U6.51 | length 262.5
  TopLayer - S1 (.GTL) w4.75: U6.51@2353.98,1404 U6.51@2353.98,1407
  TopLayer - S1 (.GTL) w5.91: U6.51@2354.23,1404 2354.23,1364.27 v1(2374.02,1344.49)
  BottomLayer - S8 (.GBL) w5.91: v1(2374.02,1344.49) 2393.42,1325.08 R34.2@2422.5,1325.08
  BottomLayer - S8 (.GBL) w6: R30.1@2422.5,1273.62 2422.5,1283.46 2497.5,1283.46 R33.1@2497.5,1273.62 ; R30.1@2422.5,1284.5 R34.2@2422.5,1325.08
NetR32_1: R32.1 T1.18 | length 101.4
  TopLayer - S1 (.GTL) w12: v1(3663.58,1618.01) T1.18@3730.04,1618.01
  BottomLayer - S8 (.GBL) w12: v1(3663.58,1618.01) R32.1@3698.54,1618.01
NetR35_1: R35.1 U6.22 | length 100.2
  TopLayer - S1 (.GTL) w6: R35.1@2500,1936.38 2505,1931.38 2505,1910 2511.71,1903.29 U6.22@2511.71,1841
NetR37_1: R37.1 T1.15 | length 101.4
  TopLayer - S1 (.GTL) w12: v1(3663.58,1501.08) T1.15@3730.04,1501.08
  BottomLayer - S8 (.GBL) w12: v1(3663.58,1501.08) R37.1@3698.54,1501.08
NetR41_2: R41.2 U12.15 | length 80.8
  TopLayer - S1 (.GTL) w6: U12.15@2681,652.95 2751.83,652.95 R41.2@2758.88,660
NetR42_1: R42.1 T2.24 | length 101.4
  TopLayer - S1 (.GTL) w12: v1(3663.58,759.37) T2.24@3730.04,759.37
  BottomLayer - S8 (.GBL) w12: v1(3663.58,759.37) R42.1@3698.54,759.37
NetR45_2: R45.2 U12.24 | length 79
  TopLayer - S1 (.GTL) w4.75: R45.2@2457.5,816.38 2465,808.88 2465,791 2472.34,783.66 U12.24@2472.34,743.5
NetR48_1: R48.1 T2.21 | length 101.4
  TopLayer - S1 (.GTL) w12: v1(3663.58,642.44) T2.21@3730.04,642.44
  BottomLayer - S8 (.GBL) w12: v1(3663.58,642.44) R48.1@3698.54,642.44
NetR49_1: R49.1 R57.1 U12.48 | length 132
  TopLayer - S1 (.GTL) w6: v1(2215.36,355.64) 2215.36,377.36 U12.48@2244,377.36
  BottomLayer - S8 (.GBL) w5.91: v1(2215.36,355.64) 2215.36,285 R49.1@2226.38,285
NetR52_2: R52.2 U12.61 | length 131.5
  TopLayer - S1 (.GTL) w6: v1(2551.08,227.67) U12.61@2551.08,306.5
  BottomLayer - S8 (.GBL) w6: R52.2@2550,176.12 2551.08,176.12 v1(2551.08,227.67)
NetR53_2: R53.2 U12.62 | length 143.5
  TopLayer - S1 (.GTL) w6: U12.62@2570.77,306.5 2570.77,259.4 v1(2602.5,227.67)
  BottomLayer - S8 (.GBL) w6: R53.2@2602.5,176.12 v1(2602.5,227.67)
NetR54_2: R54.2 U12.63 | length 171.2
  TopLayer - S1 (.GTL) w6: U12.63@2590.45,306.5 2590.45,268.05 2631,227.5 v1(2655,227.5)
  BottomLayer - S8 (.GBL) w6: R54.2@2655,176.12 v1(2655,227.5)
NetR58_1: R58.1 T2.18 | length 101.4
  TopLayer - S1 (.GTL) w12: v1(3663.58,525.51) T2.18@3730.04,525.51
  BottomLayer - S8 (.GBL) w12: v1(3663.58,525.51) R58.1@3698.54,525.51
NetR59_1: R59.1 R60.1 R62.2 U12.51 | length 262
  TopLayer - S1 (.GTL) w4.75: U12.51@2353.98,306.5 U12.51@2353.98,309.5
  TopLayer - S1 (.GTL) w5.91: U12.51@2354.23,306.5 2354.23,267.82 v1(2372.05,250)
  BottomLayer - S8 (.GBL) w5.91: v1(2372.05,250) 2394.46,227.58 R62.2@2422.5,227.58
  BottomLayer - S8 (.GBL) w6: R59.1@2422.5,176.12 2422.5,186.02 2497.5,186.02 R60.1@2497.5,176.12 ; R59.1@2422.5,187 R62.2@2422.5,227.58
NetR63_2: R63.2 R172.2 R173.1 U12.19 | length 266.3
  TopLayer - S1 (.GTL) w5.91: R63.2@2512.5,913.88 R172.2@2597.5,913.88 2597.5,827.5 2571.17,801.17 U12.19@2571.17,743.5
NetR64_1: R64.1 T2.15 | length 101.4
  TopLayer - S1 (.GTL) w12: v1(3663.58,408.58) T2.15@3730.04,408.58
  BottomLayer - S8 (.GBL) w12: v1(3663.58,408.58) R64.1@3698.54,408.58
NetR68_2: R68.2 U15.B4 | length 197.3
  TopLayer - S1 (.GTL) w4.75: R68.2@1171.12,1507.5 1202.15,1507.5 1246.03,1463.61 1246.03,1407.48 1246.04,1381.48 1261.28,1366.24 U15.B4@1261.77,1366.22
NetR72_1: R72.1 R73.1 U15.M18 | length 178.7
  TopLayer - S1 (.GTL) w4.92: U15.M18@1702.72,1051.26 1749.24,1051.26 1760.5,1040 v2(1820.66,1040) R73.1@1851.04,1040
  BottomLayer - S8 (.GBL) w4.92: v2(1820.66,1040) R72.1@1846.38,1040
NetR74_1: R74.1 R75.1 R76.1 U15.M17 | length 300.1
  TopLayer - S1 (.GTL) w4.92: U15.M17@1670.13,1052.2 1685.9,1036.43 1733.82,1036.43 1777.75,992.5 v2(1820.66,992.5) R74.1@1851.04,992.5
  BottomLayer - S8 (.GBL) w4.92: v2(1820.66,992.5) R75.1@1839.5,992.5 ; R75.1@1846.38,992.5 R75.1@1839.5,992.5 ; R76.1@1851.38,955 1839.5,955 R75.1@1839.5,992.5 ; R75.1@1851.38,1000 1839.5,1000 R75.1@1839.5,992.5
NetR99_2: R99.2 U15.J3 | length 124.3
  TopLayer - S1 (.GTL) w4.75: v2(1214.53,1161.5) U15.J3@1230.28,1145.77
  BottomLayer - S8 (.GBL) w6: R99.2@1115,1167.5 1162.5,1167.5 1168.5,1161.5 v2(1214.53,1161.5)
NetR100_2: R100.2 U16.3 | length 146.6
  TopLayer - S1 (.GTL) w6: U16.3@1560.04,1902.34 1538.17,1902.34 1531.5,1895.67 1531.5,1818.9 1540.39,1810 R100.2@1566.38,1810
NetR132_2: R132.2 U17.L8 | length 135.6
  TopLayer - S1 (.GTL) w4.75: v2(385,1195) 385,1196.19 399.13,1210.32 399.13,1214.91 407.85,1223.63 430.62,1223.63 U17.L8@445.51,1208.74
  BottomLayer - S8 (.GBL) w4.75: R132.2@334,1188.5 361,1188.5 367.5,1195 v2(385,1195)
NetR135_1: R135.1 TP1.1 U20.9 | length 249.1
  MidLayer5 - S6 (.G5) w6: v2(275.31,1311.19) v2(275.31,1418)
  BottomLayer - S8 (.GBL) w6: TP1.1@247.5,1257.5 275.31,1285.31 v2(275.31,1311.19) ; R135.1@271.12,1390 275.31,1394.19 v2(275.31,1418) U20.9@275.31,1465.38
NetR139_1: R139.1 U22.16 | length 223.3
  TopLayer - S1 (.GTL) w5.91: R139.1@2236.5,3267.5 2420.49,3267.5 2427.36,3260.63 U22.16@2427.36,3231
NetR140_1: R140.1 U22.17 | length 140.7
  TopLayer - S1 (.GTL) w5.91: R140.1@2236.5,3210 2277.2,3210 2327.07,3160.14 U22.17@2356.5,3160.14
NetR141_1: R141.1 U22.18 | length 125
  TopLayer - S1 (.GTL) w5.91: R141.1@2236.5,3152.5 2302.22,3152.5 2314.27,3140.45 U22.18@2356.5,3140.45
NetR142_1: R142.1 U22.19 | length 130.7
  TopLayer - S1 (.GTL) w5.91: R142.1@2236.5,3095 2287.91,3095 2313.68,3120.77 U22.19@2356.5,3120.77
NetR143_1: R143.1 U22.21 | length 138.2
  TopLayer - S1 (.GTL) w5.91: R143.1@2236.5,3037.5 2271.75,3037.5 2315.65,3081.4 U22.21@2356.5,3081.4
NetR144_1: R144.1 U22.23 | length 145.7
  TopLayer - S1 (.GTL) w5.91: R144.1@2236.5,2980 2247.64,2991.14 2266.73,2991.14 2317.62,3042.03 U22.23@2356.5,3042.03
NetR145_1: R145.1 U22.26 | length 145
  TopLayer - S1 (.GTL) w5.91: R145.1@2236.5,2922.5 2251.99,2937.99 2272.64,2937.99 2317.62,2982.97 U22.26@2356.5,2982.97
NetR147_1: R147.1 U22.30 | length 136.3
  TopLayer - S1 (.GTL) w5.91: R147.1@2236.5,2865 2246.5,2875 2271.65,2875 2300.89,2904.23 U22.30@2356.5,2904.23
NetR148_1: R148.1 U22.63 U23.5 | length 176.3
  TopLayer - S1 (.GTL) w5.91: U22.63@2793.5,3140.45 2795.77,3142.72 2830.71,3142.72 2854.33,3166.34 v1(2854.33,3183.07) 2893.31,3183.07 R148.1@2893.88,3182.5
  BottomLayer - S8 (.GBL) w5.91: v1(2854.33,3183.07) 2894.68,3183.07 U23.5@2900.26,3177.5
NetR149_1: R149.1 U22.62 U23.4 | length 154.4
  TopLayer - S1 (.GTL) w5.91: U22.62@2793.5,3120.77 2835.33,3120.77 v1(2854.33,3139.76) 2893.64,3139.76 R149.1@2893.88,3140
  BottomLayer - S8 (.GBL) w5.91: v1(2854.33,3139.76) 2899.92,3139.76 U23.4@2900.26,3140.1
NetR150_1: R150.1 R154.1 U23.1 | length 233.5
  TopLayer - S1 (.GTL) w5.91: R154.1@2941.12,3097.5 2948.94,3105.31 3015.75,3105.31 3033.46,3123.03 v1(3033.46,3214.9)
  BottomLayer - S8 (.GBL) w5.91: U23.1@2994.74,3214.9 v1(3033.46,3214.9)
NetR154_2: R154.2 U22.61 U23.3 | length 258.4
  TopLayer - S1 (.GTL) w5.91: U22.61@2793.5,3101.08 v1(2854.33,3101.08) 2890.3,3101.08 R154.2@2893.88,3097.5
  BottomLayer - S8 (.GBL) w5.91: v1(2854.33,3101.08) 2935.73,3101.08 2965.55,3130.91 2985.55,3130.91 U23.3@2994.74,3140.1
NetR155_1: R155.1 R158.2 U22.59 | length 161.7
  TopLayer - S1 (.GTL) w5.91: U22.59@2793.5,3061.71 2832.97,3061.71 2847.18,3047.5 R158.2@2880.91,3047.5 ; R155.1@2893.88,3005 2880.91,3005 R158.2@2880.91,3047.5 ; R158.2@2893.88,3047.5 R158.2@2880.91,3047.5
NetR156_1: R156.1 U22.14 | length 86.9
  TopLayer - S1 (.GTL) w5.91: v1(2466.73,3179.92) U22.14@2466.73,3231
  BottomLayer - S8 (.GBL) w5.91: R156.1@2430.91,3179.92 v1(2466.73,3179.92)
NetR157_2: R157.2 U22.6 | length 96.7
  TopLayer - S1 (.GTL) w11.81: U22.6@2624.21,3231 v1(2624.21,3287.6)
  BottomLayer - S8 (.GBL) w11.81: v1(2624.21,3287.6) 2636.38,3275.43 R157.2@2636.38,3252.5
NetR166_2: R166.2 U25.4 | length 78.7
  BottomLayer - S8 (.GBL) w5.91: U25.4@3047.2,1000 3118.88,1000 R166.2@3123.88,995
NetR167_1: R167.1 U25.8 | length 78.2
  BottomLayer - S8 (.GBL) w4.92: R167.1@2751.12,907.5 2781.52,907.5 2797.24,923.23 U25.8@2822.8,923.23
NetR170_2: R170.2 R171.1 U6.19 | length 206.6
  TopLayer - S1 (.GTL) w5.91: R171.1@2552.5,1983.88 2552.5,1971.5 R170.2@2595,1971.5 ; U6.19@2571.85,1842.09 2572.5,1842.09 2572.5,1920.5 2595,1943 R170.2@2595,1971.5 ; R170.2@2595,1983.88 R170.2@2595,1971.5
NetR174_1: R174.1 R175.1 U15.V10 | length 262.3
  TopLayer - S1 (.GTL) w4.75: R174.1@1408.62,697.5 v1(1440,697.5) 1440,765.2 1457.13,782.33 1457.13,841.87 1450.75,848.25 U15.V10@1450.75,862.28
  BottomLayer - S8 (.GBL) w4.75: v1(1440,697.5) 1491.38,697.5 R175.1@1491.38,692.5
NetR182_1: R182.1 U25.11 | length 74.8
  BottomLayer - S8 (.GBL) w4.92: R182.1@2751.12,992.5 2758.62,1000 U25.11@2822.8,1000
NetR183_1: R183.1 U25.9 | length 72.2
  BottomLayer - S8 (.GBL) w4.92: R183.1@2751.12,950 2752.3,948.82 U25.9@2822.8,948.82
PHY1_CLKOUT: R35.2 R63.1 | length 1153.3
  TopLayer - S1 (.GTL) w5.91: R63.1@2512.5,961.12 v1(2512.5,1000)
  TopLayer - S1 (.GTL) w6: R35.2@2500,1983.62 v1(2500,2019.5)
  MidLayer2 - S3 (.G2) w4.68: v1(2500,2019.5) 2561.5,1958 2561.5,1363.5 2577.5,1347.5 2577.5,1065 v1(2512.5,1000)
PHY1_EARTH: C33.2 C34.1 J4.9 J4.10 J4.11 J4.12 U8.3 U8.8 U10.3 U10.8 | length 123.5
  TopLayer - S1 (.GTL) w12: U10.8@3843.27,1502.5 U10.3@3876.73,1502.5 v1(3905,1502.5) ; U8.8@3843.27,1737.5 U8.3@3876.73,1737.5 v1(3905,1737.5)
PHY1_INTPWDN: R29.2 U6.60 U15.G18 | length 996.1
  TopLayer - S1 (.GTL) w4.75: U15.G18@1702.72,1208.74 1735.31,1208.74 1782.48,1255.91 2205.71,1255.91 v2(2226.38,1276.57) ; v1(2531.75,1355.5) U6.60@2531.75,1408.1
  MidLayer5 - S6 (.G5) w5.91: v2@2225.39,1278.54 2354.33,1278.54 2450.79,1375 2512.25,1375 v1(2531.75,1355.5)
  BottomLayer - S8 (.GBL) w5.91: v1(2531.75,1355.5) 2542.39,1366.14 2557.26,1366.14 R29.2@2562.5,1371.38
PHY1_RX1588: U6.49 U15.C15 | length 785.9
  TopLayer - S1 (.GTL) w4.75: U15.C15@1608.23,1334.72 v2(1623.98,1350.47) v2(1623.98,1350.47)
  TopLayer - S1 (.GTL) w4.92: v1(2292.32,1375.98) 2314.86,1375.98 U6.49@2314.86,1404 ; U6.49@2314.73,1404 U6.49@2314.73,1407
  MidLayer5 - S6 (.G5) w5.91: v2(1623.98,1350.47) 1654,1380.5 1716.5,1380.5 v2(1749.5,1413.5)
  BottomLayer - S8 (.GBL) w5.91: v2(1749.5,1413.5) 1787.02,1375.98 v1(2292.32,1375.98)
PHY1_TD_A_N: C262.2 T1.11 U6.3 U9.2 U9.9 | length 458.1
  TopLayer - S1 (.GTL) w3.98: U6.3@2651.27,1514.23 U6.3@2681,1514.23 2718.44,1514.23 2722.28,1510.39 2737.58,1510.39 2747.49,1500.49 2754.1,1500.49 2760.11,1506.5 2799.97,1506.5 2830,1476.47 2859.1,1476.47 2862.94,1480.31 U9.9@2875.77,1480.31 U9.2@2909.23,1480.31 2922.06,1480.31 2925.9,1476.47 2945,1476.47 2972.85,1448.62 2989.59,1448.62 2993.19,1452.21 3025.07,1452.21 T1.11@3034.96,1462.11
  TopLayer - S1 (.GTL) w5.91: v2(2636,1516.5) U6.3@2651.27,1514.23
  BottomLayer - S8 (.GBL) w5.91: v2(2636,1516.5) C262.2@2654,1516.5
PHY1_TD_A_P: C261.2 T1.12 U6.2 U9.1 U9.10 | length 458
  TopLayer - S1 (.GTL) w3.98: U6.2@2651.27,1494.55 U6.2@2681,1494.55 2718.44,1494.55 2722.28,1498.39 2732.61,1498.39 2742.51,1488.49 2759.07,1488.49 2765.08,1494.5 2795,1494.5 2825.03,1464.47 2859.1,1464.47 2862.94,1460.63 U9.10@2875.77,1460.63 U9.1@2909.23,1460.63 2922.06,1460.63 2925.9,1464.47 2940.03,1464.47 2967.88,1436.62 2989.59,1436.62 2993,1433.21 3024.88,1433.21 T1.12@3034.96,1423.13
  TopLayer - S1 (.GTL) w5.91: v2(2636,1492.5) U6.2@2651.27,1494.55
  BottomLayer - S8 (.GBL) w5.91: v2(2636,1492.5) C261.2@2654,1492.5
PHY1_TD_B_N: C264.2 T1.8 U6.6 U9.5 U9.6 | length 457.7
  TopLayer - S1 (.GTL) w3.98: U6.6@2651.27,1573.29 U6.6@2681,1573.29 2718.44,1573.29 2722.28,1569.44 2731.5,1569.44 2736.06,1574 2811.5,1574 2849.97,1535.53 2859.1,1535.53 2862.94,1539.37 U9.6@2875.77,1539.37 U9.5@2909.23,1539.37 2922.06,1539.37 2925.9,1535.53 2940,1535.53 2970.02,1565.55 2989.59,1565.55 2993.19,1569.14 3025.07,1569.14 T1.8@3034.96,1579.04
  TopLayer - S1 (.GTL) w5.91: v2(2636,1575.56) U6.6@2651.27,1573.29
  BottomLayer - S8 (.GBL) w5.91: v2(2636,1575.56) C264.2@2654,1575.56
PHY1_TD_B_P: C263.2 T1.9 U6.5 U9.4 U9.7 | length 457.7
  TopLayer - S1 (.GTL) w3.98: U6.5@2651.27,1553.6 U6.5@2681,1553.6 2718.44,1553.6 2722.28,1557.44 2736.47,1557.44 2741.03,1562 2806.53,1562 2845,1523.53 2859.1,1523.53 2862.94,1519.68 U9.7@2875.77,1519.68 U9.4@2909.23,1519.68 2922.06,1519.68 2925.9,1523.53 2944.97,1523.53 2974.99,1553.55 2989.59,1553.55 2993,1550.14 3024.88,1550.14 T1.9@3034.96,1540.06
  TopLayer - S1 (.GTL) w5.91: v2(2636,1551.56) U6.5@2651.27,1553.6
  BottomLayer - S8 (.GBL) w5.91: v2(2636,1551.56) C263.2@2654,1551.56
PHY1_TD_C_N: C266.2 T1.5 U6.11 U7.2 U7.9 | length 457.6
  TopLayer - S1 (.GTL) w3.98: U6.11@2651.27,1671.71 U6.11@2681,1671.71 2718.44,1671.71 2722.28,1667.87 2802.24,1667.87 2845.85,1711.47 2859.1,1711.47 2862.94,1715.31 U7.9@2875.76,1715.31 U7.2@2909.23,1715.31 2922.06,1715.31 2925.9,1711.47 2944.5,1711.47 2973.49,1682.48 2989.59,1682.48 2993.19,1686.07 3025.07,1686.07 T1.5@3034.96,1695.96
  TopLayer - S1 (.GTL) w5.91: v2(2636,1673.98) U6.11@2651.27,1671.71
  BottomLayer - S8 (.GBL) w5.91: v2(2636,1673.98) C266.2@2654,1673.98
PHY1_TD_C_P: C265.2 T1.6 U6.10 U7.1 U7.10 | length 457.2
  TopLayer - S1 (.GTL) w3.98: U6.10@2651.27,1652.03 U6.10@2681,1652.03 2718.44,1652.03 2721.84,1655.43 2807.4,1655.43 2851,1699.03 2859.54,1699.03 2862.94,1695.63 U7.10@2875.76,1695.63 U7.1@2909.23,1695.63 2922.06,1695.63 2925.9,1699.47 2939.53,1699.47 2968.52,1670.48 2989.59,1670.48 2993,1667.07 3024.88,1667.07 T1.6@3034.96,1656.99
  TopLayer - S1 (.GTL) w5.91: v2(2636,1649.98) U6.10@2651.27,1652.03
  BottomLayer - S8 (.GBL) w5.91: v2(2636,1649.98) C265.2@2654,1649.98
PHY1_TD_D_N: C268.2 T1.2 U6.14 U7.5 U7.6 | length 457.5
  TopLayer - S1 (.GTL) w3.98: U6.14@2651.27,1730.77 U6.14@2681,1730.77 2718.44,1730.77 2722.28,1726.93 2776.93,1726.93 2820.53,1770.53 2859.1,1770.53 2862.94,1774.37 U7.6@2875.76,1774.37 U7.5@2909.23,1774.37 2922.06,1774.37 2925.9,1770.53 2940.03,1770.53 2968.91,1799.41 2989.59,1799.41 2993.19,1803 3025.07,1803 T1.2@3034.96,1812.89
  TopLayer - S1 (.GTL) w5.91: v2(2636,1733.04) U6.14@2651.27,1730.77
  BottomLayer - S8 (.GBL) w5.91: v2(2636,1733.04) C268.2@2654,1733.04
PHY1_TD_D_P: C267.2 T1.3 U6.13 U7.4 U7.7 | length 457.5
  TopLayer - S1 (.GTL) w3.98: U6.13@2651.27,1711.08 U6.13@2681,1711.08 2718.44,1711.08 2722.28,1714.93 2781.9,1714.93 2825.5,1758.53 2859.1,1758.53 2862.94,1754.68 U7.7@2875.76,1754.68 U7.4@2909.23,1754.68 2922.06,1754.68 2925.9,1758.53 2945,1758.53 2973.88,1787.41 2989.59,1787.41 2993,1784 3024.88,1784 T1.3@3034.96,1773.92
  TopLayer - S1 (.GTL) w5.91: v2(2636,1709.04) U6.13@2651.27,1711.08
  BottomLayer - S8 (.GBL) w5.91: v2(2636,1709.04) C267.2@2654,1709.04
PHY1_TX1588: R28.2 R31.2 U6.50 U15.C18 | length 823.1
  TopLayer - S1 (.GTL) w4.72: U15.C18@1702.72,1334.72 1724.99,1357 v2(1816,1357)
  TopLayer - S1 (.GTL) w5.91: v1(2314.96,1344.49) 2334.55,1364.07 U6.50@2334.55,1404
  BottomLayer - S8 (.GBL) w5.91: v2(1816,1357) 2302.45,1357 v1(2314.96,1344.49) 2314.96,1292.32 2322.78,1284.5 2360.24,1284.5
  BottomLayer - S8 (.GBL) w6: 2360.24,1284.5 2377.5,1284.5 R28.2@2377.5,1273.62
PHY1_X_A_N: J4.2 T1.14 U10.2 U10.9 | length 512.3
  TopLayer - S1 (.GTL) w3.98: T1.14@3730.04,1462.11 3740.12,1452.02 3772,1452.02 3775.28,1448.74 3783.1,1448.74 3813.55,1479.19 3826.83,1479.19 3830.45,1482.81 U10.9@3843.27,1482.81 U10.2@3876.73,1482.81 3889.56,1482.81 3893.17,1479.2 3914.8,1479.2 3915.43,1479.19 3983.12,1411.5 4013.5,1411.5 4086,1484 4086,1489 4078,1497 4056,1497 J4.2@4020.01,1482.48
PHY1_X_A_P: J4.1 T1.13 U10.1 U10.10 | length 514.6
  TopLayer - S1 (.GTL) w3.98: T1.13@3730.04,1423.13 3739.93,1433.02 3771.81,1433.02 3775.09,1436.3 3788.27,1436.3 3818.71,1466.74 3826.83,1466.74 3830.44,1463.13 U10.10@3843.27,1463.13 U10.1@3876.73,1463.13 3889.55,1463.13 3893.17,1466.75 3910.28,1466.75 3977.97,1399.06 4018.65,1399.06 4098.59,1479 4113,1479 4120.01,1471.99 J4.1@4120.01,1432.48
PHY1_X_B_N: J4.6 T1.17 U10.5 U10.6 | length 509.8
  TopLayer - S1 (.GTL) w3.98: T1.17@3730.04,1579.04 3740.12,1568.95 3772,1568.95 3775.28,1565.67 3792.34,1565.67 3819.77,1538.25 3826.83,1538.25 3830.45,1541.87 U10.6@3843.27,1541.87 U10.5@3876.73,1541.87 3889.56,1541.87 3893.17,1538.26 3932.83,1538.26 v1(3944.59,1550.03)
  MidLayer2 - S3 (.G2) w3.98: v1(3944.59,1550.03) 3956.46,1538.16 ; 3971.15,1538.16 4038.16,1538.16 ; J4.6@4020.01,1682.48 4062.5,1640 4062.5,1593.9
  MidLayer2 - S3 (.G2) w4: 3956.46,1538.16 3971.15,1538.16 ; 4038.16,1538.16 4062.5,1562.5 4062.5,1593.9
PHY1_X_B_P: J4.3 T1.16 U10.4 U10.7 | length 515.3
  TopLayer - S1 (.GTL) w3.98: T1.16@3730.04,1540.06 3739.93,1549.95 3771.81,1549.95 3775.09,1553.23 3787.18,1553.23 3814.61,1525.8 3826.83,1525.8 3830.44,1522.18 U10.7@3843.27,1522.18 U10.4@3876.73,1522.18 3889.55,1522.18 3893.17,1525.81 3932.81,1525.81 v1(3944.59,1514.03)
  MidLayer2 - S3 (.G2) w3.98: v1(3944.59,1514.03) 3956.47,1525.91 4043.24,1525.91 4074.76,1557.42 4074.76,1593.26 4079,1597.5 4086,1597.5 4090,1593.5 4090,1562.5 J4.3@4120.01,1532.48
PHY1_X_C_N: J4.5 T1.20 U8.2 U8.9 | length 517
  TopLayer - S1 (.GTL) w3.98: T1.20@3730.04,1695.96 3740.12,1685.88 3772,1685.88 3775.28,1682.6 3783.84,1682.6 3815.21,1713.97 3826.6,1713.97 ; 3823.82,1714.19 3826.83,1714.19 3830.45,1717.81 U8.9@3843.27,1717.81 U8.2@3876.73,1717.81 3889.56,1717.81 3893.17,1714.2 3924.77,1714.2 ; 3924.78,1714.19 3925.4,1714.19 3941.94,1697.65 3941.94,1649.03 3951.47,1639.5 4043.59,1639.5 4087.59,1595.5 4104.5,1595.5 4108.53,1599.53 J4.5@4120.01,1632.48
PHY1_X_C_P: J4.4 T1.19 U8.1 U8.10 | length 512.4
  TopLayer - S1 (.GTL) w3.98: T1.19@3730.04,1656.99 3739.93,1666.88 3771.81,1666.88 3775.09,1670.16 3788.78,1670.16 3820.36,1701.74 3826.83,1701.74 3830.44,1698.13 U8.10@3843.27,1698.13 U8.1@3876.73,1698.13 3889.55,1698.13 3893.17,1701.75 3920.25,1701.75 3929.5,1692.5 3929.5,1643.88 3946.32,1627.06 4038.44,1627.06 4075.5,1590 4075.5,1581.5 4064.5,1570.5 4053.5,1570.5 J4.4@4020.01,1582.48
PHY1_X_D_N: J4.8 T1.23 U8.5 U8.6 | length 515
  TopLayer - S1 (.GTL) w3.98: T1.23@3730.04,1812.89 3740.12,1802.81 3772,1802.81 3775.28,1799.53 3793.5,1799.53 3819.78,1773.25 3826.83,1773.25 3830.45,1776.87 U8.6@3843.27,1776.87 U8.5@3876.73,1776.87 3889.56,1776.87 3893.17,1773.26 3928.74,1773.26 3929.38,1773.25 3965.62,1737 4040,1737 4092,1789 4092,1801 4085.5,1807.5 4045.03,1807.5 J4.8@4020.01,1782.48
PHY1_X_D_P: J4.7 T1.22 U8.4 U8.7 | length 511.8
  TopLayer - S1 (.GTL) w3.98: T1.22@3730.04,1773.92 3739.93,1783.81 3771.81,1783.81 3775.09,1787.09 3788.34,1787.09 3814.63,1760.81 3815.25,1760.81 3826.83,1760.8 3830.44,1757.18 U8.7@3843.27,1757.18 U8.4@3876.73,1757.18 3889.55,1757.18 3893.17,1760.81 3924.22,1760.81 3960.47,1724.56 4045.15,1724.56 4105.59,1785 4125,1785 4132,1778 4132,1766.5 J4.7@4120.01,1732.48
PHY2_EARTH: C59.2 C62.1 J5.9 J5.10 J5.11 J5.12
PHY2_INTPWDN: R55.2 U12.60 U15.V13 | length 1600.2
  TopLayer - S1 (.GTL) w4.75: v1(2531.75,258) U12.60@2531.75,310.6
  TopLayer - S1 (.GTL) w5: U15.V13@1545.24,862.28 1545.24,751.02 v2(1592.52,703.74)
  MidLayer5 - S6 (.G5) w4.68: v2(1592.52,703.74) 1592.52,588.98 1592.52,499.02 1913.54,178 2003.5,178 ; 2006.89,178 2003.5,178 ; v1(2531.75,258) 2509.24,280.51 2453.74,280.51 2351.23,178 2003.5,178
  BottomLayer - S8 (.GBL) w5.91: v1(2531.75,258) 2542.39,268.64 2557.26,268.64 R55.2@2562.5,273.88
PHY2_RX1588: U12.49 U15.U13 | length 1344.3
  TopLayer - S1 (.GTL) w4.75: U12.49@2314.73,306.5 U12.49@2314.73,309.5
  TopLayer - S1 (.GTL) w5: U15.U13@1545.24,893.78 v2(1560.97,878.04)
  TopLayer - S1 (.GTL) w5.91: v1(2298.23,248.03) 2314.86,264.67 U12.49@2314.86,306.5
  MidLayer5 - S6 (.G5) w4.68: v2(1560.97,878.04) 1560.97,787.53 1581.5,767 1596.5,767 1612.5,751 1612.5,695.5 1612.5,564.67 1988.19,188.98 2046.52,188.98 2294.98,188.98 2310.5,204.5 2310.5,238.71 v1@2299.21,250
PHY2_TD_A_N: C272.2 D13.6 T2.11 U12.3 | length 532.1
  TopLayer - S1 (.GTL) w3.98: U12.3@2651.27,416.73 U12.3@2681,416.73 2718.43,416.73 2722.05,413.11 2778.01,413.11 2796.96,394.17 2796.96,367.51 2808.13,356.34 2883.22,356.34 v1(2895,368.12) 2906.78,356.34 2989.81,356.34 2993.19,359.71 3025.07,359.71 T2.11@3034.96,369.61
  TopLayer - S1 (.GTL) w5.91: v2(2636,419) U12.3@2651.27,416.73
  BottomLayer - S8 (.GBL) w5.91: v2(2636,419) C272.2@2654,419
  BottomLayer - S8 (.GBL) w9.84: v1(2895,368.12) 2905.03,378.15 2942.24,378.15 D13.6@2942.24,370.41
PHY2_TD_A_P: C271.2 D13.1 T2.12 U12.2 | length 536.2
  TopLayer - S1 (.GTL) w3.98: U12.2@2651.27,397.05 U12.2@2681,397.05 2718.43,397.05 2722.05,400.67 2772.86,400.67 2784.51,389.01 2784.51,362.36 2802.98,343.9 2883.22,343.9 v1(2895,332.12) 2906.87,343.99 2989.72,343.99 2993,340.71 3024.88,340.71 T2.12@3034.96,330.63
  TopLayer - S1 (.GTL) w5.91: v2(2636,395) U12.2@2651.27,397.05
  BottomLayer - S8 (.GBL) w5.91: v2(2636,395) C271.2@2654,395
  BottomLayer - S8 (.GBL) w9.84: D13.1@2847.76,370.41 2856.7,370.41 v1(2895,332.12)
PHY2_TD_B_N: C274.2 D13.4 T2.8 U12.6 | length 536
  TopLayer - S1 (.GTL) w3.98: U12.6@2651.27,475.79 U12.6@2681,475.79 2718.43,475.79 2722.05,472.17 2731.28,472.17 2747.56,488.44 2752.56,488.44 ccw(c2752.56,489.44) 2753.56,489.44 cw(c2754.56,489.44) 2755.56,489.44 ccw(c2756.56,489.44) 2756.56,488.44 2800.56,488.44 2832.56,456.44 2837.56,456.44 ccw(c2837.56,456.69) 2837.81,456.69 cw(c2838.06,456.69) 2838.31,456.69 ccw(c2838.56,456.69) 2838.56,456.44 2854.16,456.44 2870.99,473.27 2875.99,473.27 ccw(c2875.99,473.39) 2876.11,473.39 cw(c2876.24,473.39) 2876.36,473.39 ccw(c2876.49,473.39) 2876.49,473.27 2883.22,473.27 v1(2895,485.05) 2906.77,473.28 2911.77,473.28 ccw(c2911.77,476.9) 2915.39,476.9 cw(c2919.02,476.9) 2922.64,476.9 ccw(c2926.27,476.9) 2926.27,473.28 2989.83,473.28 2993.19,476.64 3025.07,476.64 T2.8@3034.96,486.54
  TopLayer - S1 (.GTL) w5.91: v2(2636,478.06) U12.6@2651.27,475.79
  BottomLayer - S8 (.GBL) w5.91: v2(2636,478.06) C274.2@2654,478.06
  BottomLayer - S8 (.GBL) w9.84: v1(2895,485.05) 2934.83,445.22 D13.4@2942.24,445.22
PHY2_TD_B_P: C273.2 D13.3 T2.9 U12.5 | length 536
  TopLayer - S1 (.GTL) w3.98: U12.5@2651.27,456.1 U12.5@2681,456.1 2718.43,456.1 2722.05,459.72 2727.05,459.72 ccw(c2727.05,460.1) 2727.42,460.1 cw(c2727.8,460.1) 2728.17,460.1 ccw(c2728.55,460.1) 2728.55,459.72 2736.43,459.72 2752.71,476 2757.71,476 ccw(c2757.71,477.25) 2758.96,477.25 cw(c2760.21,477.25) 2761.46,477.25 ccw(c2762.71,477.25) 2762.71,476 2795.41,476 2827.41,444 2832.41,444 ccw(c2832.41,444.12) 2832.53,444.12 cw(c2832.66,444.12) 2832.78,444.12 ccw(c2832.91,444.12) 2832.91,444 2859.32,444 2876.14,460.83 2883.22,460.83 v1(2895,449.05) 2906.78,460.83 2911.78,460.83 cw(c2911.78,455.95) 2916.65,455.95 ccw(c2921.53,455.95) 2926.4,455.95 cw(c2931.28,455.95) 2931.28,460.83 2989.81,460.83 2993,457.64 3024.88,457.64 T2.9@3034.96,447.56
  TopLayer - S1 (.GTL) w5.91: v2(2636,454.06) U12.5@2651.27,456.1
  BottomLayer - S8 (.GBL) w5.91: v2(2636,454.06) C273.2@2654,454.06
  BottomLayer - S8 (.GBL) w9.84: D13.3@2847.76,445.22 2847.76,437.3 2883.25,437.3 v1(2895,449.05)
PHY2_TD_C_N: C276.2 D8.6 T2.5 U12.11 | length 536
  TopLayer - S1 (.GTL) w3.98: U12.11@2651.27,574.21 U12.11@2681,574.21 2718.43,574.21 2722.05,570.59 2727.05,570.59 ccw(c2727.05,572.09) 2728.55,572.09 cw(c2730.05,572.09) 2731.55,572.09 ccw(c2733.05,572.09) 2733.05,570.59 2739.52,570.59 2753.61,556.5 2758.61,556.5 ccw(c2758.61,556.88) 2758.99,556.88 cw(c2759.36,556.88) 2759.74,556.88 ccw(c2760.11,556.88) 2760.11,556.5 2817.04,556.5 2827,566.46 2827,576.64 2840.56,590.2 2845.56,590.2 ccw(c2845.56,590.32) 2845.68,590.32 cw(c2845.81,590.32) 2845.93,590.32 ccw(c2846.06,590.32) 2846.06,590.2 2883.22,590.2 v1(2895,601.98) 2906.78,590.2 2911.78,590.2 ccw(c2911.78,595.45) 2917.03,595.45 cw(c2922.28,595.45) 2927.53,595.45 ccw(c2932.78,595.45) 2932.78,590.2 2989.81,590.2 2993.19,593.57 3025.07,593.57 T2.5@3034.96,603.46
  TopLayer - S1 (.GTL) w5.91: v2(2636,576.48) U12.11@2651.27,574.21
  BottomLayer - S8 (.GBL) w5.91: v2(2636,576.48) C276.2@2654,576.48
  BottomLayer - S8 (.GBL) w9.84: v1(2895,601.98) 2906.07,613.05 2942.24,613.05 D8.6@2942.24,605.1
PHY2_TD_C_P: C275.2 D8.1 T2.6 U12.10 | length 536
  TopLayer - S1 (.GTL) w3.98: U12.10@2651.27,554.53 U12.10@2681,554.53 ; 2734.36,558.14 2748.44,544.06 2822.2,544.06 2839.44,561.3 2839.44,566.3 cw(c2839.69,566.3) 2839.69,566.55 ccw(c2839.69,566.8) 2839.69,567.05 cw(c2839.69,567.3) 2839.44,567.3 2839.44,571.47 2843.77,575.8 ; v1(2895,565.98) 2906.87,577.85 2911.87,577.85 ccw(c2911.87,578.98) 2913,578.98 cw(c2914.12,578.98) 2915.25,578.98 ccw(c2916.37,578.98) 2916.37,577.85 2989.72,577.85 2993,574.57 3024.88,574.57 T2.6@3034.96,564.49
  TopLayer - S1 (.GTL) w4: U12.10@2681,554.53 2718.44,554.53 2722.05,558.14 2727.05,558.14 ccw(c2727.05,558.26) 2727.17,558.26 cw(c2727.3,558.26) 2727.42,558.26 ccw(c2727.55,558.26) 2727.55,558.14 2734.36,558.14 ; 2843.77,575.8 2845.71,577.74 2850.71,577.74 cw(c2850.71,573.62) 2854.84,573.62 ccw(c2858.96,573.62) 2863.09,573.62 cw(c2867.21,573.62) 2867.21,577.74 2883.23,577.74 v1(2895,565.98)
  TopLayer - S1 (.GTL) w5.91: v2(2636,552.48) U12.10@2651.27,554.53
  BottomLayer - S8 (.GBL) w5.91: v2(2636,552.48) C275.2@2654,552.48
  BottomLayer - S8 (.GBL) w9.84: D8.1@2847.76,605.1 2855.88,605.1 v1(2895,565.98)
PHY2_TD_D_N: C278.2 D8.4 T2.2 U12.14 | length 529.6
  TopLayer - S1 (.GTL) w3.98: U12.14@2651.27,633.27 U12.14@2681,633.27 2718.43,633.27 2722.05,629.65 2769.22,629.65 2846.7,707.13 2883.22,707.13 v1(2895,718.91) 2907,706.91 2989.59,706.91 2993.19,710.5 3025.07,710.5 T2.2@3034.96,720.39
  TopLayer - S1 (.GTL) w5.91: v2(2636,635.54) U12.14@2651.27,633.27
  BottomLayer - S8 (.GBL) w5.91: v2(2636,635.54) C278.2@2654,635.54
  BottomLayer - S8 (.GBL) w9.84: v1(2895,718.91) 2934,679.9 D8.4@2942.24,679.9
PHY2_TD_D_P: C277.2 D8.3 T2.3 U12.13 | length 535.7
  TopLayer - S1 (.GTL) w3.98: U12.13@2651.27,613.58 U12.13@2681,613.58 2718.43,613.58 2722.05,617.2 2727.05,617.2 ccw(c2727.05,618.08) 2727.92,618.08 cw(c2728.8,618.08) 2729.67,618.08 ccw(c2730.55,618.08) 2730.55,617.2 2774.37,617.2 2851.85,694.69 2856.85,694.69 ccw(c2856.85,694.94) 2857.1,694.94 cw(c2857.35,694.94) 2857.6,694.94 ccw(c2857.85,694.94) 2857.85,694.69 2883.22,694.69 v1(2895,682.91) 2906.77,694.67 2911.77,694.67 cw(c2911.77,691.42) 2915.02,691.42 ccw(c2918.27,691.42) 2921.52,691.42 cw(c2924.77,691.42) 2924.77,694.67 2989.83,694.67 2993,691.5 3024.88,691.5 T2.3@3034.96,681.42
  TopLayer - S1 (.GTL) w5.91: v2(2636,611.54) U12.13@2651.27,613.58
  BottomLayer - S8 (.GBL) w5.91: v2(2636,611.54) C277.2@2654,611.54
  BottomLayer - S8 (.GBL) w9.84: D8.3@2847.76,679.9 2847.76,671.95 2884.04,671.95 v1(2895,682.91)
PHY2_TX1588: R56.2 R61.2 U12.50 U15.E15 | length 2158
  TopLayer - S1 (.GTL) w4.72: U15.E15@1608.23,1271.73 1624,1287.5 v2(1752.5,1287.5)
  TopLayer - S1 (.GTL) w4.75: U12.50@2334.32,306.5 U12.50@2334.32,310.6
  TopLayer - S1 (.GTL) w5.91: v1(2334.55,250) U12.50@2334.55,306.5
  MidLayer2 - S3 (.G2) w4.72: v2(1752.5,1287.5) 1752.5,1227 1767.72,1211.78 1767.72,1177.17 1799.21,1145.67 1799.21,1096.71 1787.5,1085
  MidLayer2 - S3 (.G2) w4.92: 1787.5,1085 1787.5,970.5 1804,954 1804,834 1774.5,804.5 1662.77,804.5 1636.81,778.54 1636.81,544.29 2017.72,163.39 2298.23,163.39 2334.55,199.7 v1(2334.55,250)
  BottomLayer - S8 (.GBL) w5.91: v1(2334.55,250) 2334.55,187 2355.91,187
  BottomLayer - S8 (.GBL) w6: 2355.91,187 2377.5,187 R56.2@2377.5,176.12
PHY2_X_A_N: J5.2 T2.14 | length 509.7
  TopLayer - S1 (.GTL) w3.98: T2.14@3730.04,369.61 3740.12,359.52 3772,359.52 3775.28,356.24 3807.24,356.24 3845.94,394.94 3903.65,394.94 3958.11,340.49 4007.49,340.49 4086,419 4086,424 4078,432 4056,432 J5.2@4020.01,417.48
PHY2_X_A_P: J5.1 T2.13 | length 512
  TopLayer - S1 (.GTL) w3.98: T2.13@3730.04,330.63 3739.93,340.52 3771.81,340.52 3775.09,343.8 3812.4,343.8 3851.09,382.5 3898.5,382.5 3952.96,328.04 4012.64,328.04 4098.59,414 4113,414 4120.01,406.99 J5.1@4120.01,367.48
PHY2_X_B_N: J5.6 T2.17 | length 500.7
  TopLayer - S1 (.GTL) w3.98: T2.17@3730.04,486.54 3740.12,476.45 3772,476.45 3775.19,473.27 3795.72,473.27 v1(3807.5,485.05)
  MidLayer2 - S3 (.G2) w3.98: v1(3807.5,485.05) 3819.38,473.17 4047.2,473.17 4062.5,488.47 4062.5,575 J5.6@4020.01,617.48
PHY2_X_B_P: J5.3 T2.16 | length 506.3
  TopLayer - S1 (.GTL) w3.98: T2.16@3730.04,447.56 3739.93,457.45 3771.81,457.45 3775.19,460.83 3795.72,460.83 v1(3807.5,449.05)
  MidLayer2 - S3 (.G2) w3.98: v1(3807.5,449.05) 3819.38,460.93 4052.27,460.93 4074.74,483.4 4074.74,528.24 4079,532.5 4086,532.5 4090,528.5 4090,497.5 J5.3@4120.01,467.48
PHY2_X_C_N: J5.5 T2.20 | length 515.3
  TopLayer - S1 (.GTL) w3.98: T2.20@3730.04,603.46 3740.12,593.38 3772,593.38 3775.28,590.1 3787.69,590.1 3803.29,574.5 3825.44,574.5 3837.86,586.91 3837.86,608.83 3857.12,628.09 3894.31,628.09 3914.02,608.39 3914.02,586.47 3925.99,574.5 4043.59,574.5 4087.59,530.5 4104.5,530.5 4108.53,534.53 J5.5@4120.01,567.48
PHY2_X_C_P: J5.4 T2.19 | length 513.4
  TopLayer - S1 (.GTL) w3.98: T2.19@3730.04,564.49 3739.93,574.38 3771.81,574.38 3775.09,577.66 3782.54,577.66 3798.14,562.06 3830.6,562.06 3850.3,581.76 3850.3,603.68 3862.27,615.65 3889.16,615.65 3901.57,603.24 3901.57,581.32 3920.84,562.06 4038.44,562.06 4075.5,525 4075.5,516.5 4064.5,505.5 4053.5,505.5 J5.4@4020.01,517.48
PHY2_X_D_N: J5.8 T2.23 | length 519.2
  TopLayer - S1 (.GTL) w3.98: T2.23@3730.04,720.39 3740.12,710.31 3772,710.31 3775.28,707.03 3803.13,707.03 3825.54,729.44 3902.68,729.44 3960.12,672 4040,672 4092,724 4092,736 4085.5,742.5 4045.03,742.5 J5.8@4020.01,717.48
PHY2_X_D_P: J5.7 T2.22 | length 516
  TopLayer - S1 (.GTL) w3.98: T2.22@3730.04,681.42 3739.93,691.31 3771.81,691.31 3775.09,694.59 3808.28,694.59 3830.69,717 3897.53,717 3954.97,659.56 4045.15,659.56 4105.59,720 4125,720 4132,713 4132,701.5 J5.7@4120.01,667.48
PHY_RESETN: U6.59 U11.4 U12.59 | length 2288.3
  TopLayer - S1 (.GTL) w4.75: v1(2512.17,227.67) U12.59@2512.17,309.5 ; v1(2512.17,1325.17) U6.59@2512.17,1407
  TopLayer - S1 (.GTL) w5.91: U11.4@1954.9,1811.91 1968.5,1811.91 v1(1968.5,1783.46)
  MidLayer5 - S6 (.G5) w4.72: v1(2512.17,1325.17) 2528.91,1325.17 2552.5,1348.76
  MidLayer5 - S6 (.G5) w5.91: v1(1968.5,1783.46) 2360.47,1391.5 2529.5,1391.5 2552.5,1368.5 2552.5,1348.76 ; v1(2512.17,227.67) 2531.17,208.66 2565.94,208.66 2570.87,213.58 2570.87,669.29 2561.02,679.13 2561.02,867.91 2449,979.94 2449,1201.95 2512.17,1265.12 v1(2512.17,1325.17)
PMIC_PWR_EN: U13.1 U15.C6 | length 1760.8
  TopLayer - S1 (.GTL) w4.75: v2(1309.02,1350.47) U15.C6@1324.76,1334.72
  TopLayer - S1 (.GTL) w6: v1@450.5,2367.5 474,2344 474,2340.61 U13.1@480.83,2340.61
  MidLayer5 - S6 (.G5) w5.91: v1(448,2366) 445,2366 421,2390 384,2390 309,2315 309,2164 383,2090 478.9,2090 1042.32,1526.57 1179.13,1526.57 1309.02,1396.69 v2(1309.02,1350.47)
PMIC_RESETOUTN: C191.2 R67.2 U13.40 U15.B15 | length 2248.4
  TopLayer - S1 (.GTL) w4.75: U15.B15@1608.23,1366.25 v2(1623.98,1381.97)
  TopLayer - S1 (.GTL) w8: U13.40@634.37,2368.17 634.37,2384.37 646,2396 v1(655,2396)
  MidLayer2 - S3 (.G2) w4.72: v2(1623.98,1381.97) 1658.46,1416.46 1658.46,1486.22 1646.65,1498.03 1626.97,1498.03 1606.3,1518.7 1606.3,1667.32 1740.16,1801.18 1740.16,1994.09 1702.76,2031.5 1702.76,2186.02 v1(1732.28,2215.55)
  MidLayer5 - S6 (.G5) w5.91: v1(655,2396) 903.21,2396 1058.07,2241.14 1706.69,2241.14 v1(1732.28,2215.55)
  BottomLayer - S8 (.GBL) w8: v1(655,2396) 655,2361.38 R67.2@656.38,2360
  BottomLayer - S8 (.GBL) w12: v2(1623.98,1381.97) 1653.52,1381.97 C191.2@1655,1380.49
PMIC_VRTC: C91.1 U13.19 U13.29 | length 342.4
  TopLayer - S1 (.GTL) w6: U13.19@602.87,2139.83 602.87,2124.13 v1(615,2112)
  TopLayer - S1 (.GTL) w8: U13.29@709.17,2230.38 721.38,2230.38 732.28,2241.28 ; v1@732.28,2250.98 732.28,2241.28 ; v1@737.06,2246.06 732.28,2241.28
  MidLayer2 - S3 (.G2) w5.91: v1(615,2112) 615,2165.2 700.79,2250.98 v1(737.2,2250.98)
  BottomLayer - S8 (.GBL) w15: C91.1@726.5,2295 737,2295 v1@737,2250.98
RGMII1_RXCLK: R20.2 U15.L18 | length 1021.4
  TopLayer - S1 (.GTL) w4.92: U15.L18@1702.72,1082.76 v2@1718.44,1067.05 ; v2(2066.93,1605.32) 2066.93,1582.68 2077.58,1572.03 R20.2@2105.47,1572.03
  MidLayer5 - S6 (.G5) w4.92: v2@1720.06,1065.43 1833.66,1065.43 1864.17,1034.92 1905,1034.92 1925.2,1055.12 1945.87,1055.12 2137.8,1247.05 2137.8,1581.69 2114.17,1605.32 v2(2066.93,1605.32)
  other v2: 1718.46,1067.03
RGMII1_RXCLK_R: R20.15 U6.43 | length 63
  TopLayer - S1 (.GTL) w4.92: R20.15@2164.53,1572.03 2164.7,1571.85 2225.4,1571.85 U6.43@2226.84,1573.29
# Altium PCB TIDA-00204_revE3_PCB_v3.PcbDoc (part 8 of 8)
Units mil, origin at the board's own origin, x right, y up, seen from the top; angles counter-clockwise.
Board outline 4600 x 3740 mil, 8 copper layers (TopLayer - S1 (.GTL), MidLayer1 - S2 (.G1), MidLayer2 - S3 (.G2), MidLayer3 - S4 (.G3), MidLayer4 - S5 (.G4), MidLayer5 - S6 (.G5), MidLayer6 - S7 (.G6), BottomLayer - S8 (.GBL)), stack 58.938 mil thick; 537 components, 354 nets, 2015 pads, 1067 vias.

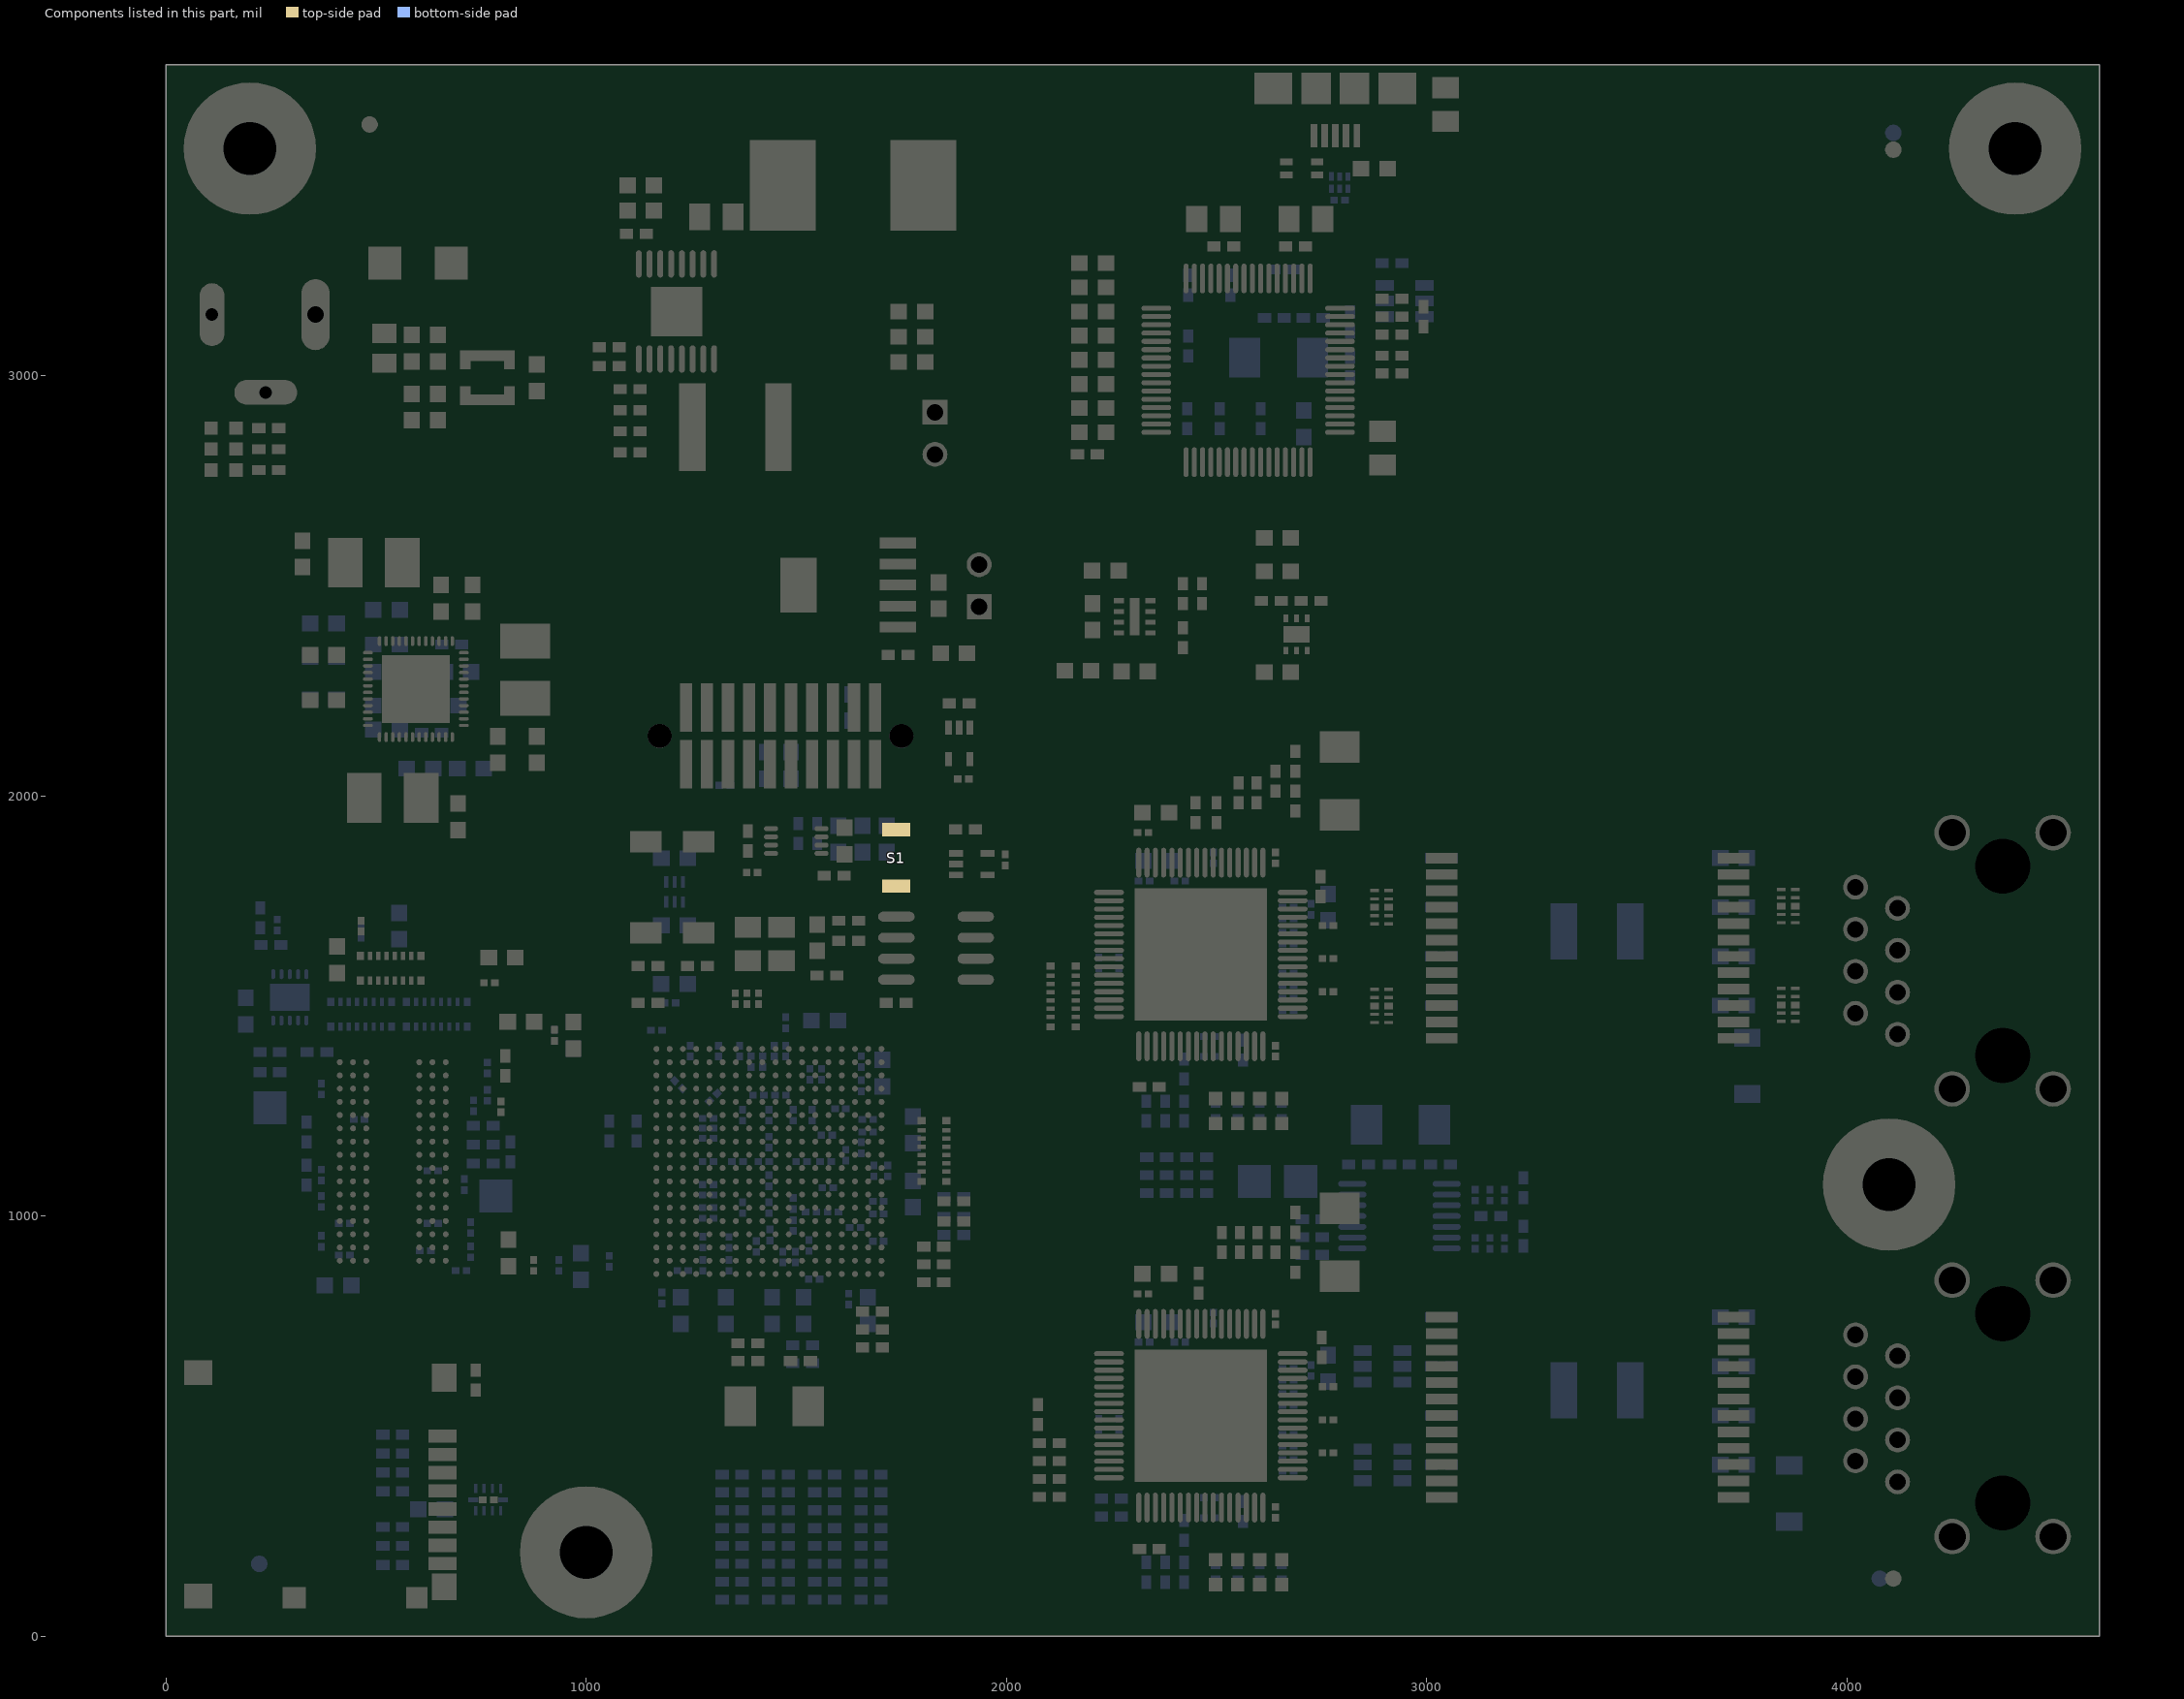
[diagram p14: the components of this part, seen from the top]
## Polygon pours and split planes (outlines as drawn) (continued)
FT_VDD1V8 on MidLayer2 - S3 (.G2) "MidLayer1 - S2 (.G1)-VAUX1" (solid, remove dead copper, pour order 76): 2381.89,2834.65 2381.89,3208.66 2401.57,3228.35 2807.09,3228.35 2826.77,3208.66 2826.77,2834.65 2807.09,2814.96 2401.57,2814.96
VAUX1 on MidLayer2 - S3 (.G2) "MidLayer2 - S3 (.G2)-VAUX1" (solid, remove dead copper, pour order 79): 540,2415 560,2415 575,2400 575,2300 550,2275 550,2077 513,2040 305,2040 305,2097 338,2130 442,2130 465,2153 465,2345 535,2415
VAUX33 on MidLayer2 - S3 (.G2) "MidLayer2 - S3 (.G2)-VAUX33" (solid, remove dead copper, pour order 68): 332,2262 346,2262 388,2304 431,2304 453,2282 453,2153 429.5,2153 386.5,2196 353,2196 332,2217
VMMC on MidLayer2 - S3 (.G2) "MidLayer2 - S3 (.G2)-VMMC" (solid, remove dead copper, pour order 123): 1397,785 1397,817 1445,865 1445,1172 1489.65,1216.65 1616.11,1216.65 1727.31,1216.65 1748.96,1195 1748.96,1160.98 1725,1137.03 1632.03,1137.03 1615,1120 1615,1025 1555,965 1525,935 1525,785
VMMC on MidLayer2 - S3 (.G2) "MidLayer2 - S3 (.G2)-VMMC 1" (solid, remove dead copper, pour order 119): 1056.91,692.91 1081,717 1081,802.91 1284,1005.91 1284,1119 1306,1141 1313,1148 1435,1148 1453,1148 1453,920 1422,951 1339.78,951 1241,852.22 1241,777 1241,725 1168,652 1154,638 1006,638 1002,638 971,669 971,692.91
GND on MidLayer6 - S7 (.G6) "MidLayer6 - S7 (.G6)-GND" (solid, remove dead copper, pour order 91): 433.07,2921.26 433.07,3704.72 442.91,3714.57 3238.19,3714.57 3248.03,3704.72 3248.03,2035.43 3125.98,1913.39 3125.98,1374.02 3255.91,1244.09 3255.91,901.57 3125.98,771.65 3125.98,35.43 3116.14,25.59 1181.1,25.59 1181.1,200 818.9,200 818.9,25.59 35.43,25.59 25.59,35.43 25.59,2891.73 35.43,2901.57 413.39,2901.57
GND on MidLayer6 - S7 (.G6) "MidLayer1 - S2 (.G1)-VAUX1" (solid, remove dead copper, pour order 70): 2518.7,2966.54 2528.54,2956.69 2602.36,2956.69 2763.78,2956.69 2791.34,2984.25 2791.34,3192.91 2771.65,3212.6 2654.53,3212.6 2649.61,3207.68 2649.61,3173.23 2641.73,3165.35 2574.8,3165.35 2518.7,3109.25
PHY1_EARTH on MidLayer6 - S7 (.G6) "MidLayer1 - S2 (.G1)-PHY1_EARTH" (solid, remove dead copper, pour order 107): 3730,1920 4260,1920 4260,1290 3730,1290 3690,1330 3690,1880
PHY2_EARTH on MidLayer6 - S7 (.G6) "MidLayer1 - S2 (.G1)-PHY1_EARTH" (solid, remove dead copper, pour order 103): 3730,855 4260,855 4260,225 3730,225 3690,265 3690,815
GND on MidLayer6 - S7 (.G6) "MidLayer6 - S7 (.G6)-No Net" (solid, remove dead copper, pour order 69): 2790,1285 2815,1310 -112031.96,1300 3065,1300 3080,1285 3080,1100 3065,1085 2922.5,1085 2891,1053.5 2882,1053.5 2850.5,1085 2830,1085 2805,1085 2790,1100
GND on MidLayer3 - S4 (.G3) "MidLayer3 - S4 (.G3)-GND" (solid, remove dead copper, pour order 90): 433.07,2921.26 433.07,3704.72 442.91,3714.57 3238.19,3714.57 3248.03,3704.72 3248.03,2035.44 3125.98,1913.39 3125.98,35.43 3116.14,25.59 1181.1,25.59 1181.1,200 818.9,200 818.9,25.59 35.43,25.59 25.59,35.43 25.59,2891.73 35.43,2901.57 413.39,2901.57

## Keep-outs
MidLayer1 - S2 (.G1):
  circle w0.5: c333,2191 r16.35
  circle w0.5: c333,2280 r16.35
  circle w0.5: c737,2112 r16.35
  circle w0.5: c333,2449 r16.35
  circle w0.5: c333,2373 r16.35
  circle w0.5: c797,2038.5 r16.35
  circle w0.5: c737,2360 r16.35
  circle w0.5: c655,2541 r16.35
  circle w0.5: c730,2541 r16.35
  circle w0.5: c1053.15,3396.44 r16.35
  circle w0.5: c1053.15,3337.5 r16.35
  circle w0.5: c1053.15,3456.44 r16.35
  circle w0.5: c1176.61,3311.45 r16.35
  circle w0.5: c2886.5,974.5 r16.14
  circle w0.5: c2803,1149.5 r16.14
  circle w0.5: c3067,1149.5 r16.14
  circle w0.5: c2580.02,3137.5 r16.14
  lines w0.5: 325.13,2487.6 cw(c316.2,2501.3) 325.22,2514.93 ; 325.17,2487.66 ccw(c334.2,2501.3) 325.27,2514.99 ; 694.43,2001.81 cw(c685.5,2015.5) 694.52,2029.14 ; 694.48,2001.87 ccw(c703.5,2015.5) 694.57,2029.2 ; 882.93,2023.31 cw(c874,2037) 883.02,2050.64 ; 882.98,2023.37 ccw(c892,2037) 883.07,2050.7
MidLayer3 - S4 (.G3):
  circle w0.5: c2655,2097.5 r16.14
  circle w0.5: c2655,1972.5 r16.14
  circle w0.5: c2662,875 r16.14
  circle w0.5: c2662,1000 r16.14
  circle w0.5: c2580.02,3137.5 r16.14
  circle w0.5: c3067,1149.5 r16.14
  circle w0.5: c2803,1149.5 r16.14
MidLayer6 - S7 (.G6):
  circle w0.5: c2655,2097.5 r16.14
  circle w0.5: c2655,1972.5 r16.14
  circle w0.5: c2662,875 r16.14
  circle w0.5: c2662,1000 r16.14
Keep-Out Layer:
  lines w3.94: 3283.46,3590.75 3283.46,3708.86 3598.43,3708.86 3598.43,3590.75 3283.46,3590.75
  lines w10: -5,-5 4605,-5 4605,3745 -5,3745 -5,-5
  text ".Layer_Name" at 577,-858.49 h60

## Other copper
TopLayer - S1 (.GTL):
  rectangle: 3283.46,3708.86 3322.83,3771.65
  region net NetC1_1: 1169.29,3411.42 1200.79,3411.42 1207.68,3404.53 1207.68,3325.79 1195.87,3325.79 1188.98,3332.68 1188.98,3367.13 1182.09,3374.02 1169.29,3374.02
  region net GND: 490,2937.5 490,3052.5 670,3052.5 672.5,3050 672.5,2940 670,2937.5
  region net VAUX2: 511.81,2376.97 508.86,2379.92 493.11,2379.92 446.85,2426.18 438.98,2426.18 438.98,2390.75 458.66,2390.75 493.11,2356.3 508.86,2356.3 511.81,2359.25
  region net GND: 714.5,2025.5 675.5,2025.5 675.5,1962 714.5,1962
  region net VDD1_SMPS: 864,2122 901,2122 901,2208 864,2208
  region net VDD1_SMPS: 864,2161 864,2123 934,2123 934,2161
  region net GND: 863,2027 902,2027 902,2099 863,2099
  region net GND: 2591,2275 2591,2408 2591,2476 2622,2476 2622,2421 2639,2404 2741,2404 2746,2409 2746,2476 2764,2476 2764,2373 2755,2364 2639,2364 2633,2358 2633,2275
  region net NetC18_1: 2280,2458 2280,2506 2286,2512 2286,2588 2281,2593 2251,2593 2246,2588 2246,2462 2250,2458
  region net GND: 2322,2366 2317,2361 2293,2361 2288,2366 2288,2494 2293.97,2499.97 2322,2499.97
  region net GND: 2223,2554 2184,2554 2184,2438 2223,2438
  region net NetC14_2: 1099,3079.5 1107,3071.5 1125,3071.5 1132,3064.5 1132,3013.5 1125,3006.5 1104,3006.5 1097,2999.5 1097,2955.5 1066,2955.5 1066,2993.5 1063,2996.5 1063,3079.5
  region net NetC8_1: 1221,3069.5 1224,3072.5 1257,3072.5 1260,3069.5 1260,2860.5 1254,2854.5 1230,2854.5 1221,2863.5
  region net NetL5_1: 528,1898.54 495,1898.54 495,2090 520,2115 528,2115
  region net VDDS_DDR: 551.76,1898.54 584.76,1898.54 584.76,2090 563.76,2111 551.76,2111
  region net VDD1_SMPS: 725.39,2273.62 731.02,2268 745.46,2268 763.66,2249.8 949.49,2249.8 949.49,2290 733.9,2290 725.39,2281.5
  region net NetL3_1: 729,2328.49 735,2334.49 742,2334.49 760.51,2353 951.46,2353 951.46,2312.49 738,2312.49 729,2321.49
  region net VDDS_DDR: 748,1899 748,1937 584,1937 584,1899
  region net NetL4_1: 607,2402 607,2613.28 600.28,2620 568,2620 568,2459 583,2444 583,2409 600,2392 607,2392
  region net VDD2_SMPS: 571,2404 550,2425 456.69,2425 407.69,2474 466,2474 491,2449 554,2449 575,2428 575,2404
  region net VDD2_SMPS: 263,2638 260,2635 260,2590 263,2587 424,2587 424,2638
  region net GND: 300.2,2494.3 303.2,2491.3 348.2,2491.3 351.38,2494.48 351.38,2563.98 300.2,2563.98
  region net V11PHY: 2657,2281 2695,2281 2696,2280 2696,2231 2693,2228 2661,2228 2657,2232
  region net NetC18_1: 2633,2627 2595,2627 2594,2628 2594,2677 2597,2680 2629,2680 2633,2676
  region net NetC18_1: 2285.99,2549 2247.99,2549 2246.99,2550 2246.99,2599 2249.99,2602 2281.99,2602 2285.99,2598
  region net VMMC: 387.5,2336 387.5,2361 383.5,2365 383.5,2375.5 388,2380 417,2380 421.5,2375.5 421.5,2336
  text "S1" at 3303.15,3661.61 h35.43
  text ".Layer_Name" at 577,-858.49 h60
MidLayer1 - S2 (.G1):
  rectangle: 3322.83,3708.86 3362.2,3771.65
  pour cut-out: 2170,2280 2170,2580 2190,2600 2460,2600 2480,2580 2480,2280 2460,2260 2190,2260
  text "S2" at 3374.02,3661.61 h35.43
  text ".Layer_Name" at 577,-858.49 h60
MidLayer2 - S3 (.G2):
  rectangle: 3362.2,3708.66 3401.57,3771.65
  text "S3" at 3448.82,3661.61 h35.43
  text ".Layer_Name" at 577,-858.49 h60
MidLayer3 - S4 (.G3):
  rectangle: 3401.57,3708.66 3440.94,3771.65
  text "S4" at 3523.62,3661.61 h35.43
  text ".Layer_Name" at 577,-858.49 h60
MidLayer4 - S5 (.G4):
  rectangle: 3440.94,3708.66 3480.31,3771.65
  text "S5" at 3582.68,3602.56 h35.43
  text ".Layer_Name" at 577,-858.49 h60
MidLayer5 - S6 (.G5):
  rectangle: 3480.31,3708.66 3519.69,3771.65
  text "S6" at 3507.87,3602.56 h35.43
  text ".Layer_Name" at 577,-858.49 h60
MidLayer6 - S7 (.G6):
  rectangle: 3519.69,3708.66 3559.06,3771.65
  text "S7" at 3433.07,3602.56 h35.43
  text ".Layer_Name" at 577,-858.49 h60
BottomLayer - S8 (.GBL):
  rectangle: 3559.06,3708.66 3598.43,3771.65
  region net VDIG2: 388,2232 388,2257 384,2261 384,2271.5 388.5,2276 417.5,2276 422,2271.5 422,2232
  region net VAUX2: 423.23,2428.39 444.88,2428.39 448.82,2424.45 448.82,2394.92 445.4,2391.5 417.32,2391.5 417.32,2422.48
  region net VAUX33: 388,2328 388,2303 384,2299 384,2288.5 388.5,2284 417.5,2284 422,2288.5 422,2328
  region net VAUX33: 260,1477 260,1434 170,1434 170,1477
  region net VAUX33: 211,1474 211,1436 141,1436 141,1474
  region net GND: 177,1553 363,1553 369,1547 369,1494 363,1488 177,1488 170,1495 170,1546
  region net VMMC: 1397,826 1427,826 1427,787 1397,787
  region net GND: 2750,2355 2735,2340 2610,2340 2595,2355 2595,2415 2610,2430 2735,2430 2750,2415
  region net GND: 2340,2335 2265,2335 2250,2350 2250,2540 2265,2555 2365,2555 2380,2540 2380,2480 2350,2450 2350,2345
  region net NetC18_1: 2245,2575 2235,2585 2235,2670 2250,2685 2630,2685 2645,2670 2645,2585.46 2634.54,2575
  region net VDC_USB: 2778.54,3453.74 2754.92,3453.74 2750,3448.82 2750,3414.37 2754.92,3409.45 2788.39,3409.45 2788.39,3425.2 2781.5,3425.2 2778.54,3428.15
  region net GND: 2807.09,3453.74 2807.09,3429.13 2802.17,3424.21 2802.17,3409.45 2833.66,3409.45 2837.6,3413.39 2837.6,3449.8 2833.66,3453.74
  pour cut-out: 3614.17,1848.43 cw(c3675.2,1848.43) 3675.2,1909.45 3788.89,1909.45 cw(c3788.89,1889.29) 3803.15,1903.54 3850.15,1856.54 ccw(c3860.24,1866.62) 3860.24,1852.36 4068.9,1852.36 cw(c4068.9,1732.28) 4188.98,1732.28 4188.98,1431.1 cw(c4120.08,1431.1) 4120.08,1362.2 3720.95,1362.2 cw(c3720.95,1382.37) 3706.69,1368.11 3619.74,1455.06 cw(c3633.18,1468.5) 3614.17,1468.5
  pour cut-out: 3614.17,755.91 cw(c3675.2,755.91) 3675.2,816.93 3788.89,816.93 cw(c3788.89,796.77) 3803.15,811.02 3823.17,791 ccw(c3836.61,804.44) 3836.61,785.43 4070.87,785.43 cw(c4070.87,667.32) 4188.98,667.32 4188.98,368.11 cw(c4120.08,368.11) 4120.08,299.21 4037.88,299.21 cw(c4037.88,319.38) 4023.62,305.12 3987.85,340.89 ccw(c3974.41,327.45) 3974.41,346.46 3675.2,346.46 cw(c3675.2,407.48) 3614.17,407.48
  text ".PRJ_Number" at 3986.22,3661.42 h35.43
  text "S8" at 3358.27,3602.56 h35.43
  text ".PCB_Rev" at 3858.27,3602.36 h35.43
  text "Rev" at 3986.22,3602.36 h35.43
  text ".Layer_Name" at 577,-858.49 h60

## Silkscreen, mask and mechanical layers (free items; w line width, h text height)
Top Overlay:
  lines w7.87: 3305.12,3398.82 3305.12,3559.06 3572.18,3559.06 3305.12,3398.82
  lines w15.75: 2085.63,589.57 2085.63,1408.46 ; 2086.61,285.43 2086.61,39.37 2440.94,39.37 ; 2086.61,1653.54 2086.61,2706.69 3014,2706.69 3014,2057.09 4527.56,2057.09 4527.56,1978.35 ; 2706.69,39.37 4527.56,39.37 4527.56,167.32 ; 4527.56,905.51 4527.56,1250
  text "GCD" at 3322.83,3503.94 h62.99
  text "www.gcd.de" at 3373.39,3397.99 h39.37 r31
  text "24v" at 375.98,3375.98 h60
  text ".PRJ_Number" at 3582.68,2952.76 h60
  text "5v" at 375.98,2864.17 h27.56
  text "Rev" at 3592.52,2834.65 h60
  text "E3" at 3809.06,2834.65 h60
  text "5v" at 1645.67,2833.66 h60
  text "2v5" at 374.02,2813.98 h27.56
  text "Vaux33" at 374.02,2762.8 h27.56
  text "3v3" at 1888.78,2629.92 h60
  text "10/100/1000 ETH" at 2716.54,1210.63 h60
  text "1" at 3612.2,1210.63 h60
  text "10/100/1000 ETH" at 2716.54,118.11 h60
  text "2" at 3612.2,118.11 h60
  text ".Layer_Name" at 577,-858.49 h60
Bottom Overlay:
  lines w3.94: 1064.96,1003.94 1078.74,990.16 1253.94,990.16 ; 1187.01,895.67 1216.54,895.67 1228.35,885.83 ; 1187.01,925.2 1226.38,925.2 1259.84,887.8 ; 1187.01,956.69 1240.16,956.69 1259.84,942.91 ; 1204.72,1017.72 1216.54,1017.72 1240.16,1072.83 1253.94,1072.83 ; 1228.35,1129.92 1259.84,1129.92 ; 1250,1125.98 1259.84,1129.92 ; 1250,1133.86 1259.84,1129.92 ; 1301.18,1431.1 1307.09,1421.26 ; 1393.7,822.83 1405.51,866.14 1405.51,895.67 ; 1436.56,611.2 1436.56,681.06 1480.32,724.82 1480.32,856.3 ; 1458.66,1433.07 1464.57,1423.23 ; 1470.47,870.08 1480.32,856.3 ; 1490.16,870.08 1480.32,856.3 ; 1505.91,1023.62 1513.78,1027.56 ; 1527.72,1203.11 1533.62,1210.98 ; 1541.34,992.13 1541.34,968.5 1582.68,927.17 ; 1588.58,992.13 1588.58,964.57 1633.86,919.29 ; 1625.75,1326.61 1639.53,1310.87 ; 1643.7,954.72 1643.7,946.85 1671.26,919.29 ; 1700.79,1240.16 1761.81,1291.34 1807.09,1291.34 ; 1706.69,988.19 1706.69,978.35 1752.44,932.6 ; 1724.41,925.2 1755,894.61 ; 1724.41,1021.65 1734.25,1011.81 1734.25,986.22 1750.61,969.86 ; 1734.25,1114.17 1757.87,1131.89 1866.14,1131.89 1897.46,1123.31
  text ".Layer_Name" at 577,-858.49 h60
Top Paste:
  text ".Layer_Name" at 577,-858.49 h60
Bottom Paste:
  text ".Layer_Name" at 577,-858.49 h60
Top Solder:
  text ".Layer_Name" at 577,-858.49 h60
  text ".Layer_Name" at 577,-858.49 h60
Bottom Solder:
  text "GCD 11941" at 4580.71,22.64 h27.56
  text ".Layer_Name" at 577,-858.49 h60
Drill Guide:
  text ".Layer_Name" at 577,-858.49 h60
M1 Board Outline:
  the board outline again, w10
  text ".Layer_Name" at 577,-858.49 h60
M2 Board Dimensions:
  rectangle: 125,-400 500,-275
  rectangle: 0,-275 125,-150
  lines w7: 0,-275 1000,-275 ; 125,-400 125,-150 ; 250,-400 250,-150 ; 500,-400 500,-150 ; 750,-400 750,-150 ; 0,-400 0,-150 1000,-150 1000,-400 0,-400
  text ".Layer_Name" at 577,-858.49 h60
M3 3D STEP Top:
  text ".Layer_Name" at 577,-858.49 h60
M4 3D STEP Bottom:
  text ".Layer_Name" at 577,-858.49 h60
M5 Assembly Top:
  lines w10: -292,-930.17 6308,-930.17 ; -292,-726.83 6310,-726.83 ; -292,-523.5 -292,-1133.5 3713,-1133.5 6310,-1133.5 6310,-523.5 -291.5,-523.5 -291.5,-1133.5 1284,-1133.5 ; 2173,-1133.5 2173,-523.5 ; 3440,-726.83 3440,-523.5 ; 4280,-726.83 4280,-523.5 ; 4902,-1140 4902,-937.17
  text "COMPONENTS MARKED 'DNP' SHOULD NOT BE POPULATED." at 1153.5,-318.5 h60
  text "ASSEMBLY VARIANT:" at 1153,-434 h60
  text ".VariantName" at 2189,-434 h60
  text "PCB VIEWED FROM TOP SIDE" at -228.5,-655.67 h60
  text "BOARD #:" at 2248,-655.67 h60
  text ".PRJ_Number" at 2793.5,-655.67 h60
  text "REV:" at 3638,-655.67 h60
  text ".PCB_Rev" at 3929.5,-655.67 h60
  text "SVN REV:" at 4476,-655.67 h60
  text ".VersionControl_RevNumber" at 4982,-655.67 h60
  text ".Layer_Name" at 577,-858.49 h60
  text "PLOT NAME =" at -228.5,-1064.34 h60
  text ".plot_File_Name" at 577,-1064.34 h60
  text "GENERATED    :" at 2250,-1064.34 h60
  text ".Print_Date" at 3119.5,-1064.34 h60
  text ".Print_Time" at 3848.5,-1064.34 h60
  text "TEXAS INSTRUMENTS" at 5113,-1064.34 h60
M6 Assembly Bottom:
  lines w10: -292.5,-727.33 6309.5,-727.33 ; -290.5,-930.67 6309.5,-930.67 ; 1115.5,-1140.5 1115.5,-937.67 ; 1737.5,-727.33 1737.5,-524 ; 2577.5,-727.33 2577.5,-524 ; 3844.5,-1134 3844.5,-524 ; 4733.5,-1134 6309,-1134 6309,-524 -292.5,-524 -292.5,-1134 2304.5,-1134 6309.5,-1134 6309.5,-524
  text "COMPONENTS MARKED 'DNP' SHOULD NOT BE POPULATED." at 6102,-318 h60
  text ".VariantName" at 5058,-434 h60
  text "ASSEMBLY VARIANT:" at 6097,-434 h60
  text ".VersionControl_RevNumber" at 1035.5,-656.17 h60
  text "SVN REV:" at 1541.5,-656.17 h60
  text ".PCB_Rev" at 2088,-656.17 h60
  text "REV:" at 2379.5,-656.17 h60
  text ".PRJ_Number" at 3224,-656.17 h60
  text "BOARD #:" at 3769.5,-656.17 h60
  text "PCB VIEWED FROM BOTTOM SIDE" at 6246,-656.17 h60
  text ".Layer_Name" at 577,-858.49 h60
  text "TEXAS INSTRUMENTS" at 904.5,-1064.84 h60
  text ".Print_Time" at 2169,-1064.84 h60
  text ".Print_Date" at 2898,-1064.84 h60
  text "GENERATED    :" at 3767.5,-1064.84 h60
  text ".plot_File_Name" at 5440.5,-1064.84 h60
  text "PLOT NAME =" at 6246,-1064.84 h60
M9 Title Sheet:
  drawing of 57 lines, arcs and shapes, not listed
  text "1" at 739.84,8036.5 h70
  text "2" at 3235.5,8036.5 h70
  text "3" at 5724.84,8036.5 h70
  text "4" at 8231.51,8036.5 h70
  text "5" at 10730.5,8036.5 h70
  text "6" at 13235.5,8036.5 h70
  text "A" at -416.5,6893.5 h70
  text "A" at 14383.5,6893.5 h70
  text "B" at -416.5,4513.5 h70
  text "B" at 14383.5,4513.5 h70
  text "C" at -416.5,2138.5 h70
  text "C" at 14383.5,2138.5 h70
  text "PROJECT TITLE:" at 11343.5,277.5 h45
  text ".PRJ_Title" at 11393.5,144.17 h70
  text "DESIGNED FOR:" at 11343.5,-23.5 h45
  text ".PRJ_Customer" at 11393.5,-163.5 h70
  text "D" at -416.5,-231.5 h70
  text "D" at 14383.5,-231.5 h70
  text "FILE NAME:" at 11343.5,-323.5 h45
  text ".PCB_File_Name_No_Path" at 11393.5,-443.5 h70
  text "Texas Instruments (TI) and/or its licensors do not warrant the accuracy or completeness of this specification" at 6374,-605.34 h45
  text "ENGINEER:" at 11343.5,-613.5 h45
  text "LAYOUT BY:" at 12848.5,-613.5 h45
  text "or any information contained therein. TI and/or its licensors do not warrant that this design will meet" at 6329.01,-718 h45
  text ".PRJ_Engineer" at 11393.5,-768.49 h70
  text ".PCB_Layout" at 12899,-768.49 h70
  text "the specifications, will be suitable for your application or fit for any particular purpose, or will operate in" at 6329.01,-830.67 h45
  text ".Layer_Name" at 577,-858.49 h60
  text "ALTIUM DESIGNER VERSION:" at 12848.5,-923.5 h45
  text "an implementation. TI and/or its licensors do not warrant that the design is production worthy. You should" at 6329.01,-943.33 h45
  text "completely validate and test your design implementation to confirm the system functionality for your application." at 6374,-1056 h45
  text ".print_Scale" at 11393.5,-1056.83 h70
  text ".Application_BuildNumber" at 12899,-1056.83 h70
  text "1" at 739.84,-1263.5 h70
  text "2" at 3235.5,-1263.5 h70
  text "3" at 5724.84,-1263.5 h70
  text "4" at 8231.51,-1263.5 h70
  text "5" at 10730.5,-1263.5 h70
  text "6" at 13235.5,-1263.5 h70
M10 Fab Notes:
  drawing of 185 lines, arcs and shapes, not listed
  text "DESIGN INFORMATION" at 12381.02,5910 h60
  text "MIN. TRACK WIDTH:" at 11736.46,5730 h60
  text "0.1" at 12775,5730 h60
  text "mm" at 12985,5730 h60
  text "(4 MIL)" at 13290,5730 h60
  text "(4 MIL)" at 13290,5600 h60
  text "MIN. CLEARANCE:" at 11736.46,5598 h60
  text "0.1" at 12772.7,5598 h60
  text "mm" at 12987.46,5598 h60
  text "MIN. VIA PAD SIZE:" at 11736.46,5466 h60
  text "(17.7 MIL)" at 13290,5465 h60
  text "0.45" at 12737.7,5463 h60
  text "mm" at 12987.46,5463 h60
  text "0.125mm (5MIL)" at 12431.46,5324.29 h60
  text "MINIMUM ANNULAR RING" at 11407.23,5320 h60
  text "EXTERNAL" at 13139.46,5320 h60
  text "PER" at 11607.23,5202 h60
  text "IPC-D-275 CLASS 2 LEVEL C" at 11827.23,5202 h60
  text "MIL, HOLES" at 13315.46,5089.71 h60
  text "+/-" at 12923,5089 h60
  text "+/-" at 13777,5089 h60
  text "REGISTRATION TOLERANCES:" at 11407.23,5084 h60
  text "METAL" at 12607,5084 h60
  text "5" at 13183.2,5084 h60
  text "3" at 14016.2,5084 h60
  text "MIL" at 14132.46,5084 h60
  text "MATERIAL:" at 11332.46,4874.54 h60
  text "FR-4 High Tg" at 12318.9,4734.21 h60
  text "FR-408" at 11753.46,4725.64 h60
  text "X" at 12165.46,4725.64 h60
  text "OTHER" at 13241.46,4725.64 h60
  text "61 MIL (1.55mm) +/-10%" at 12073.56,4562.92 h60
  text "THICKNESS:" at 11407.23,4558.64 h60
  text "X" at 11945.4,4558.64 h60
  text "OTHER" at 13358.46,4558.64 h60
  text "TOLERANCE:" at 11407.23,4400.64 h60
  text "X" at 12246.53,4400.64 h60
  text "ANSI IPC-6012 TYPE 3 CLASS 2" at 12433.48,4400.64 h60
  text "OTHER +/-" at 12433.46,4244.64 h60
  text "BOW & TWIST:" at 11407.23,4087.64 h60
  text "X" at 12246.53,4087.64 h60
  text "ANSI IPC-6012 TYPE 3 CLASS 2" at 12433.48,4087.64 h60
  text "OTHER +/-" at 12433.46,3929.13 h60
  text "DRILLING:" at 11332.46,3790.64 h60
  text "REFERENCE:" at 11407.23,3673.64 h60
  text "X" at 12055.46,3673.64 h60
  text "AS SHOWN" at 12242.46,3673.64 h60
  text "X" at 12956.46,3673.64 h60
  text "NC_DRILL FILES" at 13093.46,3673.64 h60
  text "PTH MIN COPPER THICKNESS:" at 11407.23,3515.64 h60
  text "X" at 12757.46,3515.64 h60
  text "1MIL" at 12894.46,3515.64 h60
  text "OTHER" at 13391.46,3515.64 h60
  text "BOARD FINISH:" at 11332.46,3356.64 h60
  text "SILKSCREEN:" at 11487.68,3238.64 h60
  text "X" at 12436.46,3238.64 h60
  text "TOP" at 12562.46,3238.64 h60
  text "X" at 12946.46,3238.64 h60
  text "BOTTOM" at 13073.46,3238.64 h60
  text "SILKSCREEN COLOR:" at 11487.68,3071.64 h60
  text "X" at 12435.42,3071.64 h60
  text "WHITE" at 12562.46,3071.64 h60
  text "OTHER" at 13073.46,3071.64 h60
  text "SOLDER RESIST COLOR:" at 11487.68,2901.64 h60
  text "X" at 12055.42,2742.44 h60
  text "GREEN" at 12182.46,2742.44 h60
  text "BLUE" at 12773.46,2742.44 h60
  text "OTHER" at 13311.46,2742.44 h60
  text "IMMERSION GOLD (ENIG)" at 12393.46,2553.92 h60
  text "ENEPIG" at 13731,2550.64 h60
  text "SURFACE FINISH:" at 11332.46,2549.64 h60
  text "X" at 12206.51,2549.64 h60
  text "IMM. TIN/SILVER OR EQUIV" at 11662,2392.64 h60
  text "OTHER" at 13093.46,2392.64 h60
  text "ARRAY/PANEL:" at 11332.46,2213.64 h60
  text "CUT AND TRIM PER MECH LAYER 1" at 12393.46,2209.35 h60
  text "N.C. ROUTE" at 12393.46,2057.64 h60
  text "X" at 13072.46,2057.64 h60
  text "V. SCORE" at 13259.46,2057.64 h60
  text "CERTIFICATION:" at 11332.46,1920.64 h60
  text "MATERIALS AND WORKMANSHIP FOR ALL PCBS" at 12057.46,1920.64 h60
  text "TO MEET OR EXCEED THE REQUIREMENTS OF:" at 12057.46,1822.64 h60
  text "X" at 11683.96,1686.13 h60
  text "ANSI IPC-A-600F CLASS ->" at 11822.96,1686.13 h60
  text "X" at 13462.02,1686.13 h60
  text "2" at 13580.96,1686.14 h60
  text "1" at 13265.96,1684.64 h60
  text "3" at 13934.96,1684.64 h60
  text "X" at 11686.02,1526.64 h60
  text "UL 94V-0" at 11822.96,1526.64 h60
  text "X" at 12498.02,1526.64 h60
  text "RoHS" at 12634.96,1526.64 h60
  text "OTHER" at 13279.36,1526.64 h60
  text "PER ORDER" at 13676.42,1526.64 h60
  text "ADDITIONAL REQUIREMENTS:" at 11332.46,1385.64 h60
  text "MICROSECTION:" at 11407.23,1270.64 h60
  text "YES" at 12312.96,1270.64 h60
  text "REQUIRED" at 13174.46,1114.49 h60
  text "BARE BOARD ELEC. TEST:" at 11407.23,1111.64 h60
  text "NONE" at 12712.96,1111.64 h60
  text "X" at 13047.46,1111.64 h60
  text "PER ORDER" at 13766.46,1111.64 h60
  text "MANUFACTURER'S UL:" at 11407.23,954.64 h60
  text "RAIL" at 12572.96,950.35 h60
  text "METAL" at 13064.77,950.35 h60
  text "X" at 13440,950 h60
  text "SILK" at 13576.46,950.35 h60
  text ".Layer_Name" at 577,-858.49 h60
M11 Gerber Information:
  lines w10: -292,-930.17 6308,-930.17 ; -292,-726.83 6310,-726.83 ; -292,-523.5 -292,-1133.5 3713,-1133.5 6310,-1133.5 6310,-523.5 -291.5,-523.5 -291.5,-1133.5 1284,-1133.5 ; 2173,-1133.5 2173,-523.5 ; 3440,-726.83 3440,-523.5 ; 4280,-726.83 4280,-523.5 ; 4902,-1140 4902,-937.17
  text "ALL ARTWORK VIEWED FROM TOP SIDE" at -228.5,-655.67 h60
  text "BOARD #:" at 2248,-655.67 h60
  text ".PRJ_Number" at 2793.5,-655.67 h60
  text "REV:" at 3638,-655.67 h60
  text ".PCB_Rev" at 3929.5,-655.67 h60
  text "SVN REV:" at 4476,-655.67 h60
  text ".VersionControl_RevNumber" at 4982,-655.67 h60
  text "LAYER NAME =" at -228.5,-858.49 h60
  text "PLOT NAME =" at -228.5,-1064.34 h60
  text ".plot_File_Name" at 577,-1064.34 h60
  text "GENERATED    :" at 2250,-1064.34 h60
  text ".Print_Date" at 3119.5,-1064.34 h60
  text ".Print_Time" at 3848.5,-1064.34 h60
  text "TEXAS INSTRUMENTS" at 5113,-1064.34 h60
M12 Stackup:
  drawing of 503 lines, arcs and shapes, not listed
  text "Layer" at 5106.09,5915 h60
  text "Name" at 5516,5915 h60
  text "Material" at 6955.58,5915 h60
  text "Thickness" at 8885,5915 h60
  text "Constant" at 9534.84,5915 h60
  text "Board Layer Stack" at 10104.7,5915 h60
  text "1" at 5106.09,5795 h60
  text "Top Overlay" at 5516,5795 h60
  text "2" at 5106.09,5675 h60
  text "Top Solder" at 5516,5675 h60
  text "Solder Resist" at 6955.58,5675 h60
  text "0.015mm" at 8885,5675 h60
  text "3.9" at 9534.84,5675 h60
  text "3" at 5106.09,5555 h60
  text "TopLayer - S1 (.GTL)" at 5516,5555 h60
  text "Copper" at 6955.58,5555 h60
  text "0.018mm" at 8885,5555 h60
  text "4" at 5106.09,5435 h60
  text "Dielectric1" at 5516,5435 h60
  text "FR4, IS420ML, 1x 1080 (Prepreg)" at 6955.58,5435 h60
  text "0.085mm" at 8885,5435 h60
  text "4.36" at 9534.84,5435 h60
  text "5" at 5106.09,5315 h60
  text "MidLayer1 - S2 (.G1)" at 5516,5315 h60
  text "Copper" at 6955.58,5315 h60
  text "0.018mm" at 8885,5315 h60
  text "6" at 5106.09,5195 h60
  text "Dielectric2" at 5516,5195 h60
  text "FR4, IS420ML, 1x 2116 (Core)" at 6955.58,5195 h60
  text "0.101mm" at 8885,5195 h60
  text "4.72" at 9534.84,5195 h60
  text "7" at 5106.09,5075 h60
  text "MidLayer2 - S3 (.G2)" at 5516,5075 h60
  text "Copper" at 6955.58,5075 h60
  text "0.018mm" at 8885,5075 h60
  text "8" at 5106.09,4955 h60
  text "Dielectric3" at 5516,4955 h60
  text "FR4, IS420ML, 3x 2157 (Prepreg)" at 6955.58,4955 h60
  text "0.440mm" at 8885,4955 h60
  text "4.75" at 9534.84,4955 h60
  text "9" at 5106.09,4835 h60
  text "MidLayer3 - S4 (.G3)" at 5516,4835 h60
  text "Copper" at 6955.58,4835 h60
  text "0.018mm" at 8885,4835 h60
  text "10" at 5106.09,4715 h60
  text "Dielectric4" at 5516,4715 h60
  text "FR4, IS420ML, 1x 2116 (Core)" at 6955.58,4715 h60
  text "0.101mm" at 8885,4715 h60
  text "4.72" at 9534.84,4715 h60
  text "11" at 5106.09,4595 h60
  text "MidLayer4 - S5 (.G4)" at 5516,4595 h60
  text "Copper" at 6955.58,4595 h60
  text "0.018mm" at 8885,4595 h60
  text "12" at 5106.09,4475 h60
  text "Dielectric5" at 5516,4475 h60
  text "FR4, IS420ML, 3x 2157 (Prepreg)" at 6955.58,4475 h60
  text "0.440mm" at 8885,4475 h60
  text "4.75" at 9534.84,4475 h60
  text "13" at 5106.09,4355 h60
  text "MidLayer5 - S6 (.G5)" at 5516,4355 h60
  text "Copper" at 6955.58,4355 h60
  text "0.018mm" at 8885,4355 h60
  text "14" at 5106.09,4235 h60
  text "Dielectric 6" at 5516,4235 h60
  text "FR4, IS420ML, 1x 2116 (Core)" at 6955.58,4235 h60
  text "0.101mm" at 8885,4235 h60
  text "4.72" at 9534.84,4235 h60
  text "15" at 5106.09,4115 h60
  text "MidLayer6 - S7 (.G6)" at 5516,4115 h60
  text "Copper" at 6955.58,4115 h60
  text "0.018mm" at 8885,4115 h60
  text "16" at 5106.09,3995 h60
  text "Dielectric 7" at 5516,3995 h60
  text "FR4, IS420ML, 1x 1080 (Prepreg)" at 6955.58,3995 h60
  text "0.085mm" at 8885,3995 h60
  text "4.36" at 9534.84,3995 h60
  text "17" at 5106.09,3875 h60
  text "BottomLayer - S8 (.GBL)" at 5516,3875 h60
  text "Copper" at 6955.58,3875 h60
  text "0.018mm" at 8885,3875 h60
  text "18" at 5106.09,3755 h60
  text "Bottom Solder" at 5516,3755 h60
  text "Solder Resist" at 6955.58,3755 h60
  text "0.015mm" at 8885,3755 h60
  text "3.9" at 9534.84,3755 h60
  text "19" at 5106.09,3635 h60
  text "Bottom Overlay" at 5516,3635 h60
  text ".Layer_Name" at 577,-858.49 h60
M13 Component Bodies Top:
  text ".Layer_Name" at 577,-858.49 h60
M14 Component Bodies Bottom:
  text ".Layer_Name" at 577,-858.49 h60
M15 Courtyards Top:
  text ".Layer_Name" at 577,-858.49 h60
M16 Courtyards Bottom:
  text ".Layer_Name" at 577,-858.49 h60
Drill Drawing:
  lines w10: 9067.26,2459.74 9078.33,2459.74 9078.33,2448.67 9100.47,2448.67 9100.47,2459.74 9111.54,2459.74 9111.54,2481.88 9100.47,2481.88 9100.47,2492.95 9078.33,2492.95 9078.33,2481.88 9067.26,2481.88 9067.26,2459.74 ; 9067.26,2548.29 9067.26,2559.36 9078.33,2570.43 9067.26,2581.5 9067.26,2592.57 9078.33,2592.57 9089.4,2581.5 9100.47,2592.57 9111.54,2592.57 9111.54,2581.5 9100.47,2570.43 9111.54,2559.36 9111.54,2548.29 9100.47,2548.29 9089.4,2559.36 9078.33,2548.29 9067.26,2548.29 ; 9067.26,2647.92 9089.4,2658.99 9111.54,2647.92 9100.47,2670.06 9111.54,2692.19 9089.4,2681.12 9067.26,2692.19 9078.33,2670.06 9067.26,2647.92 ; 9067.26,2791.82 9111.54,2791.82 9089.4,2747.54 9067.26,2791.82 ; 9067.26,2891.44 9111.54,2891.44 9089.4,2847.16 9067.26,2891.44 ; 9067.26,3157.1 9078.33,3157.1 9089.4,3146.03 9100.47,3157.1 9111.54,3157.1 9100.47,3168.17 9111.54,3179.24 9100.47,3179.24 9089.4,3190.31 9078.33,3179.24 9067.26,3179.24 9078.33,3168.17 9067.26,3157.1 ; 9076.12,2464.17 9082.76,2464.17 9082.76,2457.53 9096.04,2457.53 9096.04,2464.17 9102.68,2464.17 9102.68,2477.45 9096.04,2477.45 9096.04,2484.09 9082.76,2484.09 9082.76,2477.45 9076.12,2477.45 9076.12,2464.17 ; 9076.12,2557.15 9076.12,2563.79 9082.76,2570.43 9076.12,2577.07 9076.12,2583.72 9082.76,2583.72 9089.4,2577.07 9096.04,2583.72 9102.68,2583.72 9102.68,2577.07 9096.04,2570.43 9102.68,2563.79 9102.68,2557.15 9096.04,2557.15 9089.4,2563.79 9082.76,2557.15 9076.12,2557.15 ; 9076.12,2656.77 9089.4,2663.41 9102.68,2656.77 9096.04,2670.06 9102.68,2683.34 9089.4,2676.7 9076.12,2683.34 9082.76,2670.06 9076.12,2656.77 ; 9076.12,2782.96 9102.68,2782.96 9089.4,2756.39 9076.12,2782.96 ; 9076.12,3161.53 9082.76,3161.53 9089.4,3154.88 9096.04,3161.53 9102.68,3161.53 9096.04,3168.17 9102.68,3174.81 9096.04,3174.81 9089.4,3181.45 9082.76,3174.81 9076.12,3174.81 9082.76,3168.17 9076.12,3161.53
  lines w12: 9026.5,2418.79 10915.61,2418.79 ; 9026.5,3315.39 10915.61,3315.39 ; 9342.14,2319.16 9342.14,3415.01 ; 9659.32,2319.16 9659.32,3415.01 ; 10281.06,2319.16 10281.06,3415.01 ; 10525.38,2319.16 10525.38,3415.01 ; 9026.5,2319.16 10915.61,2319.16 10915.61,3415.01 9026.5,3415.01 9026.5,2319.16
  text "Symbol" at 9086.27,3345.27 h72
  text "Quantity" at 9372.02,3345.27 h72
  text "Finished Hole Size" at 9689.2,3345.27 h72
  text "Plated" at 10310.95,3345.27 h72
  text "Hole Type" at 10555.27,3345.27 h72
  text "2" at 9372.02,3245.65 h60
  text "57.09mil (1.450mm)" at 9689.2,3245.65 h60
  text "NPTH" at 10310.95,3245.65 h60
  text "Round" at 10555.27,3245.65 h60
  text "A" at 9064.65,3235.66 h44.28
  text "4" at 9372.02,3146.03 h60
  text "131.10mil (3.330mm)" at 9689.2,3146.03 h60
  text "NPTH" at 10310.95,3146.03 h60
  text "Round" at 10555.27,3146.03 h60
  text "1036" at 9372.02,3046.41 h60
  text "7.87mil (0.200mm)" at 9689.2,3046.41 h60
  text "PTH" at 10310.95,3046.41 h60
  text "Round" at 10555.27,3046.41 h60
  text "B" at 9064.65,3036.41 h44.28
  text "31" at 9372.02,2946.78 h60
  text "11.81mil (0.300mm)" at 9689.2,2946.78 h60
  text "PTH" at 10310.95,2946.78 h60
  text "Round" at 10555.27,2946.78 h60
  text "C" at 9064.65,2936.79 h44.28
  text "20" at 9372.02,2847.16 h60
  text "39.37mil (1.000mm)" at 9689.2,2847.16 h60
  text "PTH" at 10310.95,2847.16 h60
  text "Round" at 10555.27,2847.16 h60
  text "8" at 9372.02,2747.54 h60
  text "64.96mil (1.650mm)" at 9689.2,2747.54 h60
  text "PTH" at 10310.95,2747.54 h60
  text "Round" at 10555.27,2747.54 h60
  text "4" at 9372.02,2647.92 h60
  text "125.98mil (3.200mm)" at 9689.2,2647.92 h60
  text "PTH" at 10310.95,2647.92 h60
  text "Round" at 10555.27,2647.92 h60
  text "2" at 9372.02,2548.29 h60
  text "29.92mil (0.760mm)" at 9689.2,2548.29 h60
  text "PTH" at 10310.95,2548.29 h60
  text "Slot" at 10555.27,2548.29 h60
  text "1" at 9372.02,2448.67 h60
  text "39.76mil (1.010mm)" at 9689.2,2448.67 h60
  text "PTH" at 10310.95,2448.67 h60
  text "Slot" at 10555.27,2448.67 h60
  text "1108 Total" at 9372.02,2349.05 h60
  text "Slot definitions :" at 9086.27,2269.44 h60
  text "Routed Path Length" at 9529.58,2269.44 h60
  text "= Calculated from tool start centre position to tool end centre position." at 10061.91,2269.44 h60
  text "Hole Length" at 9529.58,2219.71 h60
  text "= Routed Path Length + Tool Size = Slot length as defined in the PCB layout" at 9862.11,2219.71 h60
  text ".Layer_Name" at 577,-858.49 h60
Mechanical 17:
  lines w39.37: 4169.29,1431.1 cw(c4120.08,1431.1) 4120.08,1381.89 3720.47,1381.89 3633.86,1468.5 3633.86,1848.43 cw(c3675.2,1848.43) 3675.2,1889.76 3789.37,1889.76 3846.46,1832.68 4069.29,1832.68 cw(c4069.29,1732.68) 4169.29,1732.68 4169.29,1433.07 ; 3633.86,407.48 ccw(c3675.2,407.48) 3675.2,366.14 3990.16,366.14 4037.4,318.9 4120.08,318.9 ccw(c4120.08,368.11) 4169.29,368.11 4169.29,667.32 ccw(c4070.87,667.32) 4070.87,765.75 3820.87,765.75 3789.37,797.24 3675.2,797.24 ccw(c3675.2,755.91) 3633.86,755.91 3633.86,407.48

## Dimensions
0,0 to 4600,0 on M2 Board Dimensions
0,3740 to 0,0 on M2 Board Dimensions
0,-400 to 1000,-400 on M2 Board Dimensions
